VERSION 5.8 ;
BUSBITCHARS "[]" ;
DIVIDERCHAR "/" ;
UNITS
    DATABASE MICRONS 1000 ;
END UNITS

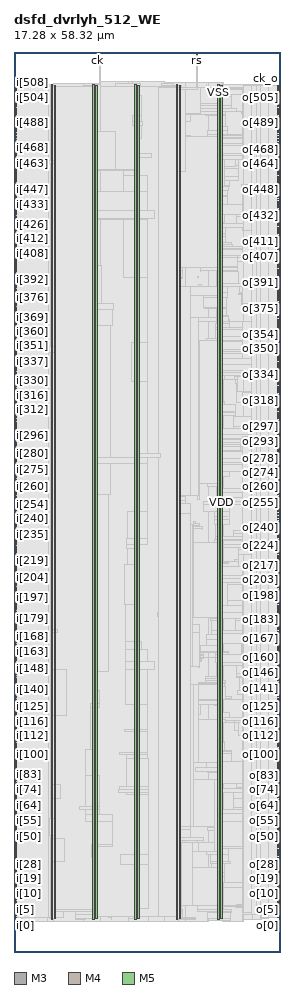
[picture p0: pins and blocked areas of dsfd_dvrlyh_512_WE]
MACRO dsfd_dvrlyh_512_WE
  FOREIGN dsfd_dvrlyh_512_WE 0 0 ;
  CLASS BLOCK ;
  SIZE 17.28 BY 58.32 ;
  PIN ck
    DIRECTION INPUT ;
    USE SIGNAL ;
    PORT
      LAYER M3 ;
        RECT  5.4 58.176 5.418 58.32 ;
    END
  END ck
  PIN ck_o
    DIRECTION OUTPUT ;
    USE SIGNAL ;
    PORT
      LAYER M4 ;
        RECT  17.088 56.112 17.28 56.136 ;
    END
  END ck_o
  PIN i[0]
    DIRECTION INPUT ;
    USE SIGNAL ;
    PORT
      LAYER M4 ;
        RECT  0 2.208 0.192 2.232 ;
    END
  END i[0]
  PIN i[100]
    DIRECTION INPUT ;
    USE SIGNAL ;
    PORT
      LAYER M4 ;
        RECT  0 12.768 0.192 12.792 ;
    END
  END i[100]
  PIN i[101]
    DIRECTION INPUT ;
    USE SIGNAL ;
    PORT
      LAYER M4 ;
        RECT  0 12.864 0.192 12.888 ;
    END
  END i[101]
  PIN i[102]
    DIRECTION INPUT ;
    USE SIGNAL ;
    PORT
      LAYER M4 ;
        RECT  0 12.96 0.192 12.984 ;
    END
  END i[102]
  PIN i[103]
    DIRECTION INPUT ;
    USE SIGNAL ;
    PORT
      LAYER M4 ;
        RECT  0 13.104 0.192 13.128 ;
    END
  END i[103]
  PIN i[104]
    DIRECTION INPUT ;
    USE SIGNAL ;
    PORT
      LAYER M4 ;
        RECT  0 13.2 0.192 13.224 ;
    END
  END i[104]
  PIN i[105]
    DIRECTION INPUT ;
    USE SIGNAL ;
    PORT
      LAYER M4 ;
        RECT  0 13.296 0.192 13.32 ;
    END
  END i[105]
  PIN i[106]
    DIRECTION INPUT ;
    USE SIGNAL ;
    PORT
      LAYER M4 ;
        RECT  0 13.392 0.192 13.416 ;
    END
  END i[106]
  PIN i[107]
    DIRECTION INPUT ;
    USE SIGNAL ;
    PORT
      LAYER M4 ;
        RECT  0 13.488 0.192 13.512 ;
    END
  END i[107]
  PIN i[108]
    DIRECTION INPUT ;
    USE SIGNAL ;
    PORT
      LAYER M4 ;
        RECT  0 13.632 0.192 13.656 ;
    END
  END i[108]
  PIN i[109]
    DIRECTION INPUT ;
    USE SIGNAL ;
    PORT
      LAYER M4 ;
        RECT  0 13.728 0.192 13.752 ;
    END
  END i[109]
  PIN i[10]
    DIRECTION INPUT ;
    USE SIGNAL ;
    PORT
      LAYER M4 ;
        RECT  0 3.264 0.192 3.288 ;
    END
  END i[10]
  PIN i[110]
    DIRECTION INPUT ;
    USE SIGNAL ;
    PORT
      LAYER M4 ;
        RECT  0 13.824 0.192 13.848 ;
    END
  END i[110]
  PIN i[111]
    DIRECTION INPUT ;
    USE SIGNAL ;
    PORT
      LAYER M4 ;
        RECT  0 13.92 0.192 13.944 ;
    END
  END i[111]
  PIN i[112]
    DIRECTION INPUT ;
    USE SIGNAL ;
    PORT
      LAYER M4 ;
        RECT  0 14.016 0.192 14.04 ;
    END
  END i[112]
  PIN i[113]
    DIRECTION INPUT ;
    USE SIGNAL ;
    PORT
      LAYER M4 ;
        RECT  0 14.16 0.192 14.184 ;
    END
  END i[113]
  PIN i[114]
    DIRECTION INPUT ;
    USE SIGNAL ;
    PORT
      LAYER M4 ;
        RECT  0 14.256 0.192 14.28 ;
    END
  END i[114]
  PIN i[115]
    DIRECTION INPUT ;
    USE SIGNAL ;
    PORT
      LAYER M4 ;
        RECT  0 14.352 0.192 14.376 ;
    END
  END i[115]
  PIN i[116]
    DIRECTION INPUT ;
    USE SIGNAL ;
    PORT
      LAYER M4 ;
        RECT  0 14.448 0.192 14.472 ;
    END
  END i[116]
  PIN i[117]
    DIRECTION INPUT ;
    USE SIGNAL ;
    PORT
      LAYER M4 ;
        RECT  0 14.544 0.192 14.568 ;
    END
  END i[117]
  PIN i[118]
    DIRECTION INPUT ;
    USE SIGNAL ;
    PORT
      LAYER M4 ;
        RECT  0 14.688 0.192 14.712 ;
    END
  END i[118]
  PIN i[119]
    DIRECTION INPUT ;
    USE SIGNAL ;
    PORT
      LAYER M4 ;
        RECT  0 14.784 0.192 14.808 ;
    END
  END i[119]
  PIN i[11]
    DIRECTION INPUT ;
    USE SIGNAL ;
    PORT
      LAYER M4 ;
        RECT  0 3.408 0.192 3.432 ;
    END
  END i[11]
  PIN i[120]
    DIRECTION INPUT ;
    USE SIGNAL ;
    PORT
      LAYER M4 ;
        RECT  0 14.88 0.192 14.904 ;
    END
  END i[120]
  PIN i[121]
    DIRECTION INPUT ;
    USE SIGNAL ;
    PORT
      LAYER M4 ;
        RECT  0 14.976 0.192 15 ;
    END
  END i[121]
  PIN i[122]
    DIRECTION INPUT ;
    USE SIGNAL ;
    PORT
      LAYER M4 ;
        RECT  0 15.072 0.192 15.096 ;
    END
  END i[122]
  PIN i[123]
    DIRECTION INPUT ;
    USE SIGNAL ;
    PORT
      LAYER M4 ;
        RECT  0 15.216 0.192 15.24 ;
    END
  END i[123]
  PIN i[124]
    DIRECTION INPUT ;
    USE SIGNAL ;
    PORT
      LAYER M4 ;
        RECT  0 15.312 0.192 15.336 ;
    END
  END i[124]
  PIN i[125]
    DIRECTION INPUT ;
    USE SIGNAL ;
    PORT
      LAYER M4 ;
        RECT  0 15.408 0.192 15.432 ;
    END
  END i[125]
  PIN i[126]
    DIRECTION INPUT ;
    USE SIGNAL ;
    PORT
      LAYER M4 ;
        RECT  0 15.504 0.192 15.528 ;
    END
  END i[126]
  PIN i[127]
    DIRECTION INPUT ;
    USE SIGNAL ;
    PORT
      LAYER M4 ;
        RECT  0 15.6 0.192 15.624 ;
    END
  END i[127]
  PIN i[128]
    DIRECTION INPUT ;
    USE SIGNAL ;
    PORT
      LAYER M4 ;
        RECT  0 15.744 0.192 15.768 ;
    END
  END i[128]
  PIN i[129]
    DIRECTION INPUT ;
    USE SIGNAL ;
    PORT
      LAYER M4 ;
        RECT  0 15.84 0.192 15.864 ;
    END
  END i[129]
  PIN i[12]
    DIRECTION INPUT ;
    USE SIGNAL ;
    PORT
      LAYER M4 ;
        RECT  0 3.504 0.192 3.528 ;
    END
  END i[12]
  PIN i[130]
    DIRECTION INPUT ;
    USE SIGNAL ;
    PORT
      LAYER M4 ;
        RECT  0 15.936 0.192 15.96 ;
    END
  END i[130]
  PIN i[131]
    DIRECTION INPUT ;
    USE SIGNAL ;
    PORT
      LAYER M4 ;
        RECT  0 16.032 0.192 16.056 ;
    END
  END i[131]
  PIN i[132]
    DIRECTION INPUT ;
    USE SIGNAL ;
    PORT
      LAYER M4 ;
        RECT  0 16.128 0.192 16.152 ;
    END
  END i[132]
  PIN i[133]
    DIRECTION INPUT ;
    USE SIGNAL ;
    PORT
      LAYER M4 ;
        RECT  0 16.272 0.192 16.296 ;
    END
  END i[133]
  PIN i[134]
    DIRECTION INPUT ;
    USE SIGNAL ;
    PORT
      LAYER M4 ;
        RECT  0 16.368 0.192 16.392 ;
    END
  END i[134]
  PIN i[135]
    DIRECTION INPUT ;
    USE SIGNAL ;
    PORT
      LAYER M4 ;
        RECT  0 16.464 0.192 16.488 ;
    END
  END i[135]
  PIN i[136]
    DIRECTION INPUT ;
    USE SIGNAL ;
    PORT
      LAYER M4 ;
        RECT  0 16.56 0.192 16.584 ;
    END
  END i[136]
  PIN i[137]
    DIRECTION INPUT ;
    USE SIGNAL ;
    PORT
      LAYER M4 ;
        RECT  0 16.656 0.192 16.68 ;
    END
  END i[137]
  PIN i[138]
    DIRECTION INPUT ;
    USE SIGNAL ;
    PORT
      LAYER M4 ;
        RECT  0 16.8 0.192 16.824 ;
    END
  END i[138]
  PIN i[139]
    DIRECTION INPUT ;
    USE SIGNAL ;
    PORT
      LAYER M4 ;
        RECT  0 16.896 0.192 16.92 ;
    END
  END i[139]
  PIN i[13]
    DIRECTION INPUT ;
    USE SIGNAL ;
    PORT
      LAYER M4 ;
        RECT  0 3.6 0.192 3.624 ;
    END
  END i[13]
  PIN i[140]
    DIRECTION INPUT ;
    USE SIGNAL ;
    PORT
      LAYER M4 ;
        RECT  0 16.992 0.192 17.016 ;
    END
  END i[140]
  PIN i[141]
    DIRECTION INPUT ;
    USE SIGNAL ;
    PORT
      LAYER M4 ;
        RECT  0 17.088 0.192 17.112 ;
    END
  END i[141]
  PIN i[142]
    DIRECTION INPUT ;
    USE SIGNAL ;
    PORT
      LAYER M4 ;
        RECT  0 17.184 0.192 17.208 ;
    END
  END i[142]
  PIN i[143]
    DIRECTION INPUT ;
    USE SIGNAL ;
    PORT
      LAYER M4 ;
        RECT  0 17.328 0.192 17.352 ;
    END
  END i[143]
  PIN i[144]
    DIRECTION INPUT ;
    USE SIGNAL ;
    PORT
      LAYER M4 ;
        RECT  0 17.424 0.192 17.448 ;
    END
  END i[144]
  PIN i[145]
    DIRECTION INPUT ;
    USE SIGNAL ;
    PORT
      LAYER M4 ;
        RECT  0 17.52 0.192 17.544 ;
    END
  END i[145]
  PIN i[146]
    DIRECTION INPUT ;
    USE SIGNAL ;
    PORT
      LAYER M4 ;
        RECT  0 17.616 0.192 17.64 ;
    END
  END i[146]
  PIN i[147]
    DIRECTION INPUT ;
    USE SIGNAL ;
    PORT
      LAYER M4 ;
        RECT  0 17.712 0.192 17.736 ;
    END
  END i[147]
  PIN i[148]
    DIRECTION INPUT ;
    USE SIGNAL ;
    PORT
      LAYER M4 ;
        RECT  0 17.856 0.192 17.88 ;
    END
  END i[148]
  PIN i[149]
    DIRECTION INPUT ;
    USE SIGNAL ;
    PORT
      LAYER M4 ;
        RECT  0 17.952 0.192 17.976 ;
    END
  END i[149]
  PIN i[14]
    DIRECTION INPUT ;
    USE SIGNAL ;
    PORT
      LAYER M4 ;
        RECT  0 3.696 0.192 3.72 ;
    END
  END i[14]
  PIN i[150]
    DIRECTION INPUT ;
    USE SIGNAL ;
    PORT
      LAYER M4 ;
        RECT  0 18.048 0.192 18.072 ;
    END
  END i[150]
  PIN i[151]
    DIRECTION INPUT ;
    USE SIGNAL ;
    PORT
      LAYER M4 ;
        RECT  0 18.144 0.192 18.168 ;
    END
  END i[151]
  PIN i[152]
    DIRECTION INPUT ;
    USE SIGNAL ;
    PORT
      LAYER M4 ;
        RECT  0 18.24 0.192 18.264 ;
    END
  END i[152]
  PIN i[153]
    DIRECTION INPUT ;
    USE SIGNAL ;
    PORT
      LAYER M4 ;
        RECT  0 18.384 0.192 18.408 ;
    END
  END i[153]
  PIN i[154]
    DIRECTION INPUT ;
    USE SIGNAL ;
    PORT
      LAYER M4 ;
        RECT  0 18.48 0.192 18.504 ;
    END
  END i[154]
  PIN i[155]
    DIRECTION INPUT ;
    USE SIGNAL ;
    PORT
      LAYER M4 ;
        RECT  0 18.576 0.192 18.6 ;
    END
  END i[155]
  PIN i[156]
    DIRECTION INPUT ;
    USE SIGNAL ;
    PORT
      LAYER M4 ;
        RECT  0 18.672 0.192 18.696 ;
    END
  END i[156]
  PIN i[157]
    DIRECTION INPUT ;
    USE SIGNAL ;
    PORT
      LAYER M4 ;
        RECT  0 18.768 0.192 18.792 ;
    END
  END i[157]
  PIN i[158]
    DIRECTION INPUT ;
    USE SIGNAL ;
    PORT
      LAYER M4 ;
        RECT  0 18.912 0.192 18.936 ;
    END
  END i[158]
  PIN i[159]
    DIRECTION INPUT ;
    USE SIGNAL ;
    PORT
      LAYER M4 ;
        RECT  0 19.008 0.192 19.032 ;
    END
  END i[159]
  PIN i[15]
    DIRECTION INPUT ;
    USE SIGNAL ;
    PORT
      LAYER M4 ;
        RECT  0 3.792 0.192 3.816 ;
    END
  END i[15]
  PIN i[160]
    DIRECTION INPUT ;
    USE SIGNAL ;
    PORT
      LAYER M4 ;
        RECT  0 19.104 0.192 19.128 ;
    END
  END i[160]
  PIN i[161]
    DIRECTION INPUT ;
    USE SIGNAL ;
    PORT
      LAYER M4 ;
        RECT  0 19.2 0.192 19.224 ;
    END
  END i[161]
  PIN i[162]
    DIRECTION INPUT ;
    USE SIGNAL ;
    PORT
      LAYER M4 ;
        RECT  0 19.296 0.192 19.32 ;
    END
  END i[162]
  PIN i[163]
    DIRECTION INPUT ;
    USE SIGNAL ;
    PORT
      LAYER M4 ;
        RECT  0 19.44 0.192 19.464 ;
    END
  END i[163]
  PIN i[164]
    DIRECTION INPUT ;
    USE SIGNAL ;
    PORT
      LAYER M4 ;
        RECT  0 19.536 0.192 19.56 ;
    END
  END i[164]
  PIN i[165]
    DIRECTION INPUT ;
    USE SIGNAL ;
    PORT
      LAYER M4 ;
        RECT  0 19.632 0.192 19.656 ;
    END
  END i[165]
  PIN i[166]
    DIRECTION INPUT ;
    USE SIGNAL ;
    PORT
      LAYER M4 ;
        RECT  0 19.728 0.192 19.752 ;
    END
  END i[166]
  PIN i[167]
    DIRECTION INPUT ;
    USE SIGNAL ;
    PORT
      LAYER M4 ;
        RECT  0 19.824 0.192 19.848 ;
    END
  END i[167]
  PIN i[168]
    DIRECTION INPUT ;
    USE SIGNAL ;
    PORT
      LAYER M4 ;
        RECT  0 19.92 0.192 19.944 ;
    END
  END i[168]
  PIN i[169]
    DIRECTION INPUT ;
    USE SIGNAL ;
    PORT
      LAYER M4 ;
        RECT  0 20.064 0.192 20.088 ;
    END
  END i[169]
  PIN i[16]
    DIRECTION INPUT ;
    USE SIGNAL ;
    PORT
      LAYER M4 ;
        RECT  0 3.936 0.192 3.96 ;
    END
  END i[16]
  PIN i[170]
    DIRECTION INPUT ;
    USE SIGNAL ;
    PORT
      LAYER M4 ;
        RECT  0 20.16 0.192 20.184 ;
    END
  END i[170]
  PIN i[171]
    DIRECTION INPUT ;
    USE SIGNAL ;
    PORT
      LAYER M4 ;
        RECT  0 20.256 0.192 20.28 ;
    END
  END i[171]
  PIN i[172]
    DIRECTION INPUT ;
    USE SIGNAL ;
    PORT
      LAYER M4 ;
        RECT  0 20.352 0.192 20.376 ;
    END
  END i[172]
  PIN i[173]
    DIRECTION INPUT ;
    USE SIGNAL ;
    PORT
      LAYER M4 ;
        RECT  0 20.448 0.192 20.472 ;
    END
  END i[173]
  PIN i[174]
    DIRECTION INPUT ;
    USE SIGNAL ;
    PORT
      LAYER M4 ;
        RECT  0 20.592 0.192 20.616 ;
    END
  END i[174]
  PIN i[175]
    DIRECTION INPUT ;
    USE SIGNAL ;
    PORT
      LAYER M4 ;
        RECT  0 20.688 0.192 20.712 ;
    END
  END i[175]
  PIN i[176]
    DIRECTION INPUT ;
    USE SIGNAL ;
    PORT
      LAYER M4 ;
        RECT  0 20.784 0.192 20.808 ;
    END
  END i[176]
  PIN i[177]
    DIRECTION INPUT ;
    USE SIGNAL ;
    PORT
      LAYER M4 ;
        RECT  0 20.88 0.192 20.904 ;
    END
  END i[177]
  PIN i[178]
    DIRECTION INPUT ;
    USE SIGNAL ;
    PORT
      LAYER M4 ;
        RECT  0 20.976 0.192 21 ;
    END
  END i[178]
  PIN i[179]
    DIRECTION INPUT ;
    USE SIGNAL ;
    PORT
      LAYER M4 ;
        RECT  0 21.12 0.192 21.144 ;
    END
  END i[179]
  PIN i[17]
    DIRECTION INPUT ;
    USE SIGNAL ;
    PORT
      LAYER M4 ;
        RECT  0 4.032 0.192 4.056 ;
    END
  END i[17]
  PIN i[180]
    DIRECTION INPUT ;
    USE SIGNAL ;
    PORT
      LAYER M4 ;
        RECT  0 21.216 0.192 21.24 ;
    END
  END i[180]
  PIN i[181]
    DIRECTION INPUT ;
    USE SIGNAL ;
    PORT
      LAYER M4 ;
        RECT  0 21.312 0.192 21.336 ;
    END
  END i[181]
  PIN i[182]
    DIRECTION INPUT ;
    USE SIGNAL ;
    PORT
      LAYER M4 ;
        RECT  0 21.408 0.192 21.432 ;
    END
  END i[182]
  PIN i[183]
    DIRECTION INPUT ;
    USE SIGNAL ;
    PORT
      LAYER M4 ;
        RECT  0 21.504 0.192 21.528 ;
    END
  END i[183]
  PIN i[184]
    DIRECTION INPUT ;
    USE SIGNAL ;
    PORT
      LAYER M4 ;
        RECT  0 21.648 0.192 21.672 ;
    END
  END i[184]
  PIN i[185]
    DIRECTION INPUT ;
    USE SIGNAL ;
    PORT
      LAYER M4 ;
        RECT  0 21.744 0.192 21.768 ;
    END
  END i[185]
  PIN i[186]
    DIRECTION INPUT ;
    USE SIGNAL ;
    PORT
      LAYER M4 ;
        RECT  0 21.84 0.192 21.864 ;
    END
  END i[186]
  PIN i[187]
    DIRECTION INPUT ;
    USE SIGNAL ;
    PORT
      LAYER M4 ;
        RECT  0 21.936 0.192 21.96 ;
    END
  END i[187]
  PIN i[188]
    DIRECTION INPUT ;
    USE SIGNAL ;
    PORT
      LAYER M4 ;
        RECT  0 22.032 0.192 22.056 ;
    END
  END i[188]
  PIN i[189]
    DIRECTION INPUT ;
    USE SIGNAL ;
    PORT
      LAYER M4 ;
        RECT  0 22.176 0.192 22.2 ;
    END
  END i[189]
  PIN i[18]
    DIRECTION INPUT ;
    USE SIGNAL ;
    PORT
      LAYER M4 ;
        RECT  0 4.128 0.192 4.152 ;
    END
  END i[18]
  PIN i[190]
    DIRECTION INPUT ;
    USE SIGNAL ;
    PORT
      LAYER M4 ;
        RECT  0 22.272 0.192 22.296 ;
    END
  END i[190]
  PIN i[191]
    DIRECTION INPUT ;
    USE SIGNAL ;
    PORT
      LAYER M4 ;
        RECT  0 22.368 0.192 22.392 ;
    END
  END i[191]
  PIN i[192]
    DIRECTION INPUT ;
    USE SIGNAL ;
    PORT
      LAYER M4 ;
        RECT  0 22.464 0.192 22.488 ;
    END
  END i[192]
  PIN i[193]
    DIRECTION INPUT ;
    USE SIGNAL ;
    PORT
      LAYER M4 ;
        RECT  0 22.56 0.192 22.584 ;
    END
  END i[193]
  PIN i[194]
    DIRECTION INPUT ;
    USE SIGNAL ;
    PORT
      LAYER M4 ;
        RECT  0 22.704 0.192 22.728 ;
    END
  END i[194]
  PIN i[195]
    DIRECTION INPUT ;
    USE SIGNAL ;
    PORT
      LAYER M4 ;
        RECT  0 22.8 0.192 22.824 ;
    END
  END i[195]
  PIN i[196]
    DIRECTION INPUT ;
    USE SIGNAL ;
    PORT
      LAYER M4 ;
        RECT  0 22.896 0.192 22.92 ;
    END
  END i[196]
  PIN i[197]
    DIRECTION INPUT ;
    USE SIGNAL ;
    PORT
      LAYER M4 ;
        RECT  0 22.992 0.192 23.016 ;
    END
  END i[197]
  PIN i[198]
    DIRECTION INPUT ;
    USE SIGNAL ;
    PORT
      LAYER M4 ;
        RECT  0 23.088 0.192 23.112 ;
    END
  END i[198]
  PIN i[199]
    DIRECTION INPUT ;
    USE SIGNAL ;
    PORT
      LAYER M4 ;
        RECT  0 23.232 0.192 23.256 ;
    END
  END i[199]
  PIN i[19]
    DIRECTION INPUT ;
    USE SIGNAL ;
    PORT
      LAYER M4 ;
        RECT  0 4.224 0.192 4.248 ;
    END
  END i[19]
  PIN i[1]
    DIRECTION INPUT ;
    USE SIGNAL ;
    PORT
      LAYER M4 ;
        RECT  0 2.352 0.192 2.376 ;
    END
  END i[1]
  PIN i[200]
    DIRECTION INPUT ;
    USE SIGNAL ;
    PORT
      LAYER M4 ;
        RECT  0 23.328 0.192 23.352 ;
    END
  END i[200]
  PIN i[201]
    DIRECTION INPUT ;
    USE SIGNAL ;
    PORT
      LAYER M4 ;
        RECT  0 23.424 0.192 23.448 ;
    END
  END i[201]
  PIN i[202]
    DIRECTION INPUT ;
    USE SIGNAL ;
    PORT
      LAYER M4 ;
        RECT  0 23.52 0.192 23.544 ;
    END
  END i[202]
  PIN i[203]
    DIRECTION INPUT ;
    USE SIGNAL ;
    PORT
      LAYER M4 ;
        RECT  0 23.616 0.192 23.64 ;
    END
  END i[203]
  PIN i[204]
    DIRECTION INPUT ;
    USE SIGNAL ;
    PORT
      LAYER M4 ;
        RECT  0 23.76 0.192 23.784 ;
    END
  END i[204]
  PIN i[205]
    DIRECTION INPUT ;
    USE SIGNAL ;
    PORT
      LAYER M4 ;
        RECT  0 23.856 0.192 23.88 ;
    END
  END i[205]
  PIN i[206]
    DIRECTION INPUT ;
    USE SIGNAL ;
    PORT
      LAYER M4 ;
        RECT  0 23.952 0.192 23.976 ;
    END
  END i[206]
  PIN i[207]
    DIRECTION INPUT ;
    USE SIGNAL ;
    PORT
      LAYER M4 ;
        RECT  0 24.048 0.192 24.072 ;
    END
  END i[207]
  PIN i[208]
    DIRECTION INPUT ;
    USE SIGNAL ;
    PORT
      LAYER M4 ;
        RECT  0 24.144 0.192 24.168 ;
    END
  END i[208]
  PIN i[209]
    DIRECTION INPUT ;
    USE SIGNAL ;
    PORT
      LAYER M4 ;
        RECT  0 24.288 0.192 24.312 ;
    END
  END i[209]
  PIN i[20]
    DIRECTION INPUT ;
    USE SIGNAL ;
    PORT
      LAYER M4 ;
        RECT  0 4.32 0.192 4.344 ;
    END
  END i[20]
  PIN i[210]
    DIRECTION INPUT ;
    USE SIGNAL ;
    PORT
      LAYER M4 ;
        RECT  0 24.384 0.192 24.408 ;
    END
  END i[210]
  PIN i[211]
    DIRECTION INPUT ;
    USE SIGNAL ;
    PORT
      LAYER M4 ;
        RECT  0 24.48 0.192 24.504 ;
    END
  END i[211]
  PIN i[212]
    DIRECTION INPUT ;
    USE SIGNAL ;
    PORT
      LAYER M4 ;
        RECT  0 24.576 0.192 24.6 ;
    END
  END i[212]
  PIN i[213]
    DIRECTION INPUT ;
    USE SIGNAL ;
    PORT
      LAYER M4 ;
        RECT  0 24.672 0.192 24.696 ;
    END
  END i[213]
  PIN i[214]
    DIRECTION INPUT ;
    USE SIGNAL ;
    PORT
      LAYER M4 ;
        RECT  0 24.816 0.192 24.84 ;
    END
  END i[214]
  PIN i[215]
    DIRECTION INPUT ;
    USE SIGNAL ;
    PORT
      LAYER M4 ;
        RECT  0 24.912 0.192 24.936 ;
    END
  END i[215]
  PIN i[216]
    DIRECTION INPUT ;
    USE SIGNAL ;
    PORT
      LAYER M4 ;
        RECT  0 25.008 0.192 25.032 ;
    END
  END i[216]
  PIN i[217]
    DIRECTION INPUT ;
    USE SIGNAL ;
    PORT
      LAYER M4 ;
        RECT  0 25.104 0.192 25.128 ;
    END
  END i[217]
  PIN i[218]
    DIRECTION INPUT ;
    USE SIGNAL ;
    PORT
      LAYER M4 ;
        RECT  0 25.2 0.192 25.224 ;
    END
  END i[218]
  PIN i[219]
    DIRECTION INPUT ;
    USE SIGNAL ;
    PORT
      LAYER M4 ;
        RECT  0 25.344 0.192 25.368 ;
    END
  END i[219]
  PIN i[21]
    DIRECTION INPUT ;
    USE SIGNAL ;
    PORT
      LAYER M4 ;
        RECT  0 4.416 0.192 4.44 ;
    END
  END i[21]
  PIN i[220]
    DIRECTION INPUT ;
    USE SIGNAL ;
    PORT
      LAYER M4 ;
        RECT  0 25.44 0.192 25.464 ;
    END
  END i[220]
  PIN i[221]
    DIRECTION INPUT ;
    USE SIGNAL ;
    PORT
      LAYER M4 ;
        RECT  0 25.536 0.192 25.56 ;
    END
  END i[221]
  PIN i[222]
    DIRECTION INPUT ;
    USE SIGNAL ;
    PORT
      LAYER M4 ;
        RECT  0 25.632 0.192 25.656 ;
    END
  END i[222]
  PIN i[223]
    DIRECTION INPUT ;
    USE SIGNAL ;
    PORT
      LAYER M4 ;
        RECT  0 25.728 0.192 25.752 ;
    END
  END i[223]
  PIN i[224]
    DIRECTION INPUT ;
    USE SIGNAL ;
    PORT
      LAYER M4 ;
        RECT  0 25.872 0.192 25.896 ;
    END
  END i[224]
  PIN i[225]
    DIRECTION INPUT ;
    USE SIGNAL ;
    PORT
      LAYER M4 ;
        RECT  0 25.968 0.192 25.992 ;
    END
  END i[225]
  PIN i[226]
    DIRECTION INPUT ;
    USE SIGNAL ;
    PORT
      LAYER M4 ;
        RECT  0 26.064 0.192 26.088 ;
    END
  END i[226]
  PIN i[227]
    DIRECTION INPUT ;
    USE SIGNAL ;
    PORT
      LAYER M4 ;
        RECT  0 26.16 0.192 26.184 ;
    END
  END i[227]
  PIN i[228]
    DIRECTION INPUT ;
    USE SIGNAL ;
    PORT
      LAYER M4 ;
        RECT  0 26.256 0.192 26.28 ;
    END
  END i[228]
  PIN i[229]
    DIRECTION INPUT ;
    USE SIGNAL ;
    PORT
      LAYER M4 ;
        RECT  0 26.4 0.192 26.424 ;
    END
  END i[229]
  PIN i[22]
    DIRECTION INPUT ;
    USE SIGNAL ;
    PORT
      LAYER M4 ;
        RECT  0 4.56 0.192 4.584 ;
    END
  END i[22]
  PIN i[230]
    DIRECTION INPUT ;
    USE SIGNAL ;
    PORT
      LAYER M4 ;
        RECT  0 26.496 0.192 26.52 ;
    END
  END i[230]
  PIN i[231]
    DIRECTION INPUT ;
    USE SIGNAL ;
    PORT
      LAYER M4 ;
        RECT  0 26.592 0.192 26.616 ;
    END
  END i[231]
  PIN i[232]
    DIRECTION INPUT ;
    USE SIGNAL ;
    PORT
      LAYER M4 ;
        RECT  0 26.688 0.192 26.712 ;
    END
  END i[232]
  PIN i[233]
    DIRECTION INPUT ;
    USE SIGNAL ;
    PORT
      LAYER M4 ;
        RECT  0 26.784 0.192 26.808 ;
    END
  END i[233]
  PIN i[234]
    DIRECTION INPUT ;
    USE SIGNAL ;
    PORT
      LAYER M4 ;
        RECT  0 26.928 0.192 26.952 ;
    END
  END i[234]
  PIN i[235]
    DIRECTION INPUT ;
    USE SIGNAL ;
    PORT
      LAYER M4 ;
        RECT  0 27.024 0.192 27.048 ;
    END
  END i[235]
  PIN i[236]
    DIRECTION INPUT ;
    USE SIGNAL ;
    PORT
      LAYER M4 ;
        RECT  0 27.12 0.192 27.144 ;
    END
  END i[236]
  PIN i[237]
    DIRECTION INPUT ;
    USE SIGNAL ;
    PORT
      LAYER M4 ;
        RECT  0 27.216 0.192 27.24 ;
    END
  END i[237]
  PIN i[238]
    DIRECTION INPUT ;
    USE SIGNAL ;
    PORT
      LAYER M4 ;
        RECT  0 27.312 0.192 27.336 ;
    END
  END i[238]
  PIN i[239]
    DIRECTION INPUT ;
    USE SIGNAL ;
    PORT
      LAYER M4 ;
        RECT  0 27.408 0.192 27.432 ;
    END
  END i[239]
  PIN i[23]
    DIRECTION INPUT ;
    USE SIGNAL ;
    PORT
      LAYER M4 ;
        RECT  0 4.656 0.192 4.68 ;
    END
  END i[23]
  PIN i[240]
    DIRECTION INPUT ;
    USE SIGNAL ;
    PORT
      LAYER M4 ;
        RECT  0 27.552 0.192 27.576 ;
    END
  END i[240]
  PIN i[241]
    DIRECTION INPUT ;
    USE SIGNAL ;
    PORT
      LAYER M4 ;
        RECT  0 27.648 0.192 27.672 ;
    END
  END i[241]
  PIN i[242]
    DIRECTION INPUT ;
    USE SIGNAL ;
    PORT
      LAYER M4 ;
        RECT  0 27.744 0.192 27.768 ;
    END
  END i[242]
  PIN i[243]
    DIRECTION INPUT ;
    USE SIGNAL ;
    PORT
      LAYER M4 ;
        RECT  0 27.84 0.192 27.864 ;
    END
  END i[243]
  PIN i[244]
    DIRECTION INPUT ;
    USE SIGNAL ;
    PORT
      LAYER M4 ;
        RECT  0 27.936 0.192 27.96 ;
    END
  END i[244]
  PIN i[245]
    DIRECTION INPUT ;
    USE SIGNAL ;
    PORT
      LAYER M4 ;
        RECT  0 28.08 0.192 28.104 ;
    END
  END i[245]
  PIN i[246]
    DIRECTION INPUT ;
    USE SIGNAL ;
    PORT
      LAYER M4 ;
        RECT  0 28.176 0.192 28.2 ;
    END
  END i[246]
  PIN i[247]
    DIRECTION INPUT ;
    USE SIGNAL ;
    PORT
      LAYER M4 ;
        RECT  0 28.272 0.192 28.296 ;
    END
  END i[247]
  PIN i[248]
    DIRECTION INPUT ;
    USE SIGNAL ;
    PORT
      LAYER M4 ;
        RECT  0 28.368 0.192 28.392 ;
    END
  END i[248]
  PIN i[249]
    DIRECTION INPUT ;
    USE SIGNAL ;
    PORT
      LAYER M4 ;
        RECT  0 28.464 0.192 28.488 ;
    END
  END i[249]
  PIN i[24]
    DIRECTION INPUT ;
    USE SIGNAL ;
    PORT
      LAYER M4 ;
        RECT  0 4.752 0.192 4.776 ;
    END
  END i[24]
  PIN i[250]
    DIRECTION INPUT ;
    USE SIGNAL ;
    PORT
      LAYER M4 ;
        RECT  0 28.608 0.192 28.632 ;
    END
  END i[250]
  PIN i[251]
    DIRECTION INPUT ;
    USE SIGNAL ;
    PORT
      LAYER M4 ;
        RECT  0 28.704 0.192 28.728 ;
    END
  END i[251]
  PIN i[252]
    DIRECTION INPUT ;
    USE SIGNAL ;
    PORT
      LAYER M4 ;
        RECT  0 28.8 0.192 28.824 ;
    END
  END i[252]
  PIN i[253]
    DIRECTION INPUT ;
    USE SIGNAL ;
    PORT
      LAYER M4 ;
        RECT  0 28.896 0.192 28.92 ;
    END
  END i[253]
  PIN i[254]
    DIRECTION INPUT ;
    USE SIGNAL ;
    PORT
      LAYER M4 ;
        RECT  0 28.992 0.192 29.016 ;
    END
  END i[254]
  PIN i[255]
    DIRECTION INPUT ;
    USE SIGNAL ;
    PORT
      LAYER M4 ;
        RECT  0 29.136 0.192 29.16 ;
    END
  END i[255]
  PIN i[256]
    DIRECTION INPUT ;
    USE SIGNAL ;
    PORT
      LAYER M4 ;
        RECT  0 29.232 0.192 29.256 ;
    END
  END i[256]
  PIN i[257]
    DIRECTION INPUT ;
    USE SIGNAL ;
    PORT
      LAYER M4 ;
        RECT  0 29.328 0.192 29.352 ;
    END
  END i[257]
  PIN i[258]
    DIRECTION INPUT ;
    USE SIGNAL ;
    PORT
      LAYER M4 ;
        RECT  0 29.424 0.192 29.448 ;
    END
  END i[258]
  PIN i[259]
    DIRECTION INPUT ;
    USE SIGNAL ;
    PORT
      LAYER M4 ;
        RECT  0 29.52 0.192 29.544 ;
    END
  END i[259]
  PIN i[25]
    DIRECTION INPUT ;
    USE SIGNAL ;
    PORT
      LAYER M4 ;
        RECT  0 4.848 0.192 4.872 ;
    END
  END i[25]
  PIN i[260]
    DIRECTION INPUT ;
    USE SIGNAL ;
    PORT
      LAYER M4 ;
        RECT  0 29.664 0.192 29.688 ;
    END
  END i[260]
  PIN i[261]
    DIRECTION INPUT ;
    USE SIGNAL ;
    PORT
      LAYER M4 ;
        RECT  0 29.76 0.192 29.784 ;
    END
  END i[261]
  PIN i[262]
    DIRECTION INPUT ;
    USE SIGNAL ;
    PORT
      LAYER M4 ;
        RECT  0 29.856 0.192 29.88 ;
    END
  END i[262]
  PIN i[263]
    DIRECTION INPUT ;
    USE SIGNAL ;
    PORT
      LAYER M4 ;
        RECT  0 29.952 0.192 29.976 ;
    END
  END i[263]
  PIN i[264]
    DIRECTION INPUT ;
    USE SIGNAL ;
    PORT
      LAYER M4 ;
        RECT  0 30.048 0.192 30.072 ;
    END
  END i[264]
  PIN i[265]
    DIRECTION INPUT ;
    USE SIGNAL ;
    PORT
      LAYER M4 ;
        RECT  0 30.192 0.192 30.216 ;
    END
  END i[265]
  PIN i[266]
    DIRECTION INPUT ;
    USE SIGNAL ;
    PORT
      LAYER M4 ;
        RECT  0 30.288 0.192 30.312 ;
    END
  END i[266]
  PIN i[267]
    DIRECTION INPUT ;
    USE SIGNAL ;
    PORT
      LAYER M4 ;
        RECT  0 30.384 0.192 30.408 ;
    END
  END i[267]
  PIN i[268]
    DIRECTION INPUT ;
    USE SIGNAL ;
    PORT
      LAYER M4 ;
        RECT  0 30.48 0.192 30.504 ;
    END
  END i[268]
  PIN i[269]
    DIRECTION INPUT ;
    USE SIGNAL ;
    PORT
      LAYER M4 ;
        RECT  0 30.576 0.192 30.6 ;
    END
  END i[269]
  PIN i[26]
    DIRECTION INPUT ;
    USE SIGNAL ;
    PORT
      LAYER M4 ;
        RECT  0 4.944 0.192 4.968 ;
    END
  END i[26]
  PIN i[270]
    DIRECTION INPUT ;
    USE SIGNAL ;
    PORT
      LAYER M4 ;
        RECT  0 30.72 0.192 30.744 ;
    END
  END i[270]
  PIN i[271]
    DIRECTION INPUT ;
    USE SIGNAL ;
    PORT
      LAYER M4 ;
        RECT  0 30.816 0.192 30.84 ;
    END
  END i[271]
  PIN i[272]
    DIRECTION INPUT ;
    USE SIGNAL ;
    PORT
      LAYER M4 ;
        RECT  0 30.912 0.192 30.936 ;
    END
  END i[272]
  PIN i[273]
    DIRECTION INPUT ;
    USE SIGNAL ;
    PORT
      LAYER M4 ;
        RECT  0 31.008 0.192 31.032 ;
    END
  END i[273]
  PIN i[274]
    DIRECTION INPUT ;
    USE SIGNAL ;
    PORT
      LAYER M4 ;
        RECT  0 31.104 0.192 31.128 ;
    END
  END i[274]
  PIN i[275]
    DIRECTION INPUT ;
    USE SIGNAL ;
    PORT
      LAYER M4 ;
        RECT  0 31.248 0.192 31.272 ;
    END
  END i[275]
  PIN i[276]
    DIRECTION INPUT ;
    USE SIGNAL ;
    PORT
      LAYER M4 ;
        RECT  0 31.344 0.192 31.368 ;
    END
  END i[276]
  PIN i[277]
    DIRECTION INPUT ;
    USE SIGNAL ;
    PORT
      LAYER M4 ;
        RECT  0 31.44 0.192 31.464 ;
    END
  END i[277]
  PIN i[278]
    DIRECTION INPUT ;
    USE SIGNAL ;
    PORT
      LAYER M4 ;
        RECT  0 31.536 0.192 31.56 ;
    END
  END i[278]
  PIN i[279]
    DIRECTION INPUT ;
    USE SIGNAL ;
    PORT
      LAYER M4 ;
        RECT  0 31.632 0.192 31.656 ;
    END
  END i[279]
  PIN i[27]
    DIRECTION INPUT ;
    USE SIGNAL ;
    PORT
      LAYER M4 ;
        RECT  0 5.088 0.192 5.112 ;
    END
  END i[27]
  PIN i[280]
    DIRECTION INPUT ;
    USE SIGNAL ;
    PORT
      LAYER M4 ;
        RECT  0 31.776 0.192 31.8 ;
    END
  END i[280]
  PIN i[281]
    DIRECTION INPUT ;
    USE SIGNAL ;
    PORT
      LAYER M4 ;
        RECT  0 31.872 0.192 31.896 ;
    END
  END i[281]
  PIN i[282]
    DIRECTION INPUT ;
    USE SIGNAL ;
    PORT
      LAYER M4 ;
        RECT  0 31.968 0.192 31.992 ;
    END
  END i[282]
  PIN i[283]
    DIRECTION INPUT ;
    USE SIGNAL ;
    PORT
      LAYER M4 ;
        RECT  0 32.064 0.192 32.088 ;
    END
  END i[283]
  PIN i[284]
    DIRECTION INPUT ;
    USE SIGNAL ;
    PORT
      LAYER M4 ;
        RECT  0 32.16 0.192 32.184 ;
    END
  END i[284]
  PIN i[285]
    DIRECTION INPUT ;
    USE SIGNAL ;
    PORT
      LAYER M4 ;
        RECT  0 32.304 0.192 32.328 ;
    END
  END i[285]
  PIN i[286]
    DIRECTION INPUT ;
    USE SIGNAL ;
    PORT
      LAYER M4 ;
        RECT  0 32.4 0.192 32.424 ;
    END
  END i[286]
  PIN i[287]
    DIRECTION INPUT ;
    USE SIGNAL ;
    PORT
      LAYER M4 ;
        RECT  0 32.496 0.192 32.52 ;
    END
  END i[287]
  PIN i[288]
    DIRECTION INPUT ;
    USE SIGNAL ;
    PORT
      LAYER M4 ;
        RECT  0 32.592 0.192 32.616 ;
    END
  END i[288]
  PIN i[289]
    DIRECTION INPUT ;
    USE SIGNAL ;
    PORT
      LAYER M4 ;
        RECT  0 32.688 0.192 32.712 ;
    END
  END i[289]
  PIN i[28]
    DIRECTION INPUT ;
    USE SIGNAL ;
    PORT
      LAYER M4 ;
        RECT  0 5.184 0.192 5.208 ;
    END
  END i[28]
  PIN i[290]
    DIRECTION INPUT ;
    USE SIGNAL ;
    PORT
      LAYER M4 ;
        RECT  0 32.832 0.192 32.856 ;
    END
  END i[290]
  PIN i[291]
    DIRECTION INPUT ;
    USE SIGNAL ;
    PORT
      LAYER M4 ;
        RECT  0 32.928 0.192 32.952 ;
    END
  END i[291]
  PIN i[292]
    DIRECTION INPUT ;
    USE SIGNAL ;
    PORT
      LAYER M4 ;
        RECT  0 33.024 0.192 33.048 ;
    END
  END i[292]
  PIN i[293]
    DIRECTION INPUT ;
    USE SIGNAL ;
    PORT
      LAYER M4 ;
        RECT  0 33.12 0.192 33.144 ;
    END
  END i[293]
  PIN i[294]
    DIRECTION INPUT ;
    USE SIGNAL ;
    PORT
      LAYER M4 ;
        RECT  0 33.216 0.192 33.24 ;
    END
  END i[294]
  PIN i[295]
    DIRECTION INPUT ;
    USE SIGNAL ;
    PORT
      LAYER M4 ;
        RECT  0 33.36 0.192 33.384 ;
    END
  END i[295]
  PIN i[296]
    DIRECTION INPUT ;
    USE SIGNAL ;
    PORT
      LAYER M4 ;
        RECT  0 33.456 0.192 33.48 ;
    END
  END i[296]
  PIN i[297]
    DIRECTION INPUT ;
    USE SIGNAL ;
    PORT
      LAYER M4 ;
        RECT  0 33.552 0.192 33.576 ;
    END
  END i[297]
  PIN i[298]
    DIRECTION INPUT ;
    USE SIGNAL ;
    PORT
      LAYER M4 ;
        RECT  0 33.648 0.192 33.672 ;
    END
  END i[298]
  PIN i[299]
    DIRECTION INPUT ;
    USE SIGNAL ;
    PORT
      LAYER M4 ;
        RECT  0 33.744 0.192 33.768 ;
    END
  END i[299]
  PIN i[29]
    DIRECTION INPUT ;
    USE SIGNAL ;
    PORT
      LAYER M4 ;
        RECT  0 5.28 0.192 5.304 ;
    END
  END i[29]
  PIN i[2]
    DIRECTION INPUT ;
    USE SIGNAL ;
    PORT
      LAYER M4 ;
        RECT  0 2.448 0.192 2.472 ;
    END
  END i[2]
  PIN i[300]
    DIRECTION INPUT ;
    USE SIGNAL ;
    PORT
      LAYER M4 ;
        RECT  0 33.888 0.192 33.912 ;
    END
  END i[300]
  PIN i[301]
    DIRECTION INPUT ;
    USE SIGNAL ;
    PORT
      LAYER M4 ;
        RECT  0 33.984 0.192 34.008 ;
    END
  END i[301]
  PIN i[302]
    DIRECTION INPUT ;
    USE SIGNAL ;
    PORT
      LAYER M4 ;
        RECT  0 34.08 0.192 34.104 ;
    END
  END i[302]
  PIN i[303]
    DIRECTION INPUT ;
    USE SIGNAL ;
    PORT
      LAYER M4 ;
        RECT  0 34.176 0.192 34.2 ;
    END
  END i[303]
  PIN i[304]
    DIRECTION INPUT ;
    USE SIGNAL ;
    PORT
      LAYER M4 ;
        RECT  0 34.272 0.192 34.296 ;
    END
  END i[304]
  PIN i[305]
    DIRECTION INPUT ;
    USE SIGNAL ;
    PORT
      LAYER M4 ;
        RECT  0 34.416 0.192 34.44 ;
    END
  END i[305]
  PIN i[306]
    DIRECTION INPUT ;
    USE SIGNAL ;
    PORT
      LAYER M4 ;
        RECT  0 34.512 0.192 34.536 ;
    END
  END i[306]
  PIN i[307]
    DIRECTION INPUT ;
    USE SIGNAL ;
    PORT
      LAYER M4 ;
        RECT  0 34.608 0.192 34.632 ;
    END
  END i[307]
  PIN i[308]
    DIRECTION INPUT ;
    USE SIGNAL ;
    PORT
      LAYER M4 ;
        RECT  0 34.704 0.192 34.728 ;
    END
  END i[308]
  PIN i[309]
    DIRECTION INPUT ;
    USE SIGNAL ;
    PORT
      LAYER M4 ;
        RECT  0 34.8 0.192 34.824 ;
    END
  END i[309]
  PIN i[30]
    DIRECTION INPUT ;
    USE SIGNAL ;
    PORT
      LAYER M4 ;
        RECT  0 5.376 0.192 5.4 ;
    END
  END i[30]
  PIN i[310]
    DIRECTION INPUT ;
    USE SIGNAL ;
    PORT
      LAYER M4 ;
        RECT  0 34.944 0.192 34.968 ;
    END
  END i[310]
  PIN i[311]
    DIRECTION INPUT ;
    USE SIGNAL ;
    PORT
      LAYER M4 ;
        RECT  0 35.04 0.192 35.064 ;
    END
  END i[311]
  PIN i[312]
    DIRECTION INPUT ;
    USE SIGNAL ;
    PORT
      LAYER M4 ;
        RECT  0 35.136 0.192 35.16 ;
    END
  END i[312]
  PIN i[313]
    DIRECTION INPUT ;
    USE SIGNAL ;
    PORT
      LAYER M4 ;
        RECT  0 35.232 0.192 35.256 ;
    END
  END i[313]
  PIN i[314]
    DIRECTION INPUT ;
    USE SIGNAL ;
    PORT
      LAYER M4 ;
        RECT  0 35.328 0.192 35.352 ;
    END
  END i[314]
  PIN i[315]
    DIRECTION INPUT ;
    USE SIGNAL ;
    PORT
      LAYER M4 ;
        RECT  0 35.424 0.192 35.448 ;
    END
  END i[315]
  PIN i[316]
    DIRECTION INPUT ;
    USE SIGNAL ;
    PORT
      LAYER M4 ;
        RECT  0 35.568 0.192 35.592 ;
    END
  END i[316]
  PIN i[317]
    DIRECTION INPUT ;
    USE SIGNAL ;
    PORT
      LAYER M4 ;
        RECT  0 35.664 0.192 35.688 ;
    END
  END i[317]
  PIN i[318]
    DIRECTION INPUT ;
    USE SIGNAL ;
    PORT
      LAYER M4 ;
        RECT  0 35.76 0.192 35.784 ;
    END
  END i[318]
  PIN i[319]
    DIRECTION INPUT ;
    USE SIGNAL ;
    PORT
      LAYER M4 ;
        RECT  0 35.856 0.192 35.88 ;
    END
  END i[319]
  PIN i[31]
    DIRECTION INPUT ;
    USE SIGNAL ;
    PORT
      LAYER M4 ;
        RECT  0 5.472 0.192 5.496 ;
    END
  END i[31]
  PIN i[320]
    DIRECTION INPUT ;
    USE SIGNAL ;
    PORT
      LAYER M4 ;
        RECT  0 35.952 0.192 35.976 ;
    END
  END i[320]
  PIN i[321]
    DIRECTION INPUT ;
    USE SIGNAL ;
    PORT
      LAYER M4 ;
        RECT  0 36.096 0.192 36.12 ;
    END
  END i[321]
  PIN i[322]
    DIRECTION INPUT ;
    USE SIGNAL ;
    PORT
      LAYER M4 ;
        RECT  0 36.192 0.192 36.216 ;
    END
  END i[322]
  PIN i[323]
    DIRECTION INPUT ;
    USE SIGNAL ;
    PORT
      LAYER M4 ;
        RECT  0 36.288 0.192 36.312 ;
    END
  END i[323]
  PIN i[324]
    DIRECTION INPUT ;
    USE SIGNAL ;
    PORT
      LAYER M4 ;
        RECT  0 36.384 0.192 36.408 ;
    END
  END i[324]
  PIN i[325]
    DIRECTION INPUT ;
    USE SIGNAL ;
    PORT
      LAYER M4 ;
        RECT  0 36.48 0.192 36.504 ;
    END
  END i[325]
  PIN i[326]
    DIRECTION INPUT ;
    USE SIGNAL ;
    PORT
      LAYER M4 ;
        RECT  0 36.624 0.192 36.648 ;
    END
  END i[326]
  PIN i[327]
    DIRECTION INPUT ;
    USE SIGNAL ;
    PORT
      LAYER M4 ;
        RECT  0 36.72 0.192 36.744 ;
    END
  END i[327]
  PIN i[328]
    DIRECTION INPUT ;
    USE SIGNAL ;
    PORT
      LAYER M4 ;
        RECT  0 36.816 0.192 36.84 ;
    END
  END i[328]
  PIN i[329]
    DIRECTION INPUT ;
    USE SIGNAL ;
    PORT
      LAYER M4 ;
        RECT  0 36.912 0.192 36.936 ;
    END
  END i[329]
  PIN i[32]
    DIRECTION INPUT ;
    USE SIGNAL ;
    PORT
      LAYER M4 ;
        RECT  0 5.616 0.192 5.64 ;
    END
  END i[32]
  PIN i[330]
    DIRECTION INPUT ;
    USE SIGNAL ;
    PORT
      LAYER M4 ;
        RECT  0 37.008 0.192 37.032 ;
    END
  END i[330]
  PIN i[331]
    DIRECTION INPUT ;
    USE SIGNAL ;
    PORT
      LAYER M4 ;
        RECT  0 37.152 0.192 37.176 ;
    END
  END i[331]
  PIN i[332]
    DIRECTION INPUT ;
    USE SIGNAL ;
    PORT
      LAYER M4 ;
        RECT  0 37.248 0.192 37.272 ;
    END
  END i[332]
  PIN i[333]
    DIRECTION INPUT ;
    USE SIGNAL ;
    PORT
      LAYER M4 ;
        RECT  0 37.344 0.192 37.368 ;
    END
  END i[333]
  PIN i[334]
    DIRECTION INPUT ;
    USE SIGNAL ;
    PORT
      LAYER M4 ;
        RECT  0 37.44 0.192 37.464 ;
    END
  END i[334]
  PIN i[335]
    DIRECTION INPUT ;
    USE SIGNAL ;
    PORT
      LAYER M4 ;
        RECT  0 37.536 0.192 37.56 ;
    END
  END i[335]
  PIN i[336]
    DIRECTION INPUT ;
    USE SIGNAL ;
    PORT
      LAYER M4 ;
        RECT  0 37.68 0.192 37.704 ;
    END
  END i[336]
  PIN i[337]
    DIRECTION INPUT ;
    USE SIGNAL ;
    PORT
      LAYER M4 ;
        RECT  0 37.776 0.192 37.8 ;
    END
  END i[337]
  PIN i[338]
    DIRECTION INPUT ;
    USE SIGNAL ;
    PORT
      LAYER M4 ;
        RECT  0 37.872 0.192 37.896 ;
    END
  END i[338]
  PIN i[339]
    DIRECTION INPUT ;
    USE SIGNAL ;
    PORT
      LAYER M4 ;
        RECT  0 37.968 0.192 37.992 ;
    END
  END i[339]
  PIN i[33]
    DIRECTION INPUT ;
    USE SIGNAL ;
    PORT
      LAYER M4 ;
        RECT  0 5.712 0.192 5.736 ;
    END
  END i[33]
  PIN i[340]
    DIRECTION INPUT ;
    USE SIGNAL ;
    PORT
      LAYER M4 ;
        RECT  0 38.064 0.192 38.088 ;
    END
  END i[340]
  PIN i[341]
    DIRECTION INPUT ;
    USE SIGNAL ;
    PORT
      LAYER M4 ;
        RECT  0 38.208 0.192 38.232 ;
    END
  END i[341]
  PIN i[342]
    DIRECTION INPUT ;
    USE SIGNAL ;
    PORT
      LAYER M4 ;
        RECT  0 38.304 0.192 38.328 ;
    END
  END i[342]
  PIN i[343]
    DIRECTION INPUT ;
    USE SIGNAL ;
    PORT
      LAYER M4 ;
        RECT  0 38.4 0.192 38.424 ;
    END
  END i[343]
  PIN i[344]
    DIRECTION INPUT ;
    USE SIGNAL ;
    PORT
      LAYER M4 ;
        RECT  0 38.496 0.192 38.52 ;
    END
  END i[344]
  PIN i[345]
    DIRECTION INPUT ;
    USE SIGNAL ;
    PORT
      LAYER M4 ;
        RECT  0 38.592 0.192 38.616 ;
    END
  END i[345]
  PIN i[346]
    DIRECTION INPUT ;
    USE SIGNAL ;
    PORT
      LAYER M4 ;
        RECT  0 38.736 0.192 38.76 ;
    END
  END i[346]
  PIN i[347]
    DIRECTION INPUT ;
    USE SIGNAL ;
    PORT
      LAYER M4 ;
        RECT  0 38.832 0.192 38.856 ;
    END
  END i[347]
  PIN i[348]
    DIRECTION INPUT ;
    USE SIGNAL ;
    PORT
      LAYER M4 ;
        RECT  0 38.928 0.192 38.952 ;
    END
  END i[348]
  PIN i[349]
    DIRECTION INPUT ;
    USE SIGNAL ;
    PORT
      LAYER M4 ;
        RECT  0 39.024 0.192 39.048 ;
    END
  END i[349]
  PIN i[34]
    DIRECTION INPUT ;
    USE SIGNAL ;
    PORT
      LAYER M4 ;
        RECT  0 5.808 0.192 5.832 ;
    END
  END i[34]
  PIN i[350]
    DIRECTION INPUT ;
    USE SIGNAL ;
    PORT
      LAYER M4 ;
        RECT  0 39.12 0.192 39.144 ;
    END
  END i[350]
  PIN i[351]
    DIRECTION INPUT ;
    USE SIGNAL ;
    PORT
      LAYER M4 ;
        RECT  0 39.264 0.192 39.288 ;
    END
  END i[351]
  PIN i[352]
    DIRECTION INPUT ;
    USE SIGNAL ;
    PORT
      LAYER M4 ;
        RECT  0 39.36 0.192 39.384 ;
    END
  END i[352]
  PIN i[353]
    DIRECTION INPUT ;
    USE SIGNAL ;
    PORT
      LAYER M4 ;
        RECT  0 39.456 0.192 39.48 ;
    END
  END i[353]
  PIN i[354]
    DIRECTION INPUT ;
    USE SIGNAL ;
    PORT
      LAYER M4 ;
        RECT  0 39.552 0.192 39.576 ;
    END
  END i[354]
  PIN i[355]
    DIRECTION INPUT ;
    USE SIGNAL ;
    PORT
      LAYER M4 ;
        RECT  0 39.648 0.192 39.672 ;
    END
  END i[355]
  PIN i[356]
    DIRECTION INPUT ;
    USE SIGNAL ;
    PORT
      LAYER M4 ;
        RECT  0 39.792 0.192 39.816 ;
    END
  END i[356]
  PIN i[357]
    DIRECTION INPUT ;
    USE SIGNAL ;
    PORT
      LAYER M4 ;
        RECT  0 39.888 0.192 39.912 ;
    END
  END i[357]
  PIN i[358]
    DIRECTION INPUT ;
    USE SIGNAL ;
    PORT
      LAYER M4 ;
        RECT  0 39.984 0.192 40.008 ;
    END
  END i[358]
  PIN i[359]
    DIRECTION INPUT ;
    USE SIGNAL ;
    PORT
      LAYER M4 ;
        RECT  0 40.08 0.192 40.104 ;
    END
  END i[359]
  PIN i[35]
    DIRECTION INPUT ;
    USE SIGNAL ;
    PORT
      LAYER M4 ;
        RECT  0 5.904 0.192 5.928 ;
    END
  END i[35]
  PIN i[360]
    DIRECTION INPUT ;
    USE SIGNAL ;
    PORT
      LAYER M4 ;
        RECT  0 40.176 0.192 40.2 ;
    END
  END i[360]
  PIN i[361]
    DIRECTION INPUT ;
    USE SIGNAL ;
    PORT
      LAYER M4 ;
        RECT  0 40.32 0.192 40.344 ;
    END
  END i[361]
  PIN i[362]
    DIRECTION INPUT ;
    USE SIGNAL ;
    PORT
      LAYER M4 ;
        RECT  0 40.416 0.192 40.44 ;
    END
  END i[362]
  PIN i[363]
    DIRECTION INPUT ;
    USE SIGNAL ;
    PORT
      LAYER M4 ;
        RECT  0 40.512 0.192 40.536 ;
    END
  END i[363]
  PIN i[364]
    DIRECTION INPUT ;
    USE SIGNAL ;
    PORT
      LAYER M4 ;
        RECT  0 40.608 0.192 40.632 ;
    END
  END i[364]
  PIN i[365]
    DIRECTION INPUT ;
    USE SIGNAL ;
    PORT
      LAYER M4 ;
        RECT  0 40.704 0.192 40.728 ;
    END
  END i[365]
  PIN i[366]
    DIRECTION INPUT ;
    USE SIGNAL ;
    PORT
      LAYER M4 ;
        RECT  0 40.848 0.192 40.872 ;
    END
  END i[366]
  PIN i[367]
    DIRECTION INPUT ;
    USE SIGNAL ;
    PORT
      LAYER M4 ;
        RECT  0 40.944 0.192 40.968 ;
    END
  END i[367]
  PIN i[368]
    DIRECTION INPUT ;
    USE SIGNAL ;
    PORT
      LAYER M4 ;
        RECT  0 41.04 0.192 41.064 ;
    END
  END i[368]
  PIN i[369]
    DIRECTION INPUT ;
    USE SIGNAL ;
    PORT
      LAYER M4 ;
        RECT  0 41.136 0.192 41.16 ;
    END
  END i[369]
  PIN i[36]
    DIRECTION INPUT ;
    USE SIGNAL ;
    PORT
      LAYER M4 ;
        RECT  0 6 0.192 6.024 ;
    END
  END i[36]
  PIN i[370]
    DIRECTION INPUT ;
    USE SIGNAL ;
    PORT
      LAYER M4 ;
        RECT  0 41.232 0.192 41.256 ;
    END
  END i[370]
  PIN i[371]
    DIRECTION INPUT ;
    USE SIGNAL ;
    PORT
      LAYER M4 ;
        RECT  0 41.376 0.192 41.4 ;
    END
  END i[371]
  PIN i[372]
    DIRECTION INPUT ;
    USE SIGNAL ;
    PORT
      LAYER M4 ;
        RECT  0 41.472 0.192 41.496 ;
    END
  END i[372]
  PIN i[373]
    DIRECTION INPUT ;
    USE SIGNAL ;
    PORT
      LAYER M4 ;
        RECT  0 41.568 0.192 41.592 ;
    END
  END i[373]
  PIN i[374]
    DIRECTION INPUT ;
    USE SIGNAL ;
    PORT
      LAYER M4 ;
        RECT  0 41.664 0.192 41.688 ;
    END
  END i[374]
  PIN i[375]
    DIRECTION INPUT ;
    USE SIGNAL ;
    PORT
      LAYER M4 ;
        RECT  0 41.76 0.192 41.784 ;
    END
  END i[375]
  PIN i[376]
    DIRECTION INPUT ;
    USE SIGNAL ;
    PORT
      LAYER M4 ;
        RECT  0 41.904 0.192 41.928 ;
    END
  END i[376]
  PIN i[377]
    DIRECTION INPUT ;
    USE SIGNAL ;
    PORT
      LAYER M4 ;
        RECT  0 42 0.192 42.024 ;
    END
  END i[377]
  PIN i[378]
    DIRECTION INPUT ;
    USE SIGNAL ;
    PORT
      LAYER M4 ;
        RECT  0 42.096 0.192 42.12 ;
    END
  END i[378]
  PIN i[379]
    DIRECTION INPUT ;
    USE SIGNAL ;
    PORT
      LAYER M4 ;
        RECT  0 42.192 0.192 42.216 ;
    END
  END i[379]
  PIN i[37]
    DIRECTION INPUT ;
    USE SIGNAL ;
    PORT
      LAYER M4 ;
        RECT  0 6.144 0.192 6.168 ;
    END
  END i[37]
  PIN i[380]
    DIRECTION INPUT ;
    USE SIGNAL ;
    PORT
      LAYER M4 ;
        RECT  0 42.288 0.192 42.312 ;
    END
  END i[380]
  PIN i[381]
    DIRECTION INPUT ;
    USE SIGNAL ;
    PORT
      LAYER M4 ;
        RECT  0 42.432 0.192 42.456 ;
    END
  END i[381]
  PIN i[382]
    DIRECTION INPUT ;
    USE SIGNAL ;
    PORT
      LAYER M4 ;
        RECT  0 42.528 0.192 42.552 ;
    END
  END i[382]
  PIN i[383]
    DIRECTION INPUT ;
    USE SIGNAL ;
    PORT
      LAYER M4 ;
        RECT  0 42.624 0.192 42.648 ;
    END
  END i[383]
  PIN i[384]
    DIRECTION INPUT ;
    USE SIGNAL ;
    PORT
      LAYER M4 ;
        RECT  0 42.72 0.192 42.744 ;
    END
  END i[384]
  PIN i[385]
    DIRECTION INPUT ;
    USE SIGNAL ;
    PORT
      LAYER M4 ;
        RECT  0 42.816 0.192 42.84 ;
    END
  END i[385]
  PIN i[386]
    DIRECTION INPUT ;
    USE SIGNAL ;
    PORT
      LAYER M4 ;
        RECT  0 42.912 0.192 42.936 ;
    END
  END i[386]
  PIN i[387]
    DIRECTION INPUT ;
    USE SIGNAL ;
    PORT
      LAYER M4 ;
        RECT  0 43.056 0.192 43.08 ;
    END
  END i[387]
  PIN i[388]
    DIRECTION INPUT ;
    USE SIGNAL ;
    PORT
      LAYER M4 ;
        RECT  0 43.152 0.192 43.176 ;
    END
  END i[388]
  PIN i[389]
    DIRECTION INPUT ;
    USE SIGNAL ;
    PORT
      LAYER M4 ;
        RECT  0 43.248 0.192 43.272 ;
    END
  END i[389]
  PIN i[38]
    DIRECTION INPUT ;
    USE SIGNAL ;
    PORT
      LAYER M4 ;
        RECT  0 6.24 0.192 6.264 ;
    END
  END i[38]
  PIN i[390]
    DIRECTION INPUT ;
    USE SIGNAL ;
    PORT
      LAYER M4 ;
        RECT  0 43.344 0.192 43.368 ;
    END
  END i[390]
  PIN i[391]
    DIRECTION INPUT ;
    USE SIGNAL ;
    PORT
      LAYER M4 ;
        RECT  0 43.44 0.192 43.464 ;
    END
  END i[391]
  PIN i[392]
    DIRECTION INPUT ;
    USE SIGNAL ;
    PORT
      LAYER M4 ;
        RECT  0 43.584 0.192 43.608 ;
    END
  END i[392]
  PIN i[393]
    DIRECTION INPUT ;
    USE SIGNAL ;
    PORT
      LAYER M4 ;
        RECT  0 43.68 0.192 43.704 ;
    END
  END i[393]
  PIN i[394]
    DIRECTION INPUT ;
    USE SIGNAL ;
    PORT
      LAYER M4 ;
        RECT  0 43.776 0.192 43.8 ;
    END
  END i[394]
  PIN i[395]
    DIRECTION INPUT ;
    USE SIGNAL ;
    PORT
      LAYER M4 ;
        RECT  0 43.872 0.192 43.896 ;
    END
  END i[395]
  PIN i[396]
    DIRECTION INPUT ;
    USE SIGNAL ;
    PORT
      LAYER M4 ;
        RECT  0 43.968 0.192 43.992 ;
    END
  END i[396]
  PIN i[397]
    DIRECTION INPUT ;
    USE SIGNAL ;
    PORT
      LAYER M4 ;
        RECT  0 44.112 0.192 44.136 ;
    END
  END i[397]
  PIN i[398]
    DIRECTION INPUT ;
    USE SIGNAL ;
    PORT
      LAYER M4 ;
        RECT  0 44.208 0.192 44.232 ;
    END
  END i[398]
  PIN i[399]
    DIRECTION INPUT ;
    USE SIGNAL ;
    PORT
      LAYER M4 ;
        RECT  0 44.304 0.192 44.328 ;
    END
  END i[399]
  PIN i[39]
    DIRECTION INPUT ;
    USE SIGNAL ;
    PORT
      LAYER M4 ;
        RECT  0 6.336 0.192 6.36 ;
    END
  END i[39]
  PIN i[3]
    DIRECTION INPUT ;
    USE SIGNAL ;
    PORT
      LAYER M4 ;
        RECT  0 2.544 0.192 2.568 ;
    END
  END i[3]
  PIN i[400]
    DIRECTION INPUT ;
    USE SIGNAL ;
    PORT
      LAYER M4 ;
        RECT  0 44.4 0.192 44.424 ;
    END
  END i[400]
  PIN i[401]
    DIRECTION INPUT ;
    USE SIGNAL ;
    PORT
      LAYER M4 ;
        RECT  0 44.496 0.192 44.52 ;
    END
  END i[401]
  PIN i[402]
    DIRECTION INPUT ;
    USE SIGNAL ;
    PORT
      LAYER M4 ;
        RECT  0 44.64 0.192 44.664 ;
    END
  END i[402]
  PIN i[403]
    DIRECTION INPUT ;
    USE SIGNAL ;
    PORT
      LAYER M4 ;
        RECT  0 44.736 0.192 44.76 ;
    END
  END i[403]
  PIN i[404]
    DIRECTION INPUT ;
    USE SIGNAL ;
    PORT
      LAYER M4 ;
        RECT  0 44.832 0.192 44.856 ;
    END
  END i[404]
  PIN i[405]
    DIRECTION INPUT ;
    USE SIGNAL ;
    PORT
      LAYER M4 ;
        RECT  0 44.928 0.192 44.952 ;
    END
  END i[405]
  PIN i[406]
    DIRECTION INPUT ;
    USE SIGNAL ;
    PORT
      LAYER M4 ;
        RECT  0 45.024 0.192 45.048 ;
    END
  END i[406]
  PIN i[407]
    DIRECTION INPUT ;
    USE SIGNAL ;
    PORT
      LAYER M4 ;
        RECT  0 45.168 0.192 45.192 ;
    END
  END i[407]
  PIN i[408]
    DIRECTION INPUT ;
    USE SIGNAL ;
    PORT
      LAYER M4 ;
        RECT  0 45.264 0.192 45.288 ;
    END
  END i[408]
  PIN i[409]
    DIRECTION INPUT ;
    USE SIGNAL ;
    PORT
      LAYER M4 ;
        RECT  0 45.36 0.192 45.384 ;
    END
  END i[409]
  PIN i[40]
    DIRECTION INPUT ;
    USE SIGNAL ;
    PORT
      LAYER M4 ;
        RECT  0 6.432 0.192 6.456 ;
    END
  END i[40]
  PIN i[410]
    DIRECTION INPUT ;
    USE SIGNAL ;
    PORT
      LAYER M4 ;
        RECT  0 45.456 0.192 45.48 ;
    END
  END i[410]
  PIN i[411]
    DIRECTION INPUT ;
    USE SIGNAL ;
    PORT
      LAYER M4 ;
        RECT  0 45.552 0.192 45.576 ;
    END
  END i[411]
  PIN i[412]
    DIRECTION INPUT ;
    USE SIGNAL ;
    PORT
      LAYER M4 ;
        RECT  0 45.696 0.192 45.72 ;
    END
  END i[412]
  PIN i[413]
    DIRECTION INPUT ;
    USE SIGNAL ;
    PORT
      LAYER M4 ;
        RECT  0 45.792 0.192 45.816 ;
    END
  END i[413]
  PIN i[414]
    DIRECTION INPUT ;
    USE SIGNAL ;
    PORT
      LAYER M4 ;
        RECT  0 45.888 0.192 45.912 ;
    END
  END i[414]
  PIN i[415]
    DIRECTION INPUT ;
    USE SIGNAL ;
    PORT
      LAYER M4 ;
        RECT  0 45.984 0.192 46.008 ;
    END
  END i[415]
  PIN i[416]
    DIRECTION INPUT ;
    USE SIGNAL ;
    PORT
      LAYER M4 ;
        RECT  0 46.08 0.192 46.104 ;
    END
  END i[416]
  PIN i[417]
    DIRECTION INPUT ;
    USE SIGNAL ;
    PORT
      LAYER M4 ;
        RECT  0 46.224 0.192 46.248 ;
    END
  END i[417]
  PIN i[418]
    DIRECTION INPUT ;
    USE SIGNAL ;
    PORT
      LAYER M4 ;
        RECT  0 46.32 0.192 46.344 ;
    END
  END i[418]
  PIN i[419]
    DIRECTION INPUT ;
    USE SIGNAL ;
    PORT
      LAYER M4 ;
        RECT  0 46.416 0.192 46.44 ;
    END
  END i[419]
  PIN i[41]
    DIRECTION INPUT ;
    USE SIGNAL ;
    PORT
      LAYER M4 ;
        RECT  0 6.528 0.192 6.552 ;
    END
  END i[41]
  PIN i[420]
    DIRECTION INPUT ;
    USE SIGNAL ;
    PORT
      LAYER M4 ;
        RECT  0 46.512 0.192 46.536 ;
    END
  END i[420]
  PIN i[421]
    DIRECTION INPUT ;
    USE SIGNAL ;
    PORT
      LAYER M4 ;
        RECT  0 46.608 0.192 46.632 ;
    END
  END i[421]
  PIN i[422]
    DIRECTION INPUT ;
    USE SIGNAL ;
    PORT
      LAYER M4 ;
        RECT  0 46.752 0.192 46.776 ;
    END
  END i[422]
  PIN i[423]
    DIRECTION INPUT ;
    USE SIGNAL ;
    PORT
      LAYER M4 ;
        RECT  0 46.848 0.192 46.872 ;
    END
  END i[423]
  PIN i[424]
    DIRECTION INPUT ;
    USE SIGNAL ;
    PORT
      LAYER M4 ;
        RECT  0 46.944 0.192 46.968 ;
    END
  END i[424]
  PIN i[425]
    DIRECTION INPUT ;
    USE SIGNAL ;
    PORT
      LAYER M4 ;
        RECT  0 47.04 0.192 47.064 ;
    END
  END i[425]
  PIN i[426]
    DIRECTION INPUT ;
    USE SIGNAL ;
    PORT
      LAYER M4 ;
        RECT  0 47.136 0.192 47.16 ;
    END
  END i[426]
  PIN i[427]
    DIRECTION INPUT ;
    USE SIGNAL ;
    PORT
      LAYER M4 ;
        RECT  0 47.28 0.192 47.304 ;
    END
  END i[427]
  PIN i[428]
    DIRECTION INPUT ;
    USE SIGNAL ;
    PORT
      LAYER M4 ;
        RECT  0 47.376 0.192 47.4 ;
    END
  END i[428]
  PIN i[429]
    DIRECTION INPUT ;
    USE SIGNAL ;
    PORT
      LAYER M4 ;
        RECT  0 47.472 0.192 47.496 ;
    END
  END i[429]
  PIN i[42]
    DIRECTION INPUT ;
    USE SIGNAL ;
    PORT
      LAYER M4 ;
        RECT  0 6.672 0.192 6.696 ;
    END
  END i[42]
  PIN i[430]
    DIRECTION INPUT ;
    USE SIGNAL ;
    PORT
      LAYER M4 ;
        RECT  0 47.568 0.192 47.592 ;
    END
  END i[430]
  PIN i[431]
    DIRECTION INPUT ;
    USE SIGNAL ;
    PORT
      LAYER M4 ;
        RECT  0 47.664 0.192 47.688 ;
    END
  END i[431]
  PIN i[432]
    DIRECTION INPUT ;
    USE SIGNAL ;
    PORT
      LAYER M4 ;
        RECT  0 47.808 0.192 47.832 ;
    END
  END i[432]
  PIN i[433]
    DIRECTION INPUT ;
    USE SIGNAL ;
    PORT
      LAYER M4 ;
        RECT  0 47.904 0.192 47.928 ;
    END
  END i[433]
  PIN i[434]
    DIRECTION INPUT ;
    USE SIGNAL ;
    PORT
      LAYER M4 ;
        RECT  0 48 0.192 48.024 ;
    END
  END i[434]
  PIN i[435]
    DIRECTION INPUT ;
    USE SIGNAL ;
    PORT
      LAYER M4 ;
        RECT  0 48.096 0.192 48.12 ;
    END
  END i[435]
  PIN i[436]
    DIRECTION INPUT ;
    USE SIGNAL ;
    PORT
      LAYER M4 ;
        RECT  0 48.192 0.192 48.216 ;
    END
  END i[436]
  PIN i[437]
    DIRECTION INPUT ;
    USE SIGNAL ;
    PORT
      LAYER M4 ;
        RECT  0 48.336 0.192 48.36 ;
    END
  END i[437]
  PIN i[438]
    DIRECTION INPUT ;
    USE SIGNAL ;
    PORT
      LAYER M4 ;
        RECT  0 48.432 0.192 48.456 ;
    END
  END i[438]
  PIN i[439]
    DIRECTION INPUT ;
    USE SIGNAL ;
    PORT
      LAYER M4 ;
        RECT  0 48.528 0.192 48.552 ;
    END
  END i[439]
  PIN i[43]
    DIRECTION INPUT ;
    USE SIGNAL ;
    PORT
      LAYER M4 ;
        RECT  0 6.768 0.192 6.792 ;
    END
  END i[43]
  PIN i[440]
    DIRECTION INPUT ;
    USE SIGNAL ;
    PORT
      LAYER M4 ;
        RECT  0 48.624 0.192 48.648 ;
    END
  END i[440]
  PIN i[441]
    DIRECTION INPUT ;
    USE SIGNAL ;
    PORT
      LAYER M4 ;
        RECT  0 48.72 0.192 48.744 ;
    END
  END i[441]
  PIN i[442]
    DIRECTION INPUT ;
    USE SIGNAL ;
    PORT
      LAYER M4 ;
        RECT  0 48.864 0.192 48.888 ;
    END
  END i[442]
  PIN i[443]
    DIRECTION INPUT ;
    USE SIGNAL ;
    PORT
      LAYER M4 ;
        RECT  0 48.96 0.192 48.984 ;
    END
  END i[443]
  PIN i[444]
    DIRECTION INPUT ;
    USE SIGNAL ;
    PORT
      LAYER M4 ;
        RECT  0 49.056 0.192 49.08 ;
    END
  END i[444]
  PIN i[445]
    DIRECTION INPUT ;
    USE SIGNAL ;
    PORT
      LAYER M4 ;
        RECT  0 49.152 0.192 49.176 ;
    END
  END i[445]
  PIN i[446]
    DIRECTION INPUT ;
    USE SIGNAL ;
    PORT
      LAYER M4 ;
        RECT  0 49.248 0.192 49.272 ;
    END
  END i[446]
  PIN i[447]
    DIRECTION INPUT ;
    USE SIGNAL ;
    PORT
      LAYER M4 ;
        RECT  0 49.392 0.192 49.416 ;
    END
  END i[447]
  PIN i[448]
    DIRECTION INPUT ;
    USE SIGNAL ;
    PORT
      LAYER M4 ;
        RECT  0 49.488 0.192 49.512 ;
    END
  END i[448]
  PIN i[449]
    DIRECTION INPUT ;
    USE SIGNAL ;
    PORT
      LAYER M4 ;
        RECT  0 49.584 0.192 49.608 ;
    END
  END i[449]
  PIN i[44]
    DIRECTION INPUT ;
    USE SIGNAL ;
    PORT
      LAYER M4 ;
        RECT  0 6.864 0.192 6.888 ;
    END
  END i[44]
  PIN i[450]
    DIRECTION INPUT ;
    USE SIGNAL ;
    PORT
      LAYER M4 ;
        RECT  0 49.68 0.192 49.704 ;
    END
  END i[450]
  PIN i[451]
    DIRECTION INPUT ;
    USE SIGNAL ;
    PORT
      LAYER M4 ;
        RECT  0 49.776 0.192 49.8 ;
    END
  END i[451]
  PIN i[452]
    DIRECTION INPUT ;
    USE SIGNAL ;
    PORT
      LAYER M4 ;
        RECT  0 49.92 0.192 49.944 ;
    END
  END i[452]
  PIN i[453]
    DIRECTION INPUT ;
    USE SIGNAL ;
    PORT
      LAYER M4 ;
        RECT  0 50.016 0.192 50.04 ;
    END
  END i[453]
  PIN i[454]
    DIRECTION INPUT ;
    USE SIGNAL ;
    PORT
      LAYER M4 ;
        RECT  0 50.112 0.192 50.136 ;
    END
  END i[454]
  PIN i[455]
    DIRECTION INPUT ;
    USE SIGNAL ;
    PORT
      LAYER M4 ;
        RECT  0 50.208 0.192 50.232 ;
    END
  END i[455]
  PIN i[456]
    DIRECTION INPUT ;
    USE SIGNAL ;
    PORT
      LAYER M4 ;
        RECT  0 50.304 0.192 50.328 ;
    END
  END i[456]
  PIN i[457]
    DIRECTION INPUT ;
    USE SIGNAL ;
    PORT
      LAYER M4 ;
        RECT  0 50.4 0.192 50.424 ;
    END
  END i[457]
  PIN i[458]
    DIRECTION INPUT ;
    USE SIGNAL ;
    PORT
      LAYER M4 ;
        RECT  0 50.544 0.192 50.568 ;
    END
  END i[458]
  PIN i[459]
    DIRECTION INPUT ;
    USE SIGNAL ;
    PORT
      LAYER M4 ;
        RECT  0 50.64 0.192 50.664 ;
    END
  END i[459]
  PIN i[45]
    DIRECTION INPUT ;
    USE SIGNAL ;
    PORT
      LAYER M4 ;
        RECT  0 6.96 0.192 6.984 ;
    END
  END i[45]
  PIN i[460]
    DIRECTION INPUT ;
    USE SIGNAL ;
    PORT
      LAYER M4 ;
        RECT  0 50.736 0.192 50.76 ;
    END
  END i[460]
  PIN i[461]
    DIRECTION INPUT ;
    USE SIGNAL ;
    PORT
      LAYER M4 ;
        RECT  0 50.832 0.192 50.856 ;
    END
  END i[461]
  PIN i[462]
    DIRECTION INPUT ;
    USE SIGNAL ;
    PORT
      LAYER M4 ;
        RECT  0 50.928 0.192 50.952 ;
    END
  END i[462]
  PIN i[463]
    DIRECTION INPUT ;
    USE SIGNAL ;
    PORT
      LAYER M4 ;
        RECT  0 51.072 0.192 51.096 ;
    END
  END i[463]
  PIN i[464]
    DIRECTION INPUT ;
    USE SIGNAL ;
    PORT
      LAYER M4 ;
        RECT  0 51.168 0.192 51.192 ;
    END
  END i[464]
  PIN i[465]
    DIRECTION INPUT ;
    USE SIGNAL ;
    PORT
      LAYER M4 ;
        RECT  0 51.264 0.192 51.288 ;
    END
  END i[465]
  PIN i[466]
    DIRECTION INPUT ;
    USE SIGNAL ;
    PORT
      LAYER M4 ;
        RECT  0 51.36 0.192 51.384 ;
    END
  END i[466]
  PIN i[467]
    DIRECTION INPUT ;
    USE SIGNAL ;
    PORT
      LAYER M4 ;
        RECT  0 51.456 0.192 51.48 ;
    END
  END i[467]
  PIN i[468]
    DIRECTION INPUT ;
    USE SIGNAL ;
    PORT
      LAYER M4 ;
        RECT  0 51.6 0.192 51.624 ;
    END
  END i[468]
  PIN i[469]
    DIRECTION INPUT ;
    USE SIGNAL ;
    PORT
      LAYER M4 ;
        RECT  0 51.696 0.192 51.72 ;
    END
  END i[469]
  PIN i[46]
    DIRECTION INPUT ;
    USE SIGNAL ;
    PORT
      LAYER M4 ;
        RECT  0 7.056 0.192 7.08 ;
    END
  END i[46]
  PIN i[470]
    DIRECTION INPUT ;
    USE SIGNAL ;
    PORT
      LAYER M4 ;
        RECT  0 51.792 0.192 51.816 ;
    END
  END i[470]
  PIN i[471]
    DIRECTION INPUT ;
    USE SIGNAL ;
    PORT
      LAYER M4 ;
        RECT  0 51.888 0.192 51.912 ;
    END
  END i[471]
  PIN i[472]
    DIRECTION INPUT ;
    USE SIGNAL ;
    PORT
      LAYER M4 ;
        RECT  0 51.984 0.192 52.008 ;
    END
  END i[472]
  PIN i[473]
    DIRECTION INPUT ;
    USE SIGNAL ;
    PORT
      LAYER M4 ;
        RECT  0 52.128 0.192 52.152 ;
    END
  END i[473]
  PIN i[474]
    DIRECTION INPUT ;
    USE SIGNAL ;
    PORT
      LAYER M4 ;
        RECT  0 52.224 0.192 52.248 ;
    END
  END i[474]
  PIN i[475]
    DIRECTION INPUT ;
    USE SIGNAL ;
    PORT
      LAYER M4 ;
        RECT  0 52.32 0.192 52.344 ;
    END
  END i[475]
  PIN i[476]
    DIRECTION INPUT ;
    USE SIGNAL ;
    PORT
      LAYER M4 ;
        RECT  0 52.416 0.192 52.44 ;
    END
  END i[476]
  PIN i[477]
    DIRECTION INPUT ;
    USE SIGNAL ;
    PORT
      LAYER M4 ;
        RECT  0 52.512 0.192 52.536 ;
    END
  END i[477]
  PIN i[478]
    DIRECTION INPUT ;
    USE SIGNAL ;
    PORT
      LAYER M4 ;
        RECT  0 52.656 0.192 52.68 ;
    END
  END i[478]
  PIN i[479]
    DIRECTION INPUT ;
    USE SIGNAL ;
    PORT
      LAYER M4 ;
        RECT  0 52.752 0.192 52.776 ;
    END
  END i[479]
  PIN i[47]
    DIRECTION INPUT ;
    USE SIGNAL ;
    PORT
      LAYER M4 ;
        RECT  0 7.2 0.192 7.224 ;
    END
  END i[47]
  PIN i[480]
    DIRECTION INPUT ;
    USE SIGNAL ;
    PORT
      LAYER M4 ;
        RECT  0 52.848 0.192 52.872 ;
    END
  END i[480]
  PIN i[481]
    DIRECTION INPUT ;
    USE SIGNAL ;
    PORT
      LAYER M4 ;
        RECT  0 52.944 0.192 52.968 ;
    END
  END i[481]
  PIN i[482]
    DIRECTION INPUT ;
    USE SIGNAL ;
    PORT
      LAYER M4 ;
        RECT  0 53.04 0.192 53.064 ;
    END
  END i[482]
  PIN i[483]
    DIRECTION INPUT ;
    USE SIGNAL ;
    PORT
      LAYER M4 ;
        RECT  0 53.184 0.192 53.208 ;
    END
  END i[483]
  PIN i[484]
    DIRECTION INPUT ;
    USE SIGNAL ;
    PORT
      LAYER M4 ;
        RECT  0 53.28 0.192 53.304 ;
    END
  END i[484]
  PIN i[485]
    DIRECTION INPUT ;
    USE SIGNAL ;
    PORT
      LAYER M4 ;
        RECT  0 53.376 0.192 53.4 ;
    END
  END i[485]
  PIN i[486]
    DIRECTION INPUT ;
    USE SIGNAL ;
    PORT
      LAYER M4 ;
        RECT  0 53.472 0.192 53.496 ;
    END
  END i[486]
  PIN i[487]
    DIRECTION INPUT ;
    USE SIGNAL ;
    PORT
      LAYER M4 ;
        RECT  0 53.568 0.192 53.592 ;
    END
  END i[487]
  PIN i[488]
    DIRECTION INPUT ;
    USE SIGNAL ;
    PORT
      LAYER M4 ;
        RECT  0 53.712 0.192 53.736 ;
    END
  END i[488]
  PIN i[489]
    DIRECTION INPUT ;
    USE SIGNAL ;
    PORT
      LAYER M4 ;
        RECT  0 53.808 0.192 53.832 ;
    END
  END i[489]
  PIN i[48]
    DIRECTION INPUT ;
    USE SIGNAL ;
    PORT
      LAYER M4 ;
        RECT  0 7.296 0.192 7.32 ;
    END
  END i[48]
  PIN i[490]
    DIRECTION INPUT ;
    USE SIGNAL ;
    PORT
      LAYER M4 ;
        RECT  0 53.904 0.192 53.928 ;
    END
  END i[490]
  PIN i[491]
    DIRECTION INPUT ;
    USE SIGNAL ;
    PORT
      LAYER M4 ;
        RECT  0 54 0.192 54.024 ;
    END
  END i[491]
  PIN i[492]
    DIRECTION INPUT ;
    USE SIGNAL ;
    PORT
      LAYER M4 ;
        RECT  0 54.096 0.192 54.12 ;
    END
  END i[492]
  PIN i[493]
    DIRECTION INPUT ;
    USE SIGNAL ;
    PORT
      LAYER M4 ;
        RECT  0 54.24 0.192 54.264 ;
    END
  END i[493]
  PIN i[494]
    DIRECTION INPUT ;
    USE SIGNAL ;
    PORT
      LAYER M4 ;
        RECT  0 54.336 0.192 54.36 ;
    END
  END i[494]
  PIN i[495]
    DIRECTION INPUT ;
    USE SIGNAL ;
    PORT
      LAYER M4 ;
        RECT  0 54.432 0.192 54.456 ;
    END
  END i[495]
  PIN i[496]
    DIRECTION INPUT ;
    USE SIGNAL ;
    PORT
      LAYER M4 ;
        RECT  0 54.528 0.192 54.552 ;
    END
  END i[496]
  PIN i[497]
    DIRECTION INPUT ;
    USE SIGNAL ;
    PORT
      LAYER M4 ;
        RECT  0 54.624 0.192 54.648 ;
    END
  END i[497]
  PIN i[498]
    DIRECTION INPUT ;
    USE SIGNAL ;
    PORT
      LAYER M4 ;
        RECT  0 54.768 0.192 54.792 ;
    END
  END i[498]
  PIN i[499]
    DIRECTION INPUT ;
    USE SIGNAL ;
    PORT
      LAYER M4 ;
        RECT  0 54.864 0.192 54.888 ;
    END
  END i[499]
  PIN i[49]
    DIRECTION INPUT ;
    USE SIGNAL ;
    PORT
      LAYER M4 ;
        RECT  0 7.392 0.192 7.416 ;
    END
  END i[49]
  PIN i[4]
    DIRECTION INPUT ;
    USE SIGNAL ;
    PORT
      LAYER M4 ;
        RECT  0 2.64 0.192 2.664 ;
    END
  END i[4]
  PIN i[500]
    DIRECTION INPUT ;
    USE SIGNAL ;
    PORT
      LAYER M4 ;
        RECT  0 54.96 0.192 54.984 ;
    END
  END i[500]
  PIN i[501]
    DIRECTION INPUT ;
    USE SIGNAL ;
    PORT
      LAYER M4 ;
        RECT  0 55.056 0.192 55.08 ;
    END
  END i[501]
  PIN i[502]
    DIRECTION INPUT ;
    USE SIGNAL ;
    PORT
      LAYER M4 ;
        RECT  0 55.152 0.192 55.176 ;
    END
  END i[502]
  PIN i[503]
    DIRECTION INPUT ;
    USE SIGNAL ;
    PORT
      LAYER M4 ;
        RECT  0 55.296 0.192 55.32 ;
    END
  END i[503]
  PIN i[504]
    DIRECTION INPUT ;
    USE SIGNAL ;
    PORT
      LAYER M4 ;
        RECT  0 55.392 0.192 55.416 ;
    END
  END i[504]
  PIN i[505]
    DIRECTION INPUT ;
    USE SIGNAL ;
    PORT
      LAYER M4 ;
        RECT  0 55.488 0.192 55.512 ;
    END
  END i[505]
  PIN i[506]
    DIRECTION INPUT ;
    USE SIGNAL ;
    PORT
      LAYER M4 ;
        RECT  0 55.584 0.192 55.608 ;
    END
  END i[506]
  PIN i[507]
    DIRECTION INPUT ;
    USE SIGNAL ;
    PORT
      LAYER M4 ;
        RECT  0 55.68 0.192 55.704 ;
    END
  END i[507]
  PIN i[508]
    DIRECTION INPUT ;
    USE SIGNAL ;
    PORT
      LAYER M4 ;
        RECT  0 55.824 0.192 55.848 ;
    END
  END i[508]
  PIN i[509]
    DIRECTION INPUT ;
    USE SIGNAL ;
    PORT
      LAYER M4 ;
        RECT  0 55.92 0.192 55.944 ;
    END
  END i[509]
  PIN i[50]
    DIRECTION INPUT ;
    USE SIGNAL ;
    PORT
      LAYER M4 ;
        RECT  0 7.488 0.192 7.512 ;
    END
  END i[50]
  PIN i[510]
    DIRECTION INPUT ;
    USE SIGNAL ;
    PORT
      LAYER M4 ;
        RECT  0 56.016 0.192 56.04 ;
    END
  END i[510]
  PIN i[511]
    DIRECTION INPUT ;
    USE SIGNAL ;
    PORT
      LAYER M4 ;
        RECT  0 56.112 0.192 56.136 ;
    END
  END i[511]
  PIN i[51]
    DIRECTION INPUT ;
    USE SIGNAL ;
    PORT
      LAYER M4 ;
        RECT  0 7.584 0.192 7.608 ;
    END
  END i[51]
  PIN i[52]
    DIRECTION INPUT ;
    USE SIGNAL ;
    PORT
      LAYER M4 ;
        RECT  0 7.728 0.192 7.752 ;
    END
  END i[52]
  PIN i[53]
    DIRECTION INPUT ;
    USE SIGNAL ;
    PORT
      LAYER M4 ;
        RECT  0 7.824 0.192 7.848 ;
    END
  END i[53]
  PIN i[54]
    DIRECTION INPUT ;
    USE SIGNAL ;
    PORT
      LAYER M4 ;
        RECT  0 7.92 0.192 7.944 ;
    END
  END i[54]
  PIN i[55]
    DIRECTION INPUT ;
    USE SIGNAL ;
    PORT
      LAYER M4 ;
        RECT  0 8.016 0.192 8.04 ;
    END
  END i[55]
  PIN i[56]
    DIRECTION INPUT ;
    USE SIGNAL ;
    PORT
      LAYER M4 ;
        RECT  0 8.112 0.192 8.136 ;
    END
  END i[56]
  PIN i[57]
    DIRECTION INPUT ;
    USE SIGNAL ;
    PORT
      LAYER M4 ;
        RECT  0 8.256 0.192 8.28 ;
    END
  END i[57]
  PIN i[58]
    DIRECTION INPUT ;
    USE SIGNAL ;
    PORT
      LAYER M4 ;
        RECT  0 8.352 0.192 8.376 ;
    END
  END i[58]
  PIN i[59]
    DIRECTION INPUT ;
    USE SIGNAL ;
    PORT
      LAYER M4 ;
        RECT  0 8.448 0.192 8.472 ;
    END
  END i[59]
  PIN i[5]
    DIRECTION INPUT ;
    USE SIGNAL ;
    PORT
      LAYER M4 ;
        RECT  0 2.736 0.192 2.76 ;
    END
  END i[5]
  PIN i[60]
    DIRECTION INPUT ;
    USE SIGNAL ;
    PORT
      LAYER M4 ;
        RECT  0 8.544 0.192 8.568 ;
    END
  END i[60]
  PIN i[61]
    DIRECTION INPUT ;
    USE SIGNAL ;
    PORT
      LAYER M4 ;
        RECT  0 8.64 0.192 8.664 ;
    END
  END i[61]
  PIN i[62]
    DIRECTION INPUT ;
    USE SIGNAL ;
    PORT
      LAYER M4 ;
        RECT  0 8.784 0.192 8.808 ;
    END
  END i[62]
  PIN i[63]
    DIRECTION INPUT ;
    USE SIGNAL ;
    PORT
      LAYER M4 ;
        RECT  0 8.88 0.192 8.904 ;
    END
  END i[63]
  PIN i[64]
    DIRECTION INPUT ;
    USE SIGNAL ;
    PORT
      LAYER M4 ;
        RECT  0 8.976 0.192 9 ;
    END
  END i[64]
  PIN i[65]
    DIRECTION INPUT ;
    USE SIGNAL ;
    PORT
      LAYER M4 ;
        RECT  0 9.072 0.192 9.096 ;
    END
  END i[65]
  PIN i[66]
    DIRECTION INPUT ;
    USE SIGNAL ;
    PORT
      LAYER M4 ;
        RECT  0 9.168 0.192 9.192 ;
    END
  END i[66]
  PIN i[67]
    DIRECTION INPUT ;
    USE SIGNAL ;
    PORT
      LAYER M4 ;
        RECT  0 9.312 0.192 9.336 ;
    END
  END i[67]
  PIN i[68]
    DIRECTION INPUT ;
    USE SIGNAL ;
    PORT
      LAYER M4 ;
        RECT  0 9.408 0.192 9.432 ;
    END
  END i[68]
  PIN i[69]
    DIRECTION INPUT ;
    USE SIGNAL ;
    PORT
      LAYER M4 ;
        RECT  0 9.504 0.192 9.528 ;
    END
  END i[69]
  PIN i[6]
    DIRECTION INPUT ;
    USE SIGNAL ;
    PORT
      LAYER M4 ;
        RECT  0 2.88 0.192 2.904 ;
    END
  END i[6]
  PIN i[70]
    DIRECTION INPUT ;
    USE SIGNAL ;
    PORT
      LAYER M4 ;
        RECT  0 9.6 0.192 9.624 ;
    END
  END i[70]
  PIN i[71]
    DIRECTION INPUT ;
    USE SIGNAL ;
    PORT
      LAYER M4 ;
        RECT  0 9.696 0.192 9.72 ;
    END
  END i[71]
  PIN i[72]
    DIRECTION INPUT ;
    USE SIGNAL ;
    PORT
      LAYER M4 ;
        RECT  0 9.84 0.192 9.864 ;
    END
  END i[72]
  PIN i[73]
    DIRECTION INPUT ;
    USE SIGNAL ;
    PORT
      LAYER M4 ;
        RECT  0 9.936 0.192 9.96 ;
    END
  END i[73]
  PIN i[74]
    DIRECTION INPUT ;
    USE SIGNAL ;
    PORT
      LAYER M4 ;
        RECT  0 10.032 0.192 10.056 ;
    END
  END i[74]
  PIN i[75]
    DIRECTION INPUT ;
    USE SIGNAL ;
    PORT
      LAYER M4 ;
        RECT  0 10.128 0.192 10.152 ;
    END
  END i[75]
  PIN i[76]
    DIRECTION INPUT ;
    USE SIGNAL ;
    PORT
      LAYER M4 ;
        RECT  0 10.224 0.192 10.248 ;
    END
  END i[76]
  PIN i[77]
    DIRECTION INPUT ;
    USE SIGNAL ;
    PORT
      LAYER M4 ;
        RECT  0 10.368 0.192 10.392 ;
    END
  END i[77]
  PIN i[78]
    DIRECTION INPUT ;
    USE SIGNAL ;
    PORT
      LAYER M4 ;
        RECT  0 10.464 0.192 10.488 ;
    END
  END i[78]
  PIN i[79]
    DIRECTION INPUT ;
    USE SIGNAL ;
    PORT
      LAYER M4 ;
        RECT  0 10.56 0.192 10.584 ;
    END
  END i[79]
  PIN i[7]
    DIRECTION INPUT ;
    USE SIGNAL ;
    PORT
      LAYER M4 ;
        RECT  0 2.976 0.192 3 ;
    END
  END i[7]
  PIN i[80]
    DIRECTION INPUT ;
    USE SIGNAL ;
    PORT
      LAYER M4 ;
        RECT  0 10.656 0.192 10.68 ;
    END
  END i[80]
  PIN i[81]
    DIRECTION INPUT ;
    USE SIGNAL ;
    PORT
      LAYER M4 ;
        RECT  0 10.752 0.192 10.776 ;
    END
  END i[81]
  PIN i[82]
    DIRECTION INPUT ;
    USE SIGNAL ;
    PORT
      LAYER M4 ;
        RECT  0 10.896 0.192 10.92 ;
    END
  END i[82]
  PIN i[83]
    DIRECTION INPUT ;
    USE SIGNAL ;
    PORT
      LAYER M4 ;
        RECT  0 10.992 0.192 11.016 ;
    END
  END i[83]
  PIN i[84]
    DIRECTION INPUT ;
    USE SIGNAL ;
    PORT
      LAYER M4 ;
        RECT  0 11.088 0.192 11.112 ;
    END
  END i[84]
  PIN i[85]
    DIRECTION INPUT ;
    USE SIGNAL ;
    PORT
      LAYER M4 ;
        RECT  0 11.184 0.192 11.208 ;
    END
  END i[85]
  PIN i[86]
    DIRECTION INPUT ;
    USE SIGNAL ;
    PORT
      LAYER M4 ;
        RECT  0 11.28 0.192 11.304 ;
    END
  END i[86]
  PIN i[87]
    DIRECTION INPUT ;
    USE SIGNAL ;
    PORT
      LAYER M4 ;
        RECT  0 11.424 0.192 11.448 ;
    END
  END i[87]
  PIN i[88]
    DIRECTION INPUT ;
    USE SIGNAL ;
    PORT
      LAYER M4 ;
        RECT  0 11.52 0.192 11.544 ;
    END
  END i[88]
  PIN i[89]
    DIRECTION INPUT ;
    USE SIGNAL ;
    PORT
      LAYER M4 ;
        RECT  0 11.616 0.192 11.64 ;
    END
  END i[89]
  PIN i[8]
    DIRECTION INPUT ;
    USE SIGNAL ;
    PORT
      LAYER M4 ;
        RECT  0 3.072 0.192 3.096 ;
    END
  END i[8]
  PIN i[90]
    DIRECTION INPUT ;
    USE SIGNAL ;
    PORT
      LAYER M4 ;
        RECT  0 11.712 0.192 11.736 ;
    END
  END i[90]
  PIN i[91]
    DIRECTION INPUT ;
    USE SIGNAL ;
    PORT
      LAYER M4 ;
        RECT  0 11.808 0.192 11.832 ;
    END
  END i[91]
  PIN i[92]
    DIRECTION INPUT ;
    USE SIGNAL ;
    PORT
      LAYER M4 ;
        RECT  0 11.904 0.192 11.928 ;
    END
  END i[92]
  PIN i[93]
    DIRECTION INPUT ;
    USE SIGNAL ;
    PORT
      LAYER M4 ;
        RECT  0 12.048 0.192 12.072 ;
    END
  END i[93]
  PIN i[94]
    DIRECTION INPUT ;
    USE SIGNAL ;
    PORT
      LAYER M4 ;
        RECT  0 12.144 0.192 12.168 ;
    END
  END i[94]
  PIN i[95]
    DIRECTION INPUT ;
    USE SIGNAL ;
    PORT
      LAYER M4 ;
        RECT  0 12.24 0.192 12.264 ;
    END
  END i[95]
  PIN i[96]
    DIRECTION INPUT ;
    USE SIGNAL ;
    PORT
      LAYER M4 ;
        RECT  0 12.336 0.192 12.36 ;
    END
  END i[96]
  PIN i[97]
    DIRECTION INPUT ;
    USE SIGNAL ;
    PORT
      LAYER M4 ;
        RECT  0 12.432 0.192 12.456 ;
    END
  END i[97]
  PIN i[98]
    DIRECTION INPUT ;
    USE SIGNAL ;
    PORT
      LAYER M4 ;
        RECT  0 12.576 0.192 12.6 ;
    END
  END i[98]
  PIN i[99]
    DIRECTION INPUT ;
    USE SIGNAL ;
    PORT
      LAYER M4 ;
        RECT  0 12.672 0.192 12.696 ;
    END
  END i[99]
  PIN i[9]
    DIRECTION INPUT ;
    USE SIGNAL ;
    PORT
      LAYER M4 ;
        RECT  0 3.168 0.192 3.192 ;
    END
  END i[9]
  PIN o[0]
    DIRECTION OUTPUT ;
    USE SIGNAL ;
    PORT
      LAYER M4 ;
        RECT  17.088 2.208 17.28 2.232 ;
    END
  END o[0]
  PIN o[100]
    DIRECTION OUTPUT ;
    USE SIGNAL ;
    PORT
      LAYER M4 ;
        RECT  17.088 12.768 17.28 12.792 ;
    END
  END o[100]
  PIN o[101]
    DIRECTION OUTPUT ;
    USE SIGNAL ;
    PORT
      LAYER M4 ;
        RECT  17.088 12.864 17.28 12.888 ;
    END
  END o[101]
  PIN o[102]
    DIRECTION OUTPUT ;
    USE SIGNAL ;
    PORT
      LAYER M4 ;
        RECT  17.088 12.96 17.28 12.984 ;
    END
  END o[102]
  PIN o[103]
    DIRECTION OUTPUT ;
    USE SIGNAL ;
    PORT
      LAYER M4 ;
        RECT  17.088 13.056 17.28 13.08 ;
    END
  END o[103]
  PIN o[104]
    DIRECTION OUTPUT ;
    USE SIGNAL ;
    PORT
      LAYER M4 ;
        RECT  17.088 13.152 17.28 13.176 ;
    END
  END o[104]
  PIN o[105]
    DIRECTION OUTPUT ;
    USE SIGNAL ;
    PORT
      LAYER M4 ;
        RECT  17.088 13.296 17.28 13.32 ;
    END
  END o[105]
  PIN o[106]
    DIRECTION OUTPUT ;
    USE SIGNAL ;
    PORT
      LAYER M4 ;
        RECT  17.088 13.392 17.28 13.416 ;
    END
  END o[106]
  PIN o[107]
    DIRECTION OUTPUT ;
    USE SIGNAL ;
    PORT
      LAYER M4 ;
        RECT  17.088 13.488 17.28 13.512 ;
    END
  END o[107]
  PIN o[108]
    DIRECTION OUTPUT ;
    USE SIGNAL ;
    PORT
      LAYER M4 ;
        RECT  17.088 13.584 17.28 13.608 ;
    END
  END o[108]
  PIN o[109]
    DIRECTION OUTPUT ;
    USE SIGNAL ;
    PORT
      LAYER M4 ;
        RECT  17.088 13.68 17.28 13.704 ;
    END
  END o[109]
  PIN o[10]
    DIRECTION OUTPUT ;
    USE SIGNAL ;
    PORT
      LAYER M4 ;
        RECT  17.088 3.264 17.28 3.288 ;
    END
  END o[10]
  PIN o[110]
    DIRECTION OUTPUT ;
    USE SIGNAL ;
    PORT
      LAYER M4 ;
        RECT  17.088 13.824 17.28 13.848 ;
    END
  END o[110]
  PIN o[111]
    DIRECTION OUTPUT ;
    USE SIGNAL ;
    PORT
      LAYER M4 ;
        RECT  17.088 13.92 17.28 13.944 ;
    END
  END o[111]
  PIN o[112]
    DIRECTION OUTPUT ;
    USE SIGNAL ;
    PORT
      LAYER M4 ;
        RECT  17.088 14.016 17.28 14.04 ;
    END
  END o[112]
  PIN o[113]
    DIRECTION OUTPUT ;
    USE SIGNAL ;
    PORT
      LAYER M4 ;
        RECT  17.088 14.112 17.28 14.136 ;
    END
  END o[113]
  PIN o[114]
    DIRECTION OUTPUT ;
    USE SIGNAL ;
    PORT
      LAYER M4 ;
        RECT  17.088 14.208 17.28 14.232 ;
    END
  END o[114]
  PIN o[115]
    DIRECTION OUTPUT ;
    USE SIGNAL ;
    PORT
      LAYER M4 ;
        RECT  17.088 14.352 17.28 14.376 ;
    END
  END o[115]
  PIN o[116]
    DIRECTION OUTPUT ;
    USE SIGNAL ;
    PORT
      LAYER M4 ;
        RECT  17.088 14.448 17.28 14.472 ;
    END
  END o[116]
  PIN o[117]
    DIRECTION OUTPUT ;
    USE SIGNAL ;
    PORT
      LAYER M4 ;
        RECT  17.088 14.544 17.28 14.568 ;
    END
  END o[117]
  PIN o[118]
    DIRECTION OUTPUT ;
    USE SIGNAL ;
    PORT
      LAYER M4 ;
        RECT  17.088 14.64 17.28 14.664 ;
    END
  END o[118]
  PIN o[119]
    DIRECTION OUTPUT ;
    USE SIGNAL ;
    PORT
      LAYER M4 ;
        RECT  17.088 14.736 17.28 14.76 ;
    END
  END o[119]
  PIN o[11]
    DIRECTION OUTPUT ;
    USE SIGNAL ;
    PORT
      LAYER M4 ;
        RECT  17.088 3.36 17.28 3.384 ;
    END
  END o[11]
  PIN o[120]
    DIRECTION OUTPUT ;
    USE SIGNAL ;
    PORT
      LAYER M4 ;
        RECT  17.088 14.88 17.28 14.904 ;
    END
  END o[120]
  PIN o[121]
    DIRECTION OUTPUT ;
    USE SIGNAL ;
    PORT
      LAYER M4 ;
        RECT  17.088 14.976 17.28 15 ;
    END
  END o[121]
  PIN o[122]
    DIRECTION OUTPUT ;
    USE SIGNAL ;
    PORT
      LAYER M4 ;
        RECT  17.088 15.072 17.28 15.096 ;
    END
  END o[122]
  PIN o[123]
    DIRECTION OUTPUT ;
    USE SIGNAL ;
    PORT
      LAYER M4 ;
        RECT  17.088 15.168 17.28 15.192 ;
    END
  END o[123]
  PIN o[124]
    DIRECTION OUTPUT ;
    USE SIGNAL ;
    PORT
      LAYER M4 ;
        RECT  17.088 15.264 17.28 15.288 ;
    END
  END o[124]
  PIN o[125]
    DIRECTION OUTPUT ;
    USE SIGNAL ;
    PORT
      LAYER M4 ;
        RECT  17.088 15.36 17.28 15.384 ;
    END
  END o[125]
  PIN o[126]
    DIRECTION OUTPUT ;
    USE SIGNAL ;
    PORT
      LAYER M4 ;
        RECT  17.088 15.504 17.28 15.528 ;
    END
  END o[126]
  PIN o[127]
    DIRECTION OUTPUT ;
    USE SIGNAL ;
    PORT
      LAYER M4 ;
        RECT  17.088 15.6 17.28 15.624 ;
    END
  END o[127]
  PIN o[128]
    DIRECTION OUTPUT ;
    USE SIGNAL ;
    PORT
      LAYER M4 ;
        RECT  17.088 15.696 17.28 15.72 ;
    END
  END o[128]
  PIN o[129]
    DIRECTION OUTPUT ;
    USE SIGNAL ;
    PORT
      LAYER M4 ;
        RECT  17.088 15.792 17.28 15.816 ;
    END
  END o[129]
  PIN o[12]
    DIRECTION OUTPUT ;
    USE SIGNAL ;
    PORT
      LAYER M4 ;
        RECT  17.088 3.504 17.28 3.528 ;
    END
  END o[12]
  PIN o[130]
    DIRECTION OUTPUT ;
    USE SIGNAL ;
    PORT
      LAYER M4 ;
        RECT  17.088 15.888 17.28 15.912 ;
    END
  END o[130]
  PIN o[131]
    DIRECTION OUTPUT ;
    USE SIGNAL ;
    PORT
      LAYER M4 ;
        RECT  17.088 16.032 17.28 16.056 ;
    END
  END o[131]
  PIN o[132]
    DIRECTION OUTPUT ;
    USE SIGNAL ;
    PORT
      LAYER M4 ;
        RECT  17.088 16.128 17.28 16.152 ;
    END
  END o[132]
  PIN o[133]
    DIRECTION OUTPUT ;
    USE SIGNAL ;
    PORT
      LAYER M4 ;
        RECT  17.088 16.224 17.28 16.248 ;
    END
  END o[133]
  PIN o[134]
    DIRECTION OUTPUT ;
    USE SIGNAL ;
    PORT
      LAYER M4 ;
        RECT  17.088 16.32 17.28 16.344 ;
    END
  END o[134]
  PIN o[135]
    DIRECTION OUTPUT ;
    USE SIGNAL ;
    PORT
      LAYER M4 ;
        RECT  17.088 16.416 17.28 16.44 ;
    END
  END o[135]
  PIN o[136]
    DIRECTION OUTPUT ;
    USE SIGNAL ;
    PORT
      LAYER M4 ;
        RECT  17.088 16.56 17.28 16.584 ;
    END
  END o[136]
  PIN o[137]
    DIRECTION OUTPUT ;
    USE SIGNAL ;
    PORT
      LAYER M4 ;
        RECT  17.088 16.656 17.28 16.68 ;
    END
  END o[137]
  PIN o[138]
    DIRECTION OUTPUT ;
    USE SIGNAL ;
    PORT
      LAYER M4 ;
        RECT  17.088 16.752 17.28 16.776 ;
    END
  END o[138]
  PIN o[139]
    DIRECTION OUTPUT ;
    USE SIGNAL ;
    PORT
      LAYER M4 ;
        RECT  17.088 16.848 17.28 16.872 ;
    END
  END o[139]
  PIN o[13]
    DIRECTION OUTPUT ;
    USE SIGNAL ;
    PORT
      LAYER M4 ;
        RECT  17.088 3.6 17.28 3.624 ;
    END
  END o[13]
  PIN o[140]
    DIRECTION OUTPUT ;
    USE SIGNAL ;
    PORT
      LAYER M4 ;
        RECT  17.088 16.944 17.28 16.968 ;
    END
  END o[140]
  PIN o[141]
    DIRECTION OUTPUT ;
    USE SIGNAL ;
    PORT
      LAYER M4 ;
        RECT  17.088 17.088 17.28 17.112 ;
    END
  END o[141]
  PIN o[142]
    DIRECTION OUTPUT ;
    USE SIGNAL ;
    PORT
      LAYER M4 ;
        RECT  17.088 17.184 17.28 17.208 ;
    END
  END o[142]
  PIN o[143]
    DIRECTION OUTPUT ;
    USE SIGNAL ;
    PORT
      LAYER M4 ;
        RECT  17.088 17.28 17.28 17.304 ;
    END
  END o[143]
  PIN o[144]
    DIRECTION OUTPUT ;
    USE SIGNAL ;
    PORT
      LAYER M4 ;
        RECT  17.088 17.376 17.28 17.4 ;
    END
  END o[144]
  PIN o[145]
    DIRECTION OUTPUT ;
    USE SIGNAL ;
    PORT
      LAYER M4 ;
        RECT  17.088 17.472 17.28 17.496 ;
    END
  END o[145]
  PIN o[146]
    DIRECTION OUTPUT ;
    USE SIGNAL ;
    PORT
      LAYER M4 ;
        RECT  17.088 17.616 17.28 17.64 ;
    END
  END o[146]
  PIN o[147]
    DIRECTION OUTPUT ;
    USE SIGNAL ;
    PORT
      LAYER M4 ;
        RECT  17.088 17.712 17.28 17.736 ;
    END
  END o[147]
  PIN o[148]
    DIRECTION OUTPUT ;
    USE SIGNAL ;
    PORT
      LAYER M4 ;
        RECT  17.088 17.808 17.28 17.832 ;
    END
  END o[148]
  PIN o[149]
    DIRECTION OUTPUT ;
    USE SIGNAL ;
    PORT
      LAYER M4 ;
        RECT  17.088 17.904 17.28 17.928 ;
    END
  END o[149]
  PIN o[14]
    DIRECTION OUTPUT ;
    USE SIGNAL ;
    PORT
      LAYER M4 ;
        RECT  17.088 3.696 17.28 3.72 ;
    END
  END o[14]
  PIN o[150]
    DIRECTION OUTPUT ;
    USE SIGNAL ;
    PORT
      LAYER M4 ;
        RECT  17.088 18 17.28 18.024 ;
    END
  END o[150]
  PIN o[151]
    DIRECTION OUTPUT ;
    USE SIGNAL ;
    PORT
      LAYER M4 ;
        RECT  17.088 18.096 17.28 18.12 ;
    END
  END o[151]
  PIN o[152]
    DIRECTION OUTPUT ;
    USE SIGNAL ;
    PORT
      LAYER M4 ;
        RECT  17.088 18.24 17.28 18.264 ;
    END
  END o[152]
  PIN o[153]
    DIRECTION OUTPUT ;
    USE SIGNAL ;
    PORT
      LAYER M4 ;
        RECT  17.088 18.336 17.28 18.36 ;
    END
  END o[153]
  PIN o[154]
    DIRECTION OUTPUT ;
    USE SIGNAL ;
    PORT
      LAYER M4 ;
        RECT  17.088 18.432 17.28 18.456 ;
    END
  END o[154]
  PIN o[155]
    DIRECTION OUTPUT ;
    USE SIGNAL ;
    PORT
      LAYER M4 ;
        RECT  17.088 18.528 17.28 18.552 ;
    END
  END o[155]
  PIN o[156]
    DIRECTION OUTPUT ;
    USE SIGNAL ;
    PORT
      LAYER M4 ;
        RECT  17.088 18.624 17.28 18.648 ;
    END
  END o[156]
  PIN o[157]
    DIRECTION OUTPUT ;
    USE SIGNAL ;
    PORT
      LAYER M4 ;
        RECT  17.088 18.768 17.28 18.792 ;
    END
  END o[157]
  PIN o[158]
    DIRECTION OUTPUT ;
    USE SIGNAL ;
    PORT
      LAYER M4 ;
        RECT  17.088 18.864 17.28 18.888 ;
    END
  END o[158]
  PIN o[159]
    DIRECTION OUTPUT ;
    USE SIGNAL ;
    PORT
      LAYER M4 ;
        RECT  17.088 18.96 17.28 18.984 ;
    END
  END o[159]
  PIN o[15]
    DIRECTION OUTPUT ;
    USE SIGNAL ;
    PORT
      LAYER M4 ;
        RECT  17.088 3.792 17.28 3.816 ;
    END
  END o[15]
  PIN o[160]
    DIRECTION OUTPUT ;
    USE SIGNAL ;
    PORT
      LAYER M4 ;
        RECT  17.088 19.056 17.28 19.08 ;
    END
  END o[160]
  PIN o[161]
    DIRECTION OUTPUT ;
    USE SIGNAL ;
    PORT
      LAYER M4 ;
        RECT  17.088 19.152 17.28 19.176 ;
    END
  END o[161]
  PIN o[162]
    DIRECTION OUTPUT ;
    USE SIGNAL ;
    PORT
      LAYER M4 ;
        RECT  17.088 19.296 17.28 19.32 ;
    END
  END o[162]
  PIN o[163]
    DIRECTION OUTPUT ;
    USE SIGNAL ;
    PORT
      LAYER M4 ;
        RECT  17.088 19.392 17.28 19.416 ;
    END
  END o[163]
  PIN o[164]
    DIRECTION OUTPUT ;
    USE SIGNAL ;
    PORT
      LAYER M4 ;
        RECT  17.088 19.488 17.28 19.512 ;
    END
  END o[164]
  PIN o[165]
    DIRECTION OUTPUT ;
    USE SIGNAL ;
    PORT
      LAYER M4 ;
        RECT  17.088 19.584 17.28 19.608 ;
    END
  END o[165]
  PIN o[166]
    DIRECTION OUTPUT ;
    USE SIGNAL ;
    PORT
      LAYER M4 ;
        RECT  17.088 19.68 17.28 19.704 ;
    END
  END o[166]
  PIN o[167]
    DIRECTION OUTPUT ;
    USE SIGNAL ;
    PORT
      LAYER M4 ;
        RECT  17.088 19.824 17.28 19.848 ;
    END
  END o[167]
  PIN o[168]
    DIRECTION OUTPUT ;
    USE SIGNAL ;
    PORT
      LAYER M4 ;
        RECT  17.088 19.92 17.28 19.944 ;
    END
  END o[168]
  PIN o[169]
    DIRECTION OUTPUT ;
    USE SIGNAL ;
    PORT
      LAYER M4 ;
        RECT  17.088 20.016 17.28 20.04 ;
    END
  END o[169]
  PIN o[16]
    DIRECTION OUTPUT ;
    USE SIGNAL ;
    PORT
      LAYER M4 ;
        RECT  17.088 3.888 17.28 3.912 ;
    END
  END o[16]
  PIN o[170]
    DIRECTION OUTPUT ;
    USE SIGNAL ;
    PORT
      LAYER M4 ;
        RECT  17.088 20.112 17.28 20.136 ;
    END
  END o[170]
  PIN o[171]
    DIRECTION OUTPUT ;
    USE SIGNAL ;
    PORT
      LAYER M4 ;
        RECT  17.088 20.208 17.28 20.232 ;
    END
  END o[171]
  PIN o[172]
    DIRECTION OUTPUT ;
    USE SIGNAL ;
    PORT
      LAYER M4 ;
        RECT  17.088 20.352 17.28 20.376 ;
    END
  END o[172]
  PIN o[173]
    DIRECTION OUTPUT ;
    USE SIGNAL ;
    PORT
      LAYER M4 ;
        RECT  17.088 20.448 17.28 20.472 ;
    END
  END o[173]
  PIN o[174]
    DIRECTION OUTPUT ;
    USE SIGNAL ;
    PORT
      LAYER M4 ;
        RECT  17.088 20.544 17.28 20.568 ;
    END
  END o[174]
  PIN o[175]
    DIRECTION OUTPUT ;
    USE SIGNAL ;
    PORT
      LAYER M4 ;
        RECT  17.088 20.64 17.28 20.664 ;
    END
  END o[175]
  PIN o[176]
    DIRECTION OUTPUT ;
    USE SIGNAL ;
    PORT
      LAYER M4 ;
        RECT  17.088 20.736 17.28 20.76 ;
    END
  END o[176]
  PIN o[177]
    DIRECTION OUTPUT ;
    USE SIGNAL ;
    PORT
      LAYER M4 ;
        RECT  17.088 20.88 17.28 20.904 ;
    END
  END o[177]
  PIN o[178]
    DIRECTION OUTPUT ;
    USE SIGNAL ;
    PORT
      LAYER M4 ;
        RECT  17.088 20.976 17.28 21 ;
    END
  END o[178]
  PIN o[179]
    DIRECTION OUTPUT ;
    USE SIGNAL ;
    PORT
      LAYER M4 ;
        RECT  17.088 21.072 17.28 21.096 ;
    END
  END o[179]
  PIN o[17]
    DIRECTION OUTPUT ;
    USE SIGNAL ;
    PORT
      LAYER M4 ;
        RECT  17.088 4.032 17.28 4.056 ;
    END
  END o[17]
  PIN o[180]
    DIRECTION OUTPUT ;
    USE SIGNAL ;
    PORT
      LAYER M4 ;
        RECT  17.088 21.168 17.28 21.192 ;
    END
  END o[180]
  PIN o[181]
    DIRECTION OUTPUT ;
    USE SIGNAL ;
    PORT
      LAYER M4 ;
        RECT  17.088 21.264 17.28 21.288 ;
    END
  END o[181]
  PIN o[182]
    DIRECTION OUTPUT ;
    USE SIGNAL ;
    PORT
      LAYER M4 ;
        RECT  17.088 21.36 17.28 21.384 ;
    END
  END o[182]
  PIN o[183]
    DIRECTION OUTPUT ;
    USE SIGNAL ;
    PORT
      LAYER M4 ;
        RECT  17.088 21.504 17.28 21.528 ;
    END
  END o[183]
  PIN o[184]
    DIRECTION OUTPUT ;
    USE SIGNAL ;
    PORT
      LAYER M4 ;
        RECT  17.088 21.6 17.28 21.624 ;
    END
  END o[184]
  PIN o[185]
    DIRECTION OUTPUT ;
    USE SIGNAL ;
    PORT
      LAYER M4 ;
        RECT  17.088 21.696 17.28 21.72 ;
    END
  END o[185]
  PIN o[186]
    DIRECTION OUTPUT ;
    USE SIGNAL ;
    PORT
      LAYER M4 ;
        RECT  17.088 21.792 17.28 21.816 ;
    END
  END o[186]
  PIN o[187]
    DIRECTION OUTPUT ;
    USE SIGNAL ;
    PORT
      LAYER M4 ;
        RECT  17.088 21.888 17.28 21.912 ;
    END
  END o[187]
  PIN o[188]
    DIRECTION OUTPUT ;
    USE SIGNAL ;
    PORT
      LAYER M4 ;
        RECT  17.088 22.032 17.28 22.056 ;
    END
  END o[188]
  PIN o[189]
    DIRECTION OUTPUT ;
    USE SIGNAL ;
    PORT
      LAYER M4 ;
        RECT  17.088 22.128 17.28 22.152 ;
    END
  END o[189]
  PIN o[18]
    DIRECTION OUTPUT ;
    USE SIGNAL ;
    PORT
      LAYER M4 ;
        RECT  17.088 4.128 17.28 4.152 ;
    END
  END o[18]
  PIN o[190]
    DIRECTION OUTPUT ;
    USE SIGNAL ;
    PORT
      LAYER M4 ;
        RECT  17.088 22.224 17.28 22.248 ;
    END
  END o[190]
  PIN o[191]
    DIRECTION OUTPUT ;
    USE SIGNAL ;
    PORT
      LAYER M4 ;
        RECT  17.088 22.32 17.28 22.344 ;
    END
  END o[191]
  PIN o[192]
    DIRECTION OUTPUT ;
    USE SIGNAL ;
    PORT
      LAYER M4 ;
        RECT  17.088 22.416 17.28 22.44 ;
    END
  END o[192]
  PIN o[193]
    DIRECTION OUTPUT ;
    USE SIGNAL ;
    PORT
      LAYER M4 ;
        RECT  17.088 22.56 17.28 22.584 ;
    END
  END o[193]
  PIN o[194]
    DIRECTION OUTPUT ;
    USE SIGNAL ;
    PORT
      LAYER M4 ;
        RECT  17.088 22.656 17.28 22.68 ;
    END
  END o[194]
  PIN o[195]
    DIRECTION OUTPUT ;
    USE SIGNAL ;
    PORT
      LAYER M4 ;
        RECT  17.088 22.752 17.28 22.776 ;
    END
  END o[195]
  PIN o[196]
    DIRECTION OUTPUT ;
    USE SIGNAL ;
    PORT
      LAYER M4 ;
        RECT  17.088 22.848 17.28 22.872 ;
    END
  END o[196]
  PIN o[197]
    DIRECTION OUTPUT ;
    USE SIGNAL ;
    PORT
      LAYER M4 ;
        RECT  17.088 22.944 17.28 22.968 ;
    END
  END o[197]
  PIN o[198]
    DIRECTION OUTPUT ;
    USE SIGNAL ;
    PORT
      LAYER M4 ;
        RECT  17.088 23.088 17.28 23.112 ;
    END
  END o[198]
  PIN o[199]
    DIRECTION OUTPUT ;
    USE SIGNAL ;
    PORT
      LAYER M4 ;
        RECT  17.088 23.184 17.28 23.208 ;
    END
  END o[199]
  PIN o[19]
    DIRECTION OUTPUT ;
    USE SIGNAL ;
    PORT
      LAYER M4 ;
        RECT  17.088 4.224 17.28 4.248 ;
    END
  END o[19]
  PIN o[1]
    DIRECTION OUTPUT ;
    USE SIGNAL ;
    PORT
      LAYER M4 ;
        RECT  17.088 2.352 17.28 2.376 ;
    END
  END o[1]
  PIN o[200]
    DIRECTION OUTPUT ;
    USE SIGNAL ;
    PORT
      LAYER M4 ;
        RECT  17.088 23.28 17.28 23.304 ;
    END
  END o[200]
  PIN o[201]
    DIRECTION OUTPUT ;
    USE SIGNAL ;
    PORT
      LAYER M4 ;
        RECT  17.088 23.376 17.28 23.4 ;
    END
  END o[201]
  PIN o[202]
    DIRECTION OUTPUT ;
    USE SIGNAL ;
    PORT
      LAYER M4 ;
        RECT  17.088 23.472 17.28 23.496 ;
    END
  END o[202]
  PIN o[203]
    DIRECTION OUTPUT ;
    USE SIGNAL ;
    PORT
      LAYER M4 ;
        RECT  17.088 23.616 17.28 23.64 ;
    END
  END o[203]
  PIN o[204]
    DIRECTION OUTPUT ;
    USE SIGNAL ;
    PORT
      LAYER M4 ;
        RECT  17.088 23.712 17.28 23.736 ;
    END
  END o[204]
  PIN o[205]
    DIRECTION OUTPUT ;
    USE SIGNAL ;
    PORT
      LAYER M4 ;
        RECT  17.088 23.808 17.28 23.832 ;
    END
  END o[205]
  PIN o[206]
    DIRECTION OUTPUT ;
    USE SIGNAL ;
    PORT
      LAYER M4 ;
        RECT  17.088 23.904 17.28 23.928 ;
    END
  END o[206]
  PIN o[207]
    DIRECTION OUTPUT ;
    USE SIGNAL ;
    PORT
      LAYER M4 ;
        RECT  17.088 24 17.28 24.024 ;
    END
  END o[207]
  PIN o[208]
    DIRECTION OUTPUT ;
    USE SIGNAL ;
    PORT
      LAYER M4 ;
        RECT  17.088 24.096 17.28 24.12 ;
    END
  END o[208]
  PIN o[209]
    DIRECTION OUTPUT ;
    USE SIGNAL ;
    PORT
      LAYER M4 ;
        RECT  17.088 24.24 17.28 24.264 ;
    END
  END o[209]
  PIN o[20]
    DIRECTION OUTPUT ;
    USE SIGNAL ;
    PORT
      LAYER M4 ;
        RECT  17.088 4.32 17.28 4.344 ;
    END
  END o[20]
  PIN o[210]
    DIRECTION OUTPUT ;
    USE SIGNAL ;
    PORT
      LAYER M4 ;
        RECT  17.088 24.336 17.28 24.36 ;
    END
  END o[210]
  PIN o[211]
    DIRECTION OUTPUT ;
    USE SIGNAL ;
    PORT
      LAYER M4 ;
        RECT  17.088 24.432 17.28 24.456 ;
    END
  END o[211]
  PIN o[212]
    DIRECTION OUTPUT ;
    USE SIGNAL ;
    PORT
      LAYER M4 ;
        RECT  17.088 24.528 17.28 24.552 ;
    END
  END o[212]
  PIN o[213]
    DIRECTION OUTPUT ;
    USE SIGNAL ;
    PORT
      LAYER M4 ;
        RECT  17.088 24.624 17.28 24.648 ;
    END
  END o[213]
  PIN o[214]
    DIRECTION OUTPUT ;
    USE SIGNAL ;
    PORT
      LAYER M4 ;
        RECT  17.088 24.768 17.28 24.792 ;
    END
  END o[214]
  PIN o[215]
    DIRECTION OUTPUT ;
    USE SIGNAL ;
    PORT
      LAYER M4 ;
        RECT  17.088 24.864 17.28 24.888 ;
    END
  END o[215]
  PIN o[216]
    DIRECTION OUTPUT ;
    USE SIGNAL ;
    PORT
      LAYER M4 ;
        RECT  17.088 24.96 17.28 24.984 ;
    END
  END o[216]
  PIN o[217]
    DIRECTION OUTPUT ;
    USE SIGNAL ;
    PORT
      LAYER M4 ;
        RECT  17.088 25.056 17.28 25.08 ;
    END
  END o[217]
  PIN o[218]
    DIRECTION OUTPUT ;
    USE SIGNAL ;
    PORT
      LAYER M4 ;
        RECT  17.088 25.152 17.28 25.176 ;
    END
  END o[218]
  PIN o[219]
    DIRECTION OUTPUT ;
    USE SIGNAL ;
    PORT
      LAYER M4 ;
        RECT  17.088 25.296 17.28 25.32 ;
    END
  END o[219]
  PIN o[21]
    DIRECTION OUTPUT ;
    USE SIGNAL ;
    PORT
      LAYER M4 ;
        RECT  17.088 4.416 17.28 4.44 ;
    END
  END o[21]
  PIN o[220]
    DIRECTION OUTPUT ;
    USE SIGNAL ;
    PORT
      LAYER M4 ;
        RECT  17.088 25.392 17.28 25.416 ;
    END
  END o[220]
  PIN o[221]
    DIRECTION OUTPUT ;
    USE SIGNAL ;
    PORT
      LAYER M4 ;
        RECT  17.088 25.488 17.28 25.512 ;
    END
  END o[221]
  PIN o[222]
    DIRECTION OUTPUT ;
    USE SIGNAL ;
    PORT
      LAYER M4 ;
        RECT  17.088 25.584 17.28 25.608 ;
    END
  END o[222]
  PIN o[223]
    DIRECTION OUTPUT ;
    USE SIGNAL ;
    PORT
      LAYER M4 ;
        RECT  17.088 25.68 17.28 25.704 ;
    END
  END o[223]
  PIN o[224]
    DIRECTION OUTPUT ;
    USE SIGNAL ;
    PORT
      LAYER M4 ;
        RECT  17.088 25.824 17.28 25.848 ;
    END
  END o[224]
  PIN o[225]
    DIRECTION OUTPUT ;
    USE SIGNAL ;
    PORT
      LAYER M4 ;
        RECT  17.088 25.92 17.28 25.944 ;
    END
  END o[225]
  PIN o[226]
    DIRECTION OUTPUT ;
    USE SIGNAL ;
    PORT
      LAYER M4 ;
        RECT  17.088 26.016 17.28 26.04 ;
    END
  END o[226]
  PIN o[227]
    DIRECTION OUTPUT ;
    USE SIGNAL ;
    PORT
      LAYER M4 ;
        RECT  17.088 26.112 17.28 26.136 ;
    END
  END o[227]
  PIN o[228]
    DIRECTION OUTPUT ;
    USE SIGNAL ;
    PORT
      LAYER M4 ;
        RECT  17.088 26.208 17.28 26.232 ;
    END
  END o[228]
  PIN o[229]
    DIRECTION OUTPUT ;
    USE SIGNAL ;
    PORT
      LAYER M4 ;
        RECT  17.088 26.352 17.28 26.376 ;
    END
  END o[229]
  PIN o[22]
    DIRECTION OUTPUT ;
    USE SIGNAL ;
    PORT
      LAYER M4 ;
        RECT  17.088 4.56 17.28 4.584 ;
    END
  END o[22]
  PIN o[230]
    DIRECTION OUTPUT ;
    USE SIGNAL ;
    PORT
      LAYER M4 ;
        RECT  17.088 26.448 17.28 26.472 ;
    END
  END o[230]
  PIN o[231]
    DIRECTION OUTPUT ;
    USE SIGNAL ;
    PORT
      LAYER M4 ;
        RECT  17.088 26.544 17.28 26.568 ;
    END
  END o[231]
  PIN o[232]
    DIRECTION OUTPUT ;
    USE SIGNAL ;
    PORT
      LAYER M4 ;
        RECT  17.088 26.64 17.28 26.664 ;
    END
  END o[232]
  PIN o[233]
    DIRECTION OUTPUT ;
    USE SIGNAL ;
    PORT
      LAYER M4 ;
        RECT  17.088 26.736 17.28 26.76 ;
    END
  END o[233]
  PIN o[234]
    DIRECTION OUTPUT ;
    USE SIGNAL ;
    PORT
      LAYER M4 ;
        RECT  17.088 26.88 17.28 26.904 ;
    END
  END o[234]
  PIN o[235]
    DIRECTION OUTPUT ;
    USE SIGNAL ;
    PORT
      LAYER M4 ;
        RECT  17.088 26.976 17.28 27 ;
    END
  END o[235]
  PIN o[236]
    DIRECTION OUTPUT ;
    USE SIGNAL ;
    PORT
      LAYER M4 ;
        RECT  17.088 27.072 17.28 27.096 ;
    END
  END o[236]
  PIN o[237]
    DIRECTION OUTPUT ;
    USE SIGNAL ;
    PORT
      LAYER M4 ;
        RECT  17.088 27.168 17.28 27.192 ;
    END
  END o[237]
  PIN o[238]
    DIRECTION OUTPUT ;
    USE SIGNAL ;
    PORT
      LAYER M4 ;
        RECT  17.088 27.264 17.28 27.288 ;
    END
  END o[238]
  PIN o[239]
    DIRECTION OUTPUT ;
    USE SIGNAL ;
    PORT
      LAYER M4 ;
        RECT  17.088 27.36 17.28 27.384 ;
    END
  END o[239]
  PIN o[23]
    DIRECTION OUTPUT ;
    USE SIGNAL ;
    PORT
      LAYER M4 ;
        RECT  17.088 4.656 17.28 4.68 ;
    END
  END o[23]
  PIN o[240]
    DIRECTION OUTPUT ;
    USE SIGNAL ;
    PORT
      LAYER M4 ;
        RECT  17.088 27.504 17.28 27.528 ;
    END
  END o[240]
  PIN o[241]
    DIRECTION OUTPUT ;
    USE SIGNAL ;
    PORT
      LAYER M4 ;
        RECT  17.088 27.6 17.28 27.624 ;
    END
  END o[241]
  PIN o[242]
    DIRECTION OUTPUT ;
    USE SIGNAL ;
    PORT
      LAYER M4 ;
        RECT  17.088 27.696 17.28 27.72 ;
    END
  END o[242]
  PIN o[243]
    DIRECTION OUTPUT ;
    USE SIGNAL ;
    PORT
      LAYER M4 ;
        RECT  17.088 27.792 17.28 27.816 ;
    END
  END o[243]
  PIN o[244]
    DIRECTION OUTPUT ;
    USE SIGNAL ;
    PORT
      LAYER M4 ;
        RECT  17.088 27.888 17.28 27.912 ;
    END
  END o[244]
  PIN o[245]
    DIRECTION OUTPUT ;
    USE SIGNAL ;
    PORT
      LAYER M4 ;
        RECT  17.088 28.032 17.28 28.056 ;
    END
  END o[245]
  PIN o[246]
    DIRECTION OUTPUT ;
    USE SIGNAL ;
    PORT
      LAYER M4 ;
        RECT  17.088 28.128 17.28 28.152 ;
    END
  END o[246]
  PIN o[247]
    DIRECTION OUTPUT ;
    USE SIGNAL ;
    PORT
      LAYER M4 ;
        RECT  17.088 28.224 17.28 28.248 ;
    END
  END o[247]
  PIN o[248]
    DIRECTION OUTPUT ;
    USE SIGNAL ;
    PORT
      LAYER M4 ;
        RECT  17.088 28.32 17.28 28.344 ;
    END
  END o[248]
  PIN o[249]
    DIRECTION OUTPUT ;
    USE SIGNAL ;
    PORT
      LAYER M4 ;
        RECT  17.088 28.416 17.28 28.44 ;
    END
  END o[249]
  PIN o[24]
    DIRECTION OUTPUT ;
    USE SIGNAL ;
    PORT
      LAYER M4 ;
        RECT  17.088 4.752 17.28 4.776 ;
    END
  END o[24]
  PIN o[250]
    DIRECTION OUTPUT ;
    USE SIGNAL ;
    PORT
      LAYER M4 ;
        RECT  17.088 28.56 17.28 28.584 ;
    END
  END o[250]
  PIN o[251]
    DIRECTION OUTPUT ;
    USE SIGNAL ;
    PORT
      LAYER M4 ;
        RECT  17.088 28.656 17.28 28.68 ;
    END
  END o[251]
  PIN o[252]
    DIRECTION OUTPUT ;
    USE SIGNAL ;
    PORT
      LAYER M4 ;
        RECT  17.088 28.752 17.28 28.776 ;
    END
  END o[252]
  PIN o[253]
    DIRECTION OUTPUT ;
    USE SIGNAL ;
    PORT
      LAYER M4 ;
        RECT  17.088 28.848 17.28 28.872 ;
    END
  END o[253]
  PIN o[254]
    DIRECTION OUTPUT ;
    USE SIGNAL ;
    PORT
      LAYER M4 ;
        RECT  17.088 28.944 17.28 28.968 ;
    END
  END o[254]
  PIN o[255]
    DIRECTION OUTPUT ;
    USE SIGNAL ;
    PORT
      LAYER M4 ;
        RECT  17.088 29.088 17.28 29.112 ;
    END
  END o[255]
  PIN o[256]
    DIRECTION OUTPUT ;
    USE SIGNAL ;
    PORT
      LAYER M4 ;
        RECT  17.088 29.184 17.28 29.208 ;
    END
  END o[256]
  PIN o[257]
    DIRECTION OUTPUT ;
    USE SIGNAL ;
    PORT
      LAYER M4 ;
        RECT  17.088 29.28 17.28 29.304 ;
    END
  END o[257]
  PIN o[258]
    DIRECTION OUTPUT ;
    USE SIGNAL ;
    PORT
      LAYER M4 ;
        RECT  17.088 29.376 17.28 29.4 ;
    END
  END o[258]
  PIN o[259]
    DIRECTION OUTPUT ;
    USE SIGNAL ;
    PORT
      LAYER M4 ;
        RECT  17.088 29.472 17.28 29.496 ;
    END
  END o[259]
  PIN o[25]
    DIRECTION OUTPUT ;
    USE SIGNAL ;
    PORT
      LAYER M4 ;
        RECT  17.088 4.848 17.28 4.872 ;
    END
  END o[25]
  PIN o[260]
    DIRECTION OUTPUT ;
    USE SIGNAL ;
    PORT
      LAYER M4 ;
        RECT  17.088 29.616 17.28 29.64 ;
    END
  END o[260]
  PIN o[261]
    DIRECTION OUTPUT ;
    USE SIGNAL ;
    PORT
      LAYER M4 ;
        RECT  17.088 29.712 17.28 29.736 ;
    END
  END o[261]
  PIN o[262]
    DIRECTION OUTPUT ;
    USE SIGNAL ;
    PORT
      LAYER M4 ;
        RECT  17.088 29.808 17.28 29.832 ;
    END
  END o[262]
  PIN o[263]
    DIRECTION OUTPUT ;
    USE SIGNAL ;
    PORT
      LAYER M4 ;
        RECT  17.088 29.904 17.28 29.928 ;
    END
  END o[263]
  PIN o[264]
    DIRECTION OUTPUT ;
    USE SIGNAL ;
    PORT
      LAYER M4 ;
        RECT  17.088 30 17.28 30.024 ;
    END
  END o[264]
  PIN o[265]
    DIRECTION OUTPUT ;
    USE SIGNAL ;
    PORT
      LAYER M4 ;
        RECT  17.088 30.096 17.28 30.12 ;
    END
  END o[265]
  PIN o[266]
    DIRECTION OUTPUT ;
    USE SIGNAL ;
    PORT
      LAYER M4 ;
        RECT  17.088 30.24 17.28 30.264 ;
    END
  END o[266]
  PIN o[267]
    DIRECTION OUTPUT ;
    USE SIGNAL ;
    PORT
      LAYER M4 ;
        RECT  17.088 30.336 17.28 30.36 ;
    END
  END o[267]
  PIN o[268]
    DIRECTION OUTPUT ;
    USE SIGNAL ;
    PORT
      LAYER M4 ;
        RECT  17.088 30.432 17.28 30.456 ;
    END
  END o[268]
  PIN o[269]
    DIRECTION OUTPUT ;
    USE SIGNAL ;
    PORT
      LAYER M4 ;
        RECT  17.088 30.528 17.28 30.552 ;
    END
  END o[269]
  PIN o[26]
    DIRECTION OUTPUT ;
    USE SIGNAL ;
    PORT
      LAYER M4 ;
        RECT  17.088 4.944 17.28 4.968 ;
    END
  END o[26]
  PIN o[270]
    DIRECTION OUTPUT ;
    USE SIGNAL ;
    PORT
      LAYER M4 ;
        RECT  17.088 30.624 17.28 30.648 ;
    END
  END o[270]
  PIN o[271]
    DIRECTION OUTPUT ;
    USE SIGNAL ;
    PORT
      LAYER M4 ;
        RECT  17.088 30.768 17.28 30.792 ;
    END
  END o[271]
  PIN o[272]
    DIRECTION OUTPUT ;
    USE SIGNAL ;
    PORT
      LAYER M4 ;
        RECT  17.088 30.864 17.28 30.888 ;
    END
  END o[272]
  PIN o[273]
    DIRECTION OUTPUT ;
    USE SIGNAL ;
    PORT
      LAYER M4 ;
        RECT  17.088 30.96 17.28 30.984 ;
    END
  END o[273]
  PIN o[274]
    DIRECTION OUTPUT ;
    USE SIGNAL ;
    PORT
      LAYER M4 ;
        RECT  17.088 31.056 17.28 31.08 ;
    END
  END o[274]
  PIN o[275]
    DIRECTION OUTPUT ;
    USE SIGNAL ;
    PORT
      LAYER M4 ;
        RECT  17.088 31.152 17.28 31.176 ;
    END
  END o[275]
  PIN o[276]
    DIRECTION OUTPUT ;
    USE SIGNAL ;
    PORT
      LAYER M4 ;
        RECT  17.088 31.296 17.28 31.32 ;
    END
  END o[276]
  PIN o[277]
    DIRECTION OUTPUT ;
    USE SIGNAL ;
    PORT
      LAYER M4 ;
        RECT  17.088 31.392 17.28 31.416 ;
    END
  END o[277]
  PIN o[278]
    DIRECTION OUTPUT ;
    USE SIGNAL ;
    PORT
      LAYER M4 ;
        RECT  17.088 31.488 17.28 31.512 ;
    END
  END o[278]
  PIN o[279]
    DIRECTION OUTPUT ;
    USE SIGNAL ;
    PORT
      LAYER M4 ;
        RECT  17.088 31.584 17.28 31.608 ;
    END
  END o[279]
  PIN o[27]
    DIRECTION OUTPUT ;
    USE SIGNAL ;
    PORT
      LAYER M4 ;
        RECT  17.088 5.088 17.28 5.112 ;
    END
  END o[27]
  PIN o[280]
    DIRECTION OUTPUT ;
    USE SIGNAL ;
    PORT
      LAYER M4 ;
        RECT  17.088 31.68 17.28 31.704 ;
    END
  END o[280]
  PIN o[281]
    DIRECTION OUTPUT ;
    USE SIGNAL ;
    PORT
      LAYER M4 ;
        RECT  17.088 31.824 17.28 31.848 ;
    END
  END o[281]
  PIN o[282]
    DIRECTION OUTPUT ;
    USE SIGNAL ;
    PORT
      LAYER M4 ;
        RECT  17.088 31.92 17.28 31.944 ;
    END
  END o[282]
  PIN o[283]
    DIRECTION OUTPUT ;
    USE SIGNAL ;
    PORT
      LAYER M4 ;
        RECT  17.088 32.016 17.28 32.04 ;
    END
  END o[283]
  PIN o[284]
    DIRECTION OUTPUT ;
    USE SIGNAL ;
    PORT
      LAYER M4 ;
        RECT  17.088 32.112 17.28 32.136 ;
    END
  END o[284]
  PIN o[285]
    DIRECTION OUTPUT ;
    USE SIGNAL ;
    PORT
      LAYER M4 ;
        RECT  17.088 32.208 17.28 32.232 ;
    END
  END o[285]
  PIN o[286]
    DIRECTION OUTPUT ;
    USE SIGNAL ;
    PORT
      LAYER M4 ;
        RECT  17.088 32.352 17.28 32.376 ;
    END
  END o[286]
  PIN o[287]
    DIRECTION OUTPUT ;
    USE SIGNAL ;
    PORT
      LAYER M4 ;
        RECT  17.088 32.448 17.28 32.472 ;
    END
  END o[287]
  PIN o[288]
    DIRECTION OUTPUT ;
    USE SIGNAL ;
    PORT
      LAYER M4 ;
        RECT  17.088 32.544 17.28 32.568 ;
    END
  END o[288]
  PIN o[289]
    DIRECTION OUTPUT ;
    USE SIGNAL ;
    PORT
      LAYER M4 ;
        RECT  17.088 32.64 17.28 32.664 ;
    END
  END o[289]
  PIN o[28]
    DIRECTION OUTPUT ;
    USE SIGNAL ;
    PORT
      LAYER M4 ;
        RECT  17.088 5.184 17.28 5.208 ;
    END
  END o[28]
  PIN o[290]
    DIRECTION OUTPUT ;
    USE SIGNAL ;
    PORT
      LAYER M4 ;
        RECT  17.088 32.736 17.28 32.76 ;
    END
  END o[290]
  PIN o[291]
    DIRECTION OUTPUT ;
    USE SIGNAL ;
    PORT
      LAYER M4 ;
        RECT  17.088 32.88 17.28 32.904 ;
    END
  END o[291]
  PIN o[292]
    DIRECTION OUTPUT ;
    USE SIGNAL ;
    PORT
      LAYER M4 ;
        RECT  17.088 32.976 17.28 33 ;
    END
  END o[292]
  PIN o[293]
    DIRECTION OUTPUT ;
    USE SIGNAL ;
    PORT
      LAYER M4 ;
        RECT  17.088 33.072 17.28 33.096 ;
    END
  END o[293]
  PIN o[294]
    DIRECTION OUTPUT ;
    USE SIGNAL ;
    PORT
      LAYER M4 ;
        RECT  17.088 33.168 17.28 33.192 ;
    END
  END o[294]
  PIN o[295]
    DIRECTION OUTPUT ;
    USE SIGNAL ;
    PORT
      LAYER M4 ;
        RECT  17.088 33.264 17.28 33.288 ;
    END
  END o[295]
  PIN o[296]
    DIRECTION OUTPUT ;
    USE SIGNAL ;
    PORT
      LAYER M4 ;
        RECT  17.088 33.36 17.28 33.384 ;
    END
  END o[296]
  PIN o[297]
    DIRECTION OUTPUT ;
    USE SIGNAL ;
    PORT
      LAYER M4 ;
        RECT  17.088 33.504 17.28 33.528 ;
    END
  END o[297]
  PIN o[298]
    DIRECTION OUTPUT ;
    USE SIGNAL ;
    PORT
      LAYER M4 ;
        RECT  17.088 33.6 17.28 33.624 ;
    END
  END o[298]
  PIN o[299]
    DIRECTION OUTPUT ;
    USE SIGNAL ;
    PORT
      LAYER M4 ;
        RECT  17.088 33.696 17.28 33.72 ;
    END
  END o[299]
  PIN o[29]
    DIRECTION OUTPUT ;
    USE SIGNAL ;
    PORT
      LAYER M4 ;
        RECT  17.088 5.28 17.28 5.304 ;
    END
  END o[29]
  PIN o[2]
    DIRECTION OUTPUT ;
    USE SIGNAL ;
    PORT
      LAYER M4 ;
        RECT  17.088 2.448 17.28 2.472 ;
    END
  END o[2]
  PIN o[300]
    DIRECTION OUTPUT ;
    USE SIGNAL ;
    PORT
      LAYER M4 ;
        RECT  17.088 33.792 17.28 33.816 ;
    END
  END o[300]
  PIN o[301]
    DIRECTION OUTPUT ;
    USE SIGNAL ;
    PORT
      LAYER M4 ;
        RECT  17.088 33.888 17.28 33.912 ;
    END
  END o[301]
  PIN o[302]
    DIRECTION OUTPUT ;
    USE SIGNAL ;
    PORT
      LAYER M4 ;
        RECT  17.088 34.032 17.28 34.056 ;
    END
  END o[302]
  PIN o[303]
    DIRECTION OUTPUT ;
    USE SIGNAL ;
    PORT
      LAYER M4 ;
        RECT  17.088 34.128 17.28 34.152 ;
    END
  END o[303]
  PIN o[304]
    DIRECTION OUTPUT ;
    USE SIGNAL ;
    PORT
      LAYER M4 ;
        RECT  17.088 34.224 17.28 34.248 ;
    END
  END o[304]
  PIN o[305]
    DIRECTION OUTPUT ;
    USE SIGNAL ;
    PORT
      LAYER M4 ;
        RECT  17.088 34.32 17.28 34.344 ;
    END
  END o[305]
  PIN o[306]
    DIRECTION OUTPUT ;
    USE SIGNAL ;
    PORT
      LAYER M4 ;
        RECT  17.088 34.416 17.28 34.44 ;
    END
  END o[306]
  PIN o[307]
    DIRECTION OUTPUT ;
    USE SIGNAL ;
    PORT
      LAYER M4 ;
        RECT  17.088 34.56 17.28 34.584 ;
    END
  END o[307]
  PIN o[308]
    DIRECTION OUTPUT ;
    USE SIGNAL ;
    PORT
      LAYER M4 ;
        RECT  17.088 34.656 17.28 34.68 ;
    END
  END o[308]
  PIN o[309]
    DIRECTION OUTPUT ;
    USE SIGNAL ;
    PORT
      LAYER M4 ;
        RECT  17.088 34.752 17.28 34.776 ;
    END
  END o[309]
  PIN o[30]
    DIRECTION OUTPUT ;
    USE SIGNAL ;
    PORT
      LAYER M4 ;
        RECT  17.088 5.376 17.28 5.4 ;
    END
  END o[30]
  PIN o[310]
    DIRECTION OUTPUT ;
    USE SIGNAL ;
    PORT
      LAYER M4 ;
        RECT  17.088 34.848 17.28 34.872 ;
    END
  END o[310]
  PIN o[311]
    DIRECTION OUTPUT ;
    USE SIGNAL ;
    PORT
      LAYER M4 ;
        RECT  17.088 34.944 17.28 34.968 ;
    END
  END o[311]
  PIN o[312]
    DIRECTION OUTPUT ;
    USE SIGNAL ;
    PORT
      LAYER M4 ;
        RECT  17.088 35.088 17.28 35.112 ;
    END
  END o[312]
  PIN o[313]
    DIRECTION OUTPUT ;
    USE SIGNAL ;
    PORT
      LAYER M4 ;
        RECT  17.088 35.184 17.28 35.208 ;
    END
  END o[313]
  PIN o[314]
    DIRECTION OUTPUT ;
    USE SIGNAL ;
    PORT
      LAYER M4 ;
        RECT  17.088 35.28 17.28 35.304 ;
    END
  END o[314]
  PIN o[315]
    DIRECTION OUTPUT ;
    USE SIGNAL ;
    PORT
      LAYER M4 ;
        RECT  17.088 35.376 17.28 35.4 ;
    END
  END o[315]
  PIN o[316]
    DIRECTION OUTPUT ;
    USE SIGNAL ;
    PORT
      LAYER M4 ;
        RECT  17.088 35.472 17.28 35.496 ;
    END
  END o[316]
  PIN o[317]
    DIRECTION OUTPUT ;
    USE SIGNAL ;
    PORT
      LAYER M4 ;
        RECT  17.088 35.616 17.28 35.64 ;
    END
  END o[317]
  PIN o[318]
    DIRECTION OUTPUT ;
    USE SIGNAL ;
    PORT
      LAYER M4 ;
        RECT  17.088 35.712 17.28 35.736 ;
    END
  END o[318]
  PIN o[319]
    DIRECTION OUTPUT ;
    USE SIGNAL ;
    PORT
      LAYER M4 ;
        RECT  17.088 35.808 17.28 35.832 ;
    END
  END o[319]
  PIN o[31]
    DIRECTION OUTPUT ;
    USE SIGNAL ;
    PORT
      LAYER M4 ;
        RECT  17.088 5.472 17.28 5.496 ;
    END
  END o[31]
  PIN o[320]
    DIRECTION OUTPUT ;
    USE SIGNAL ;
    PORT
      LAYER M4 ;
        RECT  17.088 35.904 17.28 35.928 ;
    END
  END o[320]
  PIN o[321]
    DIRECTION OUTPUT ;
    USE SIGNAL ;
    PORT
      LAYER M4 ;
        RECT  17.088 36 17.28 36.024 ;
    END
  END o[321]
  PIN o[322]
    DIRECTION OUTPUT ;
    USE SIGNAL ;
    PORT
      LAYER M4 ;
        RECT  17.088 36.096 17.28 36.12 ;
    END
  END o[322]
  PIN o[323]
    DIRECTION OUTPUT ;
    USE SIGNAL ;
    PORT
      LAYER M4 ;
        RECT  17.088 36.24 17.28 36.264 ;
    END
  END o[323]
  PIN o[324]
    DIRECTION OUTPUT ;
    USE SIGNAL ;
    PORT
      LAYER M4 ;
        RECT  17.088 36.336 17.28 36.36 ;
    END
  END o[324]
  PIN o[325]
    DIRECTION OUTPUT ;
    USE SIGNAL ;
    PORT
      LAYER M4 ;
        RECT  17.088 36.432 17.28 36.456 ;
    END
  END o[325]
  PIN o[326]
    DIRECTION OUTPUT ;
    USE SIGNAL ;
    PORT
      LAYER M4 ;
        RECT  17.088 36.528 17.28 36.552 ;
    END
  END o[326]
  PIN o[327]
    DIRECTION OUTPUT ;
    USE SIGNAL ;
    PORT
      LAYER M4 ;
        RECT  17.088 36.624 17.28 36.648 ;
    END
  END o[327]
  PIN o[328]
    DIRECTION OUTPUT ;
    USE SIGNAL ;
    PORT
      LAYER M4 ;
        RECT  17.088 36.768 17.28 36.792 ;
    END
  END o[328]
  PIN o[329]
    DIRECTION OUTPUT ;
    USE SIGNAL ;
    PORT
      LAYER M4 ;
        RECT  17.088 36.864 17.28 36.888 ;
    END
  END o[329]
  PIN o[32]
    DIRECTION OUTPUT ;
    USE SIGNAL ;
    PORT
      LAYER M4 ;
        RECT  17.088 5.616 17.28 5.64 ;
    END
  END o[32]
  PIN o[330]
    DIRECTION OUTPUT ;
    USE SIGNAL ;
    PORT
      LAYER M4 ;
        RECT  17.088 36.96 17.28 36.984 ;
    END
  END o[330]
  PIN o[331]
    DIRECTION OUTPUT ;
    USE SIGNAL ;
    PORT
      LAYER M4 ;
        RECT  17.088 37.056 17.28 37.08 ;
    END
  END o[331]
  PIN o[332]
    DIRECTION OUTPUT ;
    USE SIGNAL ;
    PORT
      LAYER M4 ;
        RECT  17.088 37.152 17.28 37.176 ;
    END
  END o[332]
  PIN o[333]
    DIRECTION OUTPUT ;
    USE SIGNAL ;
    PORT
      LAYER M4 ;
        RECT  17.088 37.296 17.28 37.32 ;
    END
  END o[333]
  PIN o[334]
    DIRECTION OUTPUT ;
    USE SIGNAL ;
    PORT
      LAYER M4 ;
        RECT  17.088 37.392 17.28 37.416 ;
    END
  END o[334]
  PIN o[335]
    DIRECTION OUTPUT ;
    USE SIGNAL ;
    PORT
      LAYER M4 ;
        RECT  17.088 37.488 17.28 37.512 ;
    END
  END o[335]
  PIN o[336]
    DIRECTION OUTPUT ;
    USE SIGNAL ;
    PORT
      LAYER M4 ;
        RECT  17.088 37.584 17.28 37.608 ;
    END
  END o[336]
  PIN o[337]
    DIRECTION OUTPUT ;
    USE SIGNAL ;
    PORT
      LAYER M4 ;
        RECT  17.088 37.68 17.28 37.704 ;
    END
  END o[337]
  PIN o[338]
    DIRECTION OUTPUT ;
    USE SIGNAL ;
    PORT
      LAYER M4 ;
        RECT  17.088 37.824 17.28 37.848 ;
    END
  END o[338]
  PIN o[339]
    DIRECTION OUTPUT ;
    USE SIGNAL ;
    PORT
      LAYER M4 ;
        RECT  17.088 37.92 17.28 37.944 ;
    END
  END o[339]
  PIN o[33]
    DIRECTION OUTPUT ;
    USE SIGNAL ;
    PORT
      LAYER M4 ;
        RECT  17.088 5.712 17.28 5.736 ;
    END
  END o[33]
  PIN o[340]
    DIRECTION OUTPUT ;
    USE SIGNAL ;
    PORT
      LAYER M4 ;
        RECT  17.088 38.016 17.28 38.04 ;
    END
  END o[340]
  PIN o[341]
    DIRECTION OUTPUT ;
    USE SIGNAL ;
    PORT
      LAYER M4 ;
        RECT  17.088 38.112 17.28 38.136 ;
    END
  END o[341]
  PIN o[342]
    DIRECTION OUTPUT ;
    USE SIGNAL ;
    PORT
      LAYER M4 ;
        RECT  17.088 38.208 17.28 38.232 ;
    END
  END o[342]
  PIN o[343]
    DIRECTION OUTPUT ;
    USE SIGNAL ;
    PORT
      LAYER M4 ;
        RECT  17.088 38.352 17.28 38.376 ;
    END
  END o[343]
  PIN o[344]
    DIRECTION OUTPUT ;
    USE SIGNAL ;
    PORT
      LAYER M4 ;
        RECT  17.088 38.448 17.28 38.472 ;
    END
  END o[344]
  PIN o[345]
    DIRECTION OUTPUT ;
    USE SIGNAL ;
    PORT
      LAYER M4 ;
        RECT  17.088 38.544 17.28 38.568 ;
    END
  END o[345]
  PIN o[346]
    DIRECTION OUTPUT ;
    USE SIGNAL ;
    PORT
      LAYER M4 ;
        RECT  17.088 38.64 17.28 38.664 ;
    END
  END o[346]
  PIN o[347]
    DIRECTION OUTPUT ;
    USE SIGNAL ;
    PORT
      LAYER M4 ;
        RECT  17.088 38.736 17.28 38.76 ;
    END
  END o[347]
  PIN o[348]
    DIRECTION OUTPUT ;
    USE SIGNAL ;
    PORT
      LAYER M4 ;
        RECT  17.088 38.88 17.28 38.904 ;
    END
  END o[348]
  PIN o[349]
    DIRECTION OUTPUT ;
    USE SIGNAL ;
    PORT
      LAYER M4 ;
        RECT  17.088 38.976 17.28 39 ;
    END
  END o[349]
  PIN o[34]
    DIRECTION OUTPUT ;
    USE SIGNAL ;
    PORT
      LAYER M4 ;
        RECT  17.088 5.808 17.28 5.832 ;
    END
  END o[34]
  PIN o[350]
    DIRECTION OUTPUT ;
    USE SIGNAL ;
    PORT
      LAYER M4 ;
        RECT  17.088 39.072 17.28 39.096 ;
    END
  END o[350]
  PIN o[351]
    DIRECTION OUTPUT ;
    USE SIGNAL ;
    PORT
      LAYER M4 ;
        RECT  17.088 39.168 17.28 39.192 ;
    END
  END o[351]
  PIN o[352]
    DIRECTION OUTPUT ;
    USE SIGNAL ;
    PORT
      LAYER M4 ;
        RECT  17.088 39.264 17.28 39.288 ;
    END
  END o[352]
  PIN o[353]
    DIRECTION OUTPUT ;
    USE SIGNAL ;
    PORT
      LAYER M4 ;
        RECT  17.088 39.36 17.28 39.384 ;
    END
  END o[353]
  PIN o[354]
    DIRECTION OUTPUT ;
    USE SIGNAL ;
    PORT
      LAYER M4 ;
        RECT  17.088 39.504 17.28 39.528 ;
    END
  END o[354]
  PIN o[355]
    DIRECTION OUTPUT ;
    USE SIGNAL ;
    PORT
      LAYER M4 ;
        RECT  17.088 39.6 17.28 39.624 ;
    END
  END o[355]
  PIN o[356]
    DIRECTION OUTPUT ;
    USE SIGNAL ;
    PORT
      LAYER M4 ;
        RECT  17.088 39.696 17.28 39.72 ;
    END
  END o[356]
  PIN o[357]
    DIRECTION OUTPUT ;
    USE SIGNAL ;
    PORT
      LAYER M4 ;
        RECT  17.088 39.792 17.28 39.816 ;
    END
  END o[357]
  PIN o[358]
    DIRECTION OUTPUT ;
    USE SIGNAL ;
    PORT
      LAYER M4 ;
        RECT  17.088 39.888 17.28 39.912 ;
    END
  END o[358]
  PIN o[359]
    DIRECTION OUTPUT ;
    USE SIGNAL ;
    PORT
      LAYER M4 ;
        RECT  17.088 40.032 17.28 40.056 ;
    END
  END o[359]
  PIN o[35]
    DIRECTION OUTPUT ;
    USE SIGNAL ;
    PORT
      LAYER M4 ;
        RECT  17.088 5.904 17.28 5.928 ;
    END
  END o[35]
  PIN o[360]
    DIRECTION OUTPUT ;
    USE SIGNAL ;
    PORT
      LAYER M4 ;
        RECT  17.088 40.128 17.28 40.152 ;
    END
  END o[360]
  PIN o[361]
    DIRECTION OUTPUT ;
    USE SIGNAL ;
    PORT
      LAYER M4 ;
        RECT  17.088 40.224 17.28 40.248 ;
    END
  END o[361]
  PIN o[362]
    DIRECTION OUTPUT ;
    USE SIGNAL ;
    PORT
      LAYER M4 ;
        RECT  17.088 40.32 17.28 40.344 ;
    END
  END o[362]
  PIN o[363]
    DIRECTION OUTPUT ;
    USE SIGNAL ;
    PORT
      LAYER M4 ;
        RECT  17.088 40.416 17.28 40.44 ;
    END
  END o[363]
  PIN o[364]
    DIRECTION OUTPUT ;
    USE SIGNAL ;
    PORT
      LAYER M4 ;
        RECT  17.088 40.56 17.28 40.584 ;
    END
  END o[364]
  PIN o[365]
    DIRECTION OUTPUT ;
    USE SIGNAL ;
    PORT
      LAYER M4 ;
        RECT  17.088 40.656 17.28 40.68 ;
    END
  END o[365]
  PIN o[366]
    DIRECTION OUTPUT ;
    USE SIGNAL ;
    PORT
      LAYER M4 ;
        RECT  17.088 40.752 17.28 40.776 ;
    END
  END o[366]
  PIN o[367]
    DIRECTION OUTPUT ;
    USE SIGNAL ;
    PORT
      LAYER M4 ;
        RECT  17.088 40.848 17.28 40.872 ;
    END
  END o[367]
  PIN o[368]
    DIRECTION OUTPUT ;
    USE SIGNAL ;
    PORT
      LAYER M4 ;
        RECT  17.088 40.944 17.28 40.968 ;
    END
  END o[368]
  PIN o[369]
    DIRECTION OUTPUT ;
    USE SIGNAL ;
    PORT
      LAYER M4 ;
        RECT  17.088 41.088 17.28 41.112 ;
    END
  END o[369]
  PIN o[36]
    DIRECTION OUTPUT ;
    USE SIGNAL ;
    PORT
      LAYER M4 ;
        RECT  17.088 6 17.28 6.024 ;
    END
  END o[36]
  PIN o[370]
    DIRECTION OUTPUT ;
    USE SIGNAL ;
    PORT
      LAYER M4 ;
        RECT  17.088 41.184 17.28 41.208 ;
    END
  END o[370]
  PIN o[371]
    DIRECTION OUTPUT ;
    USE SIGNAL ;
    PORT
      LAYER M4 ;
        RECT  17.088 41.28 17.28 41.304 ;
    END
  END o[371]
  PIN o[372]
    DIRECTION OUTPUT ;
    USE SIGNAL ;
    PORT
      LAYER M4 ;
        RECT  17.088 41.376 17.28 41.4 ;
    END
  END o[372]
  PIN o[373]
    DIRECTION OUTPUT ;
    USE SIGNAL ;
    PORT
      LAYER M4 ;
        RECT  17.088 41.472 17.28 41.496 ;
    END
  END o[373]
  PIN o[374]
    DIRECTION OUTPUT ;
    USE SIGNAL ;
    PORT
      LAYER M4 ;
        RECT  17.088 41.616 17.28 41.64 ;
    END
  END o[374]
  PIN o[375]
    DIRECTION OUTPUT ;
    USE SIGNAL ;
    PORT
      LAYER M4 ;
        RECT  17.088 41.712 17.28 41.736 ;
    END
  END o[375]
  PIN o[376]
    DIRECTION OUTPUT ;
    USE SIGNAL ;
    PORT
      LAYER M4 ;
        RECT  17.088 41.808 17.28 41.832 ;
    END
  END o[376]
  PIN o[377]
    DIRECTION OUTPUT ;
    USE SIGNAL ;
    PORT
      LAYER M4 ;
        RECT  17.088 41.904 17.28 41.928 ;
    END
  END o[377]
  PIN o[378]
    DIRECTION OUTPUT ;
    USE SIGNAL ;
    PORT
      LAYER M4 ;
        RECT  17.088 42 17.28 42.024 ;
    END
  END o[378]
  PIN o[379]
    DIRECTION OUTPUT ;
    USE SIGNAL ;
    PORT
      LAYER M4 ;
        RECT  17.088 42.096 17.28 42.12 ;
    END
  END o[379]
  PIN o[37]
    DIRECTION OUTPUT ;
    USE SIGNAL ;
    PORT
      LAYER M4 ;
        RECT  17.088 6.096 17.28 6.12 ;
    END
  END o[37]
  PIN o[380]
    DIRECTION OUTPUT ;
    USE SIGNAL ;
    PORT
      LAYER M4 ;
        RECT  17.088 42.24 17.28 42.264 ;
    END
  END o[380]
  PIN o[381]
    DIRECTION OUTPUT ;
    USE SIGNAL ;
    PORT
      LAYER M4 ;
        RECT  17.088 42.336 17.28 42.36 ;
    END
  END o[381]
  PIN o[382]
    DIRECTION OUTPUT ;
    USE SIGNAL ;
    PORT
      LAYER M4 ;
        RECT  17.088 42.432 17.28 42.456 ;
    END
  END o[382]
  PIN o[383]
    DIRECTION OUTPUT ;
    USE SIGNAL ;
    PORT
      LAYER M4 ;
        RECT  17.088 42.528 17.28 42.552 ;
    END
  END o[383]
  PIN o[384]
    DIRECTION OUTPUT ;
    USE SIGNAL ;
    PORT
      LAYER M4 ;
        RECT  17.088 42.624 17.28 42.648 ;
    END
  END o[384]
  PIN o[385]
    DIRECTION OUTPUT ;
    USE SIGNAL ;
    PORT
      LAYER M4 ;
        RECT  17.088 42.768 17.28 42.792 ;
    END
  END o[385]
  PIN o[386]
    DIRECTION OUTPUT ;
    USE SIGNAL ;
    PORT
      LAYER M4 ;
        RECT  17.088 42.864 17.28 42.888 ;
    END
  END o[386]
  PIN o[387]
    DIRECTION OUTPUT ;
    USE SIGNAL ;
    PORT
      LAYER M4 ;
        RECT  17.088 42.96 17.28 42.984 ;
    END
  END o[387]
  PIN o[388]
    DIRECTION OUTPUT ;
    USE SIGNAL ;
    PORT
      LAYER M4 ;
        RECT  17.088 43.056 17.28 43.08 ;
    END
  END o[388]
  PIN o[389]
    DIRECTION OUTPUT ;
    USE SIGNAL ;
    PORT
      LAYER M4 ;
        RECT  17.088 43.152 17.28 43.176 ;
    END
  END o[389]
  PIN o[38]
    DIRECTION OUTPUT ;
    USE SIGNAL ;
    PORT
      LAYER M4 ;
        RECT  17.088 6.24 17.28 6.264 ;
    END
  END o[38]
  PIN o[390]
    DIRECTION OUTPUT ;
    USE SIGNAL ;
    PORT
      LAYER M4 ;
        RECT  17.088 43.296 17.28 43.32 ;
    END
  END o[390]
  PIN o[391]
    DIRECTION OUTPUT ;
    USE SIGNAL ;
    PORT
      LAYER M4 ;
        RECT  17.088 43.392 17.28 43.416 ;
    END
  END o[391]
  PIN o[392]
    DIRECTION OUTPUT ;
    USE SIGNAL ;
    PORT
      LAYER M4 ;
        RECT  17.088 43.488 17.28 43.512 ;
    END
  END o[392]
  PIN o[393]
    DIRECTION OUTPUT ;
    USE SIGNAL ;
    PORT
      LAYER M4 ;
        RECT  17.088 43.584 17.28 43.608 ;
    END
  END o[393]
  PIN o[394]
    DIRECTION OUTPUT ;
    USE SIGNAL ;
    PORT
      LAYER M4 ;
        RECT  17.088 43.68 17.28 43.704 ;
    END
  END o[394]
  PIN o[395]
    DIRECTION OUTPUT ;
    USE SIGNAL ;
    PORT
      LAYER M4 ;
        RECT  17.088 43.824 17.28 43.848 ;
    END
  END o[395]
  PIN o[396]
    DIRECTION OUTPUT ;
    USE SIGNAL ;
    PORT
      LAYER M4 ;
        RECT  17.088 43.92 17.28 43.944 ;
    END
  END o[396]
  PIN o[397]
    DIRECTION OUTPUT ;
    USE SIGNAL ;
    PORT
      LAYER M4 ;
        RECT  17.088 44.016 17.28 44.04 ;
    END
  END o[397]
  PIN o[398]
    DIRECTION OUTPUT ;
    USE SIGNAL ;
    PORT
      LAYER M4 ;
        RECT  17.088 44.112 17.28 44.136 ;
    END
  END o[398]
  PIN o[399]
    DIRECTION OUTPUT ;
    USE SIGNAL ;
    PORT
      LAYER M4 ;
        RECT  17.088 44.208 17.28 44.232 ;
    END
  END o[399]
  PIN o[39]
    DIRECTION OUTPUT ;
    USE SIGNAL ;
    PORT
      LAYER M4 ;
        RECT  17.088 6.336 17.28 6.36 ;
    END
  END o[39]
  PIN o[3]
    DIRECTION OUTPUT ;
    USE SIGNAL ;
    PORT
      LAYER M4 ;
        RECT  17.088 2.544 17.28 2.568 ;
    END
  END o[3]
  PIN o[400]
    DIRECTION OUTPUT ;
    USE SIGNAL ;
    PORT
      LAYER M4 ;
        RECT  17.088 44.352 17.28 44.376 ;
    END
  END o[400]
  PIN o[401]
    DIRECTION OUTPUT ;
    USE SIGNAL ;
    PORT
      LAYER M4 ;
        RECT  17.088 44.448 17.28 44.472 ;
    END
  END o[401]
  PIN o[402]
    DIRECTION OUTPUT ;
    USE SIGNAL ;
    PORT
      LAYER M4 ;
        RECT  17.088 44.544 17.28 44.568 ;
    END
  END o[402]
  PIN o[403]
    DIRECTION OUTPUT ;
    USE SIGNAL ;
    PORT
      LAYER M4 ;
        RECT  17.088 44.64 17.28 44.664 ;
    END
  END o[403]
  PIN o[404]
    DIRECTION OUTPUT ;
    USE SIGNAL ;
    PORT
      LAYER M4 ;
        RECT  17.088 44.736 17.28 44.76 ;
    END
  END o[404]
  PIN o[405]
    DIRECTION OUTPUT ;
    USE SIGNAL ;
    PORT
      LAYER M4 ;
        RECT  17.088 44.88 17.28 44.904 ;
    END
  END o[405]
  PIN o[406]
    DIRECTION OUTPUT ;
    USE SIGNAL ;
    PORT
      LAYER M4 ;
        RECT  17.088 44.976 17.28 45 ;
    END
  END o[406]
  PIN o[407]
    DIRECTION OUTPUT ;
    USE SIGNAL ;
    PORT
      LAYER M4 ;
        RECT  17.088 45.072 17.28 45.096 ;
    END
  END o[407]
  PIN o[408]
    DIRECTION OUTPUT ;
    USE SIGNAL ;
    PORT
      LAYER M4 ;
        RECT  17.088 45.168 17.28 45.192 ;
    END
  END o[408]
  PIN o[409]
    DIRECTION OUTPUT ;
    USE SIGNAL ;
    PORT
      LAYER M4 ;
        RECT  17.088 45.264 17.28 45.288 ;
    END
  END o[409]
  PIN o[40]
    DIRECTION OUTPUT ;
    USE SIGNAL ;
    PORT
      LAYER M4 ;
        RECT  17.088 6.432 17.28 6.456 ;
    END
  END o[40]
  PIN o[410]
    DIRECTION OUTPUT ;
    USE SIGNAL ;
    PORT
      LAYER M4 ;
        RECT  17.088 45.36 17.28 45.384 ;
    END
  END o[410]
  PIN o[411]
    DIRECTION OUTPUT ;
    USE SIGNAL ;
    PORT
      LAYER M4 ;
        RECT  17.088 45.504 17.28 45.528 ;
    END
  END o[411]
  PIN o[412]
    DIRECTION OUTPUT ;
    USE SIGNAL ;
    PORT
      LAYER M4 ;
        RECT  17.088 45.6 17.28 45.624 ;
    END
  END o[412]
  PIN o[413]
    DIRECTION OUTPUT ;
    USE SIGNAL ;
    PORT
      LAYER M4 ;
        RECT  17.088 45.696 17.28 45.72 ;
    END
  END o[413]
  PIN o[414]
    DIRECTION OUTPUT ;
    USE SIGNAL ;
    PORT
      LAYER M4 ;
        RECT  17.088 45.792 17.28 45.816 ;
    END
  END o[414]
  PIN o[415]
    DIRECTION OUTPUT ;
    USE SIGNAL ;
    PORT
      LAYER M4 ;
        RECT  17.088 45.888 17.28 45.912 ;
    END
  END o[415]
  PIN o[416]
    DIRECTION OUTPUT ;
    USE SIGNAL ;
    PORT
      LAYER M4 ;
        RECT  17.088 46.032 17.28 46.056 ;
    END
  END o[416]
  PIN o[417]
    DIRECTION OUTPUT ;
    USE SIGNAL ;
    PORT
      LAYER M4 ;
        RECT  17.088 46.128 17.28 46.152 ;
    END
  END o[417]
  PIN o[418]
    DIRECTION OUTPUT ;
    USE SIGNAL ;
    PORT
      LAYER M4 ;
        RECT  17.088 46.224 17.28 46.248 ;
    END
  END o[418]
  PIN o[419]
    DIRECTION OUTPUT ;
    USE SIGNAL ;
    PORT
      LAYER M4 ;
        RECT  17.088 46.32 17.28 46.344 ;
    END
  END o[419]
  PIN o[41]
    DIRECTION OUTPUT ;
    USE SIGNAL ;
    PORT
      LAYER M4 ;
        RECT  17.088 6.528 17.28 6.552 ;
    END
  END o[41]
  PIN o[420]
    DIRECTION OUTPUT ;
    USE SIGNAL ;
    PORT
      LAYER M4 ;
        RECT  17.088 46.416 17.28 46.44 ;
    END
  END o[420]
  PIN o[421]
    DIRECTION OUTPUT ;
    USE SIGNAL ;
    PORT
      LAYER M4 ;
        RECT  17.088 46.56 17.28 46.584 ;
    END
  END o[421]
  PIN o[422]
    DIRECTION OUTPUT ;
    USE SIGNAL ;
    PORT
      LAYER M4 ;
        RECT  17.088 46.656 17.28 46.68 ;
    END
  END o[422]
  PIN o[423]
    DIRECTION OUTPUT ;
    USE SIGNAL ;
    PORT
      LAYER M4 ;
        RECT  17.088 46.752 17.28 46.776 ;
    END
  END o[423]
  PIN o[424]
    DIRECTION OUTPUT ;
    USE SIGNAL ;
    PORT
      LAYER M4 ;
        RECT  17.088 46.848 17.28 46.872 ;
    END
  END o[424]
  PIN o[425]
    DIRECTION OUTPUT ;
    USE SIGNAL ;
    PORT
      LAYER M4 ;
        RECT  17.088 46.944 17.28 46.968 ;
    END
  END o[425]
  PIN o[426]
    DIRECTION OUTPUT ;
    USE SIGNAL ;
    PORT
      LAYER M4 ;
        RECT  17.088 47.088 17.28 47.112 ;
    END
  END o[426]
  PIN o[427]
    DIRECTION OUTPUT ;
    USE SIGNAL ;
    PORT
      LAYER M4 ;
        RECT  17.088 47.184 17.28 47.208 ;
    END
  END o[427]
  PIN o[428]
    DIRECTION OUTPUT ;
    USE SIGNAL ;
    PORT
      LAYER M4 ;
        RECT  17.088 47.28 17.28 47.304 ;
    END
  END o[428]
  PIN o[429]
    DIRECTION OUTPUT ;
    USE SIGNAL ;
    PORT
      LAYER M4 ;
        RECT  17.088 47.376 17.28 47.4 ;
    END
  END o[429]
  PIN o[42]
    DIRECTION OUTPUT ;
    USE SIGNAL ;
    PORT
      LAYER M4 ;
        RECT  17.088 6.624 17.28 6.648 ;
    END
  END o[42]
  PIN o[430]
    DIRECTION OUTPUT ;
    USE SIGNAL ;
    PORT
      LAYER M4 ;
        RECT  17.088 47.472 17.28 47.496 ;
    END
  END o[430]
  PIN o[431]
    DIRECTION OUTPUT ;
    USE SIGNAL ;
    PORT
      LAYER M4 ;
        RECT  17.088 47.616 17.28 47.64 ;
    END
  END o[431]
  PIN o[432]
    DIRECTION OUTPUT ;
    USE SIGNAL ;
    PORT
      LAYER M4 ;
        RECT  17.088 47.712 17.28 47.736 ;
    END
  END o[432]
  PIN o[433]
    DIRECTION OUTPUT ;
    USE SIGNAL ;
    PORT
      LAYER M4 ;
        RECT  17.088 47.808 17.28 47.832 ;
    END
  END o[433]
  PIN o[434]
    DIRECTION OUTPUT ;
    USE SIGNAL ;
    PORT
      LAYER M4 ;
        RECT  17.088 47.904 17.28 47.928 ;
    END
  END o[434]
  PIN o[435]
    DIRECTION OUTPUT ;
    USE SIGNAL ;
    PORT
      LAYER M4 ;
        RECT  17.088 48 17.28 48.024 ;
    END
  END o[435]
  PIN o[436]
    DIRECTION OUTPUT ;
    USE SIGNAL ;
    PORT
      LAYER M4 ;
        RECT  17.088 48.096 17.28 48.12 ;
    END
  END o[436]
  PIN o[437]
    DIRECTION OUTPUT ;
    USE SIGNAL ;
    PORT
      LAYER M4 ;
        RECT  17.088 48.24 17.28 48.264 ;
    END
  END o[437]
  PIN o[438]
    DIRECTION OUTPUT ;
    USE SIGNAL ;
    PORT
      LAYER M4 ;
        RECT  17.088 48.336 17.28 48.36 ;
    END
  END o[438]
  PIN o[439]
    DIRECTION OUTPUT ;
    USE SIGNAL ;
    PORT
      LAYER M4 ;
        RECT  17.088 48.432 17.28 48.456 ;
    END
  END o[439]
  PIN o[43]
    DIRECTION OUTPUT ;
    USE SIGNAL ;
    PORT
      LAYER M4 ;
        RECT  17.088 6.768 17.28 6.792 ;
    END
  END o[43]
  PIN o[440]
    DIRECTION OUTPUT ;
    USE SIGNAL ;
    PORT
      LAYER M4 ;
        RECT  17.088 48.528 17.28 48.552 ;
    END
  END o[440]
  PIN o[441]
    DIRECTION OUTPUT ;
    USE SIGNAL ;
    PORT
      LAYER M4 ;
        RECT  17.088 48.624 17.28 48.648 ;
    END
  END o[441]
  PIN o[442]
    DIRECTION OUTPUT ;
    USE SIGNAL ;
    PORT
      LAYER M4 ;
        RECT  17.088 48.768 17.28 48.792 ;
    END
  END o[442]
  PIN o[443]
    DIRECTION OUTPUT ;
    USE SIGNAL ;
    PORT
      LAYER M4 ;
        RECT  17.088 48.864 17.28 48.888 ;
    END
  END o[443]
  PIN o[444]
    DIRECTION OUTPUT ;
    USE SIGNAL ;
    PORT
      LAYER M4 ;
        RECT  17.088 48.96 17.28 48.984 ;
    END
  END o[444]
  PIN o[445]
    DIRECTION OUTPUT ;
    USE SIGNAL ;
    PORT
      LAYER M4 ;
        RECT  17.088 49.056 17.28 49.08 ;
    END
  END o[445]
  PIN o[446]
    DIRECTION OUTPUT ;
    USE SIGNAL ;
    PORT
      LAYER M4 ;
        RECT  17.088 49.152 17.28 49.176 ;
    END
  END o[446]
  PIN o[447]
    DIRECTION OUTPUT ;
    USE SIGNAL ;
    PORT
      LAYER M4 ;
        RECT  17.088 49.296 17.28 49.32 ;
    END
  END o[447]
  PIN o[448]
    DIRECTION OUTPUT ;
    USE SIGNAL ;
    PORT
      LAYER M4 ;
        RECT  17.088 49.392 17.28 49.416 ;
    END
  END o[448]
  PIN o[449]
    DIRECTION OUTPUT ;
    USE SIGNAL ;
    PORT
      LAYER M4 ;
        RECT  17.088 49.488 17.28 49.512 ;
    END
  END o[449]
  PIN o[44]
    DIRECTION OUTPUT ;
    USE SIGNAL ;
    PORT
      LAYER M4 ;
        RECT  17.088 6.864 17.28 6.888 ;
    END
  END o[44]
  PIN o[450]
    DIRECTION OUTPUT ;
    USE SIGNAL ;
    PORT
      LAYER M4 ;
        RECT  17.088 49.584 17.28 49.608 ;
    END
  END o[450]
  PIN o[451]
    DIRECTION OUTPUT ;
    USE SIGNAL ;
    PORT
      LAYER M4 ;
        RECT  17.088 49.68 17.28 49.704 ;
    END
  END o[451]
  PIN o[452]
    DIRECTION OUTPUT ;
    USE SIGNAL ;
    PORT
      LAYER M4 ;
        RECT  17.088 49.824 17.28 49.848 ;
    END
  END o[452]
  PIN o[453]
    DIRECTION OUTPUT ;
    USE SIGNAL ;
    PORT
      LAYER M4 ;
        RECT  17.088 49.92 17.28 49.944 ;
    END
  END o[453]
  PIN o[454]
    DIRECTION OUTPUT ;
    USE SIGNAL ;
    PORT
      LAYER M4 ;
        RECT  17.088 50.016 17.28 50.04 ;
    END
  END o[454]
  PIN o[455]
    DIRECTION OUTPUT ;
    USE SIGNAL ;
    PORT
      LAYER M4 ;
        RECT  17.088 50.112 17.28 50.136 ;
    END
  END o[455]
  PIN o[456]
    DIRECTION OUTPUT ;
    USE SIGNAL ;
    PORT
      LAYER M4 ;
        RECT  17.088 50.208 17.28 50.232 ;
    END
  END o[456]
  PIN o[457]
    DIRECTION OUTPUT ;
    USE SIGNAL ;
    PORT
      LAYER M4 ;
        RECT  17.088 50.352 17.28 50.376 ;
    END
  END o[457]
  PIN o[458]
    DIRECTION OUTPUT ;
    USE SIGNAL ;
    PORT
      LAYER M4 ;
        RECT  17.088 50.448 17.28 50.472 ;
    END
  END o[458]
  PIN o[459]
    DIRECTION OUTPUT ;
    USE SIGNAL ;
    PORT
      LAYER M4 ;
        RECT  17.088 50.544 17.28 50.568 ;
    END
  END o[459]
  PIN o[45]
    DIRECTION OUTPUT ;
    USE SIGNAL ;
    PORT
      LAYER M4 ;
        RECT  17.088 6.96 17.28 6.984 ;
    END
  END o[45]
  PIN o[460]
    DIRECTION OUTPUT ;
    USE SIGNAL ;
    PORT
      LAYER M4 ;
        RECT  17.088 50.64 17.28 50.664 ;
    END
  END o[460]
  PIN o[461]
    DIRECTION OUTPUT ;
    USE SIGNAL ;
    PORT
      LAYER M4 ;
        RECT  17.088 50.736 17.28 50.76 ;
    END
  END o[461]
  PIN o[462]
    DIRECTION OUTPUT ;
    USE SIGNAL ;
    PORT
      LAYER M4 ;
        RECT  17.088 50.88 17.28 50.904 ;
    END
  END o[462]
  PIN o[463]
    DIRECTION OUTPUT ;
    USE SIGNAL ;
    PORT
      LAYER M4 ;
        RECT  17.088 50.976 17.28 51 ;
    END
  END o[463]
  PIN o[464]
    DIRECTION OUTPUT ;
    USE SIGNAL ;
    PORT
      LAYER M4 ;
        RECT  17.088 51.072 17.28 51.096 ;
    END
  END o[464]
  PIN o[465]
    DIRECTION OUTPUT ;
    USE SIGNAL ;
    PORT
      LAYER M4 ;
        RECT  17.088 51.168 17.28 51.192 ;
    END
  END o[465]
  PIN o[466]
    DIRECTION OUTPUT ;
    USE SIGNAL ;
    PORT
      LAYER M4 ;
        RECT  17.088 51.264 17.28 51.288 ;
    END
  END o[466]
  PIN o[467]
    DIRECTION OUTPUT ;
    USE SIGNAL ;
    PORT
      LAYER M4 ;
        RECT  17.088 51.36 17.28 51.384 ;
    END
  END o[467]
  PIN o[468]
    DIRECTION OUTPUT ;
    USE SIGNAL ;
    PORT
      LAYER M4 ;
        RECT  17.088 51.504 17.28 51.528 ;
    END
  END o[468]
  PIN o[469]
    DIRECTION OUTPUT ;
    USE SIGNAL ;
    PORT
      LAYER M4 ;
        RECT  17.088 51.6 17.28 51.624 ;
    END
  END o[469]
  PIN o[46]
    DIRECTION OUTPUT ;
    USE SIGNAL ;
    PORT
      LAYER M4 ;
        RECT  17.088 7.056 17.28 7.08 ;
    END
  END o[46]
  PIN o[470]
    DIRECTION OUTPUT ;
    USE SIGNAL ;
    PORT
      LAYER M4 ;
        RECT  17.088 51.696 17.28 51.72 ;
    END
  END o[470]
  PIN o[471]
    DIRECTION OUTPUT ;
    USE SIGNAL ;
    PORT
      LAYER M4 ;
        RECT  17.088 51.792 17.28 51.816 ;
    END
  END o[471]
  PIN o[472]
    DIRECTION OUTPUT ;
    USE SIGNAL ;
    PORT
      LAYER M4 ;
        RECT  17.088 51.888 17.28 51.912 ;
    END
  END o[472]
  PIN o[473]
    DIRECTION OUTPUT ;
    USE SIGNAL ;
    PORT
      LAYER M4 ;
        RECT  17.088 52.032 17.28 52.056 ;
    END
  END o[473]
  PIN o[474]
    DIRECTION OUTPUT ;
    USE SIGNAL ;
    PORT
      LAYER M4 ;
        RECT  17.088 52.128 17.28 52.152 ;
    END
  END o[474]
  PIN o[475]
    DIRECTION OUTPUT ;
    USE SIGNAL ;
    PORT
      LAYER M4 ;
        RECT  17.088 52.224 17.28 52.248 ;
    END
  END o[475]
  PIN o[476]
    DIRECTION OUTPUT ;
    USE SIGNAL ;
    PORT
      LAYER M4 ;
        RECT  17.088 52.32 17.28 52.344 ;
    END
  END o[476]
  PIN o[477]
    DIRECTION OUTPUT ;
    USE SIGNAL ;
    PORT
      LAYER M4 ;
        RECT  17.088 52.416 17.28 52.44 ;
    END
  END o[477]
  PIN o[478]
    DIRECTION OUTPUT ;
    USE SIGNAL ;
    PORT
      LAYER M4 ;
        RECT  17.088 52.56 17.28 52.584 ;
    END
  END o[478]
  PIN o[479]
    DIRECTION OUTPUT ;
    USE SIGNAL ;
    PORT
      LAYER M4 ;
        RECT  17.088 52.656 17.28 52.68 ;
    END
  END o[479]
  PIN o[47]
    DIRECTION OUTPUT ;
    USE SIGNAL ;
    PORT
      LAYER M4 ;
        RECT  17.088 7.152 17.28 7.176 ;
    END
  END o[47]
  PIN o[480]
    DIRECTION OUTPUT ;
    USE SIGNAL ;
    PORT
      LAYER M4 ;
        RECT  17.088 52.752 17.28 52.776 ;
    END
  END o[480]
  PIN o[481]
    DIRECTION OUTPUT ;
    USE SIGNAL ;
    PORT
      LAYER M4 ;
        RECT  17.088 52.848 17.28 52.872 ;
    END
  END o[481]
  PIN o[482]
    DIRECTION OUTPUT ;
    USE SIGNAL ;
    PORT
      LAYER M4 ;
        RECT  17.088 52.944 17.28 52.968 ;
    END
  END o[482]
  PIN o[483]
    DIRECTION OUTPUT ;
    USE SIGNAL ;
    PORT
      LAYER M4 ;
        RECT  17.088 53.088 17.28 53.112 ;
    END
  END o[483]
  PIN o[484]
    DIRECTION OUTPUT ;
    USE SIGNAL ;
    PORT
      LAYER M4 ;
        RECT  17.088 53.184 17.28 53.208 ;
    END
  END o[484]
  PIN o[485]
    DIRECTION OUTPUT ;
    USE SIGNAL ;
    PORT
      LAYER M4 ;
        RECT  17.088 53.28 17.28 53.304 ;
    END
  END o[485]
  PIN o[486]
    DIRECTION OUTPUT ;
    USE SIGNAL ;
    PORT
      LAYER M4 ;
        RECT  17.088 53.376 17.28 53.4 ;
    END
  END o[486]
  PIN o[487]
    DIRECTION OUTPUT ;
    USE SIGNAL ;
    PORT
      LAYER M4 ;
        RECT  17.088 53.472 17.28 53.496 ;
    END
  END o[487]
  PIN o[488]
    DIRECTION OUTPUT ;
    USE SIGNAL ;
    PORT
      LAYER M4 ;
        RECT  17.088 53.616 17.28 53.64 ;
    END
  END o[488]
  PIN o[489]
    DIRECTION OUTPUT ;
    USE SIGNAL ;
    PORT
      LAYER M4 ;
        RECT  17.088 53.712 17.28 53.736 ;
    END
  END o[489]
  PIN o[48]
    DIRECTION OUTPUT ;
    USE SIGNAL ;
    PORT
      LAYER M4 ;
        RECT  17.088 7.296 17.28 7.32 ;
    END
  END o[48]
  PIN o[490]
    DIRECTION OUTPUT ;
    USE SIGNAL ;
    PORT
      LAYER M4 ;
        RECT  17.088 53.808 17.28 53.832 ;
    END
  END o[490]
  PIN o[491]
    DIRECTION OUTPUT ;
    USE SIGNAL ;
    PORT
      LAYER M4 ;
        RECT  17.088 53.904 17.28 53.928 ;
    END
  END o[491]
  PIN o[492]
    DIRECTION OUTPUT ;
    USE SIGNAL ;
    PORT
      LAYER M4 ;
        RECT  17.088 54 17.28 54.024 ;
    END
  END o[492]
  PIN o[493]
    DIRECTION OUTPUT ;
    USE SIGNAL ;
    PORT
      LAYER M4 ;
        RECT  17.088 54.096 17.28 54.12 ;
    END
  END o[493]
  PIN o[494]
    DIRECTION OUTPUT ;
    USE SIGNAL ;
    PORT
      LAYER M4 ;
        RECT  17.088 54.24 17.28 54.264 ;
    END
  END o[494]
  PIN o[495]
    DIRECTION OUTPUT ;
    USE SIGNAL ;
    PORT
      LAYER M4 ;
        RECT  17.088 54.336 17.28 54.36 ;
    END
  END o[495]
  PIN o[496]
    DIRECTION OUTPUT ;
    USE SIGNAL ;
    PORT
      LAYER M4 ;
        RECT  17.088 54.432 17.28 54.456 ;
    END
  END o[496]
  PIN o[497]
    DIRECTION OUTPUT ;
    USE SIGNAL ;
    PORT
      LAYER M4 ;
        RECT  17.088 54.528 17.28 54.552 ;
    END
  END o[497]
  PIN o[498]
    DIRECTION OUTPUT ;
    USE SIGNAL ;
    PORT
      LAYER M4 ;
        RECT  17.088 54.624 17.28 54.648 ;
    END
  END o[498]
  PIN o[499]
    DIRECTION OUTPUT ;
    USE SIGNAL ;
    PORT
      LAYER M4 ;
        RECT  17.088 54.768 17.28 54.792 ;
    END
  END o[499]
  PIN o[49]
    DIRECTION OUTPUT ;
    USE SIGNAL ;
    PORT
      LAYER M4 ;
        RECT  17.088 7.392 17.28 7.416 ;
    END
  END o[49]
  PIN o[4]
    DIRECTION OUTPUT ;
    USE SIGNAL ;
    PORT
      LAYER M4 ;
        RECT  17.088 2.64 17.28 2.664 ;
    END
  END o[4]
  PIN o[500]
    DIRECTION OUTPUT ;
    USE SIGNAL ;
    PORT
      LAYER M4 ;
        RECT  17.088 54.864 17.28 54.888 ;
    END
  END o[500]
  PIN o[501]
    DIRECTION OUTPUT ;
    USE SIGNAL ;
    PORT
      LAYER M4 ;
        RECT  17.088 54.96 17.28 54.984 ;
    END
  END o[501]
  PIN o[502]
    DIRECTION OUTPUT ;
    USE SIGNAL ;
    PORT
      LAYER M4 ;
        RECT  17.088 55.056 17.28 55.08 ;
    END
  END o[502]
  PIN o[503]
    DIRECTION OUTPUT ;
    USE SIGNAL ;
    PORT
      LAYER M4 ;
        RECT  17.088 55.152 17.28 55.176 ;
    END
  END o[503]
  PIN o[504]
    DIRECTION OUTPUT ;
    USE SIGNAL ;
    PORT
      LAYER M4 ;
        RECT  17.088 55.296 17.28 55.32 ;
    END
  END o[504]
  PIN o[505]
    DIRECTION OUTPUT ;
    USE SIGNAL ;
    PORT
      LAYER M4 ;
        RECT  17.088 55.392 17.28 55.416 ;
    END
  END o[505]
  PIN o[506]
    DIRECTION OUTPUT ;
    USE SIGNAL ;
    PORT
      LAYER M4 ;
        RECT  17.088 55.488 17.28 55.512 ;
    END
  END o[506]
  PIN o[507]
    DIRECTION OUTPUT ;
    USE SIGNAL ;
    PORT
      LAYER M4 ;
        RECT  17.088 55.584 17.28 55.608 ;
    END
  END o[507]
  PIN o[508]
    DIRECTION OUTPUT ;
    USE SIGNAL ;
    PORT
      LAYER M4 ;
        RECT  17.088 55.68 17.28 55.704 ;
    END
  END o[508]
  PIN o[509]
    DIRECTION OUTPUT ;
    USE SIGNAL ;
    PORT
      LAYER M4 ;
        RECT  17.088 55.824 17.28 55.848 ;
    END
  END o[509]
  PIN o[50]
    DIRECTION OUTPUT ;
    USE SIGNAL ;
    PORT
      LAYER M4 ;
        RECT  17.088 7.488 17.28 7.512 ;
    END
  END o[50]
  PIN o[510]
    DIRECTION OUTPUT ;
    USE SIGNAL ;
    PORT
      LAYER M4 ;
        RECT  17.088 55.92 17.28 55.944 ;
    END
  END o[510]
  PIN o[511]
    DIRECTION OUTPUT ;
    USE SIGNAL ;
    PORT
      LAYER M4 ;
        RECT  17.088 56.016 17.28 56.04 ;
    END
  END o[511]
  PIN o[51]
    DIRECTION OUTPUT ;
    USE SIGNAL ;
    PORT
      LAYER M4 ;
        RECT  17.088 7.584 17.28 7.608 ;
    END
  END o[51]
  PIN o[52]
    DIRECTION OUTPUT ;
    USE SIGNAL ;
    PORT
      LAYER M4 ;
        RECT  17.088 7.68 17.28 7.704 ;
    END
  END o[52]
  PIN o[53]
    DIRECTION OUTPUT ;
    USE SIGNAL ;
    PORT
      LAYER M4 ;
        RECT  17.088 7.824 17.28 7.848 ;
    END
  END o[53]
  PIN o[54]
    DIRECTION OUTPUT ;
    USE SIGNAL ;
    PORT
      LAYER M4 ;
        RECT  17.088 7.92 17.28 7.944 ;
    END
  END o[54]
  PIN o[55]
    DIRECTION OUTPUT ;
    USE SIGNAL ;
    PORT
      LAYER M4 ;
        RECT  17.088 8.016 17.28 8.04 ;
    END
  END o[55]
  PIN o[56]
    DIRECTION OUTPUT ;
    USE SIGNAL ;
    PORT
      LAYER M4 ;
        RECT  17.088 8.112 17.28 8.136 ;
    END
  END o[56]
  PIN o[57]
    DIRECTION OUTPUT ;
    USE SIGNAL ;
    PORT
      LAYER M4 ;
        RECT  17.088 8.208 17.28 8.232 ;
    END
  END o[57]
  PIN o[58]
    DIRECTION OUTPUT ;
    USE SIGNAL ;
    PORT
      LAYER M4 ;
        RECT  17.088 8.352 17.28 8.376 ;
    END
  END o[58]
  PIN o[59]
    DIRECTION OUTPUT ;
    USE SIGNAL ;
    PORT
      LAYER M4 ;
        RECT  17.088 8.448 17.28 8.472 ;
    END
  END o[59]
  PIN o[5]
    DIRECTION OUTPUT ;
    USE SIGNAL ;
    PORT
      LAYER M4 ;
        RECT  17.088 2.736 17.28 2.76 ;
    END
  END o[5]
  PIN o[60]
    DIRECTION OUTPUT ;
    USE SIGNAL ;
    PORT
      LAYER M4 ;
        RECT  17.088 8.544 17.28 8.568 ;
    END
  END o[60]
  PIN o[61]
    DIRECTION OUTPUT ;
    USE SIGNAL ;
    PORT
      LAYER M4 ;
        RECT  17.088 8.64 17.28 8.664 ;
    END
  END o[61]
  PIN o[62]
    DIRECTION OUTPUT ;
    USE SIGNAL ;
    PORT
      LAYER M4 ;
        RECT  17.088 8.736 17.28 8.76 ;
    END
  END o[62]
  PIN o[63]
    DIRECTION OUTPUT ;
    USE SIGNAL ;
    PORT
      LAYER M4 ;
        RECT  17.088 8.88 17.28 8.904 ;
    END
  END o[63]
  PIN o[64]
    DIRECTION OUTPUT ;
    USE SIGNAL ;
    PORT
      LAYER M4 ;
        RECT  17.088 8.976 17.28 9 ;
    END
  END o[64]
  PIN o[65]
    DIRECTION OUTPUT ;
    USE SIGNAL ;
    PORT
      LAYER M4 ;
        RECT  17.088 9.072 17.28 9.096 ;
    END
  END o[65]
  PIN o[66]
    DIRECTION OUTPUT ;
    USE SIGNAL ;
    PORT
      LAYER M4 ;
        RECT  17.088 9.168 17.28 9.192 ;
    END
  END o[66]
  PIN o[67]
    DIRECTION OUTPUT ;
    USE SIGNAL ;
    PORT
      LAYER M4 ;
        RECT  17.088 9.264 17.28 9.288 ;
    END
  END o[67]
  PIN o[68]
    DIRECTION OUTPUT ;
    USE SIGNAL ;
    PORT
      LAYER M4 ;
        RECT  17.088 9.36 17.28 9.384 ;
    END
  END o[68]
  PIN o[69]
    DIRECTION OUTPUT ;
    USE SIGNAL ;
    PORT
      LAYER M4 ;
        RECT  17.088 9.504 17.28 9.528 ;
    END
  END o[69]
  PIN o[6]
    DIRECTION OUTPUT ;
    USE SIGNAL ;
    PORT
      LAYER M4 ;
        RECT  17.088 2.88 17.28 2.904 ;
    END
  END o[6]
  PIN o[70]
    DIRECTION OUTPUT ;
    USE SIGNAL ;
    PORT
      LAYER M4 ;
        RECT  17.088 9.6 17.28 9.624 ;
    END
  END o[70]
  PIN o[71]
    DIRECTION OUTPUT ;
    USE SIGNAL ;
    PORT
      LAYER M4 ;
        RECT  17.088 9.696 17.28 9.72 ;
    END
  END o[71]
  PIN o[72]
    DIRECTION OUTPUT ;
    USE SIGNAL ;
    PORT
      LAYER M4 ;
        RECT  17.088 9.792 17.28 9.816 ;
    END
  END o[72]
  PIN o[73]
    DIRECTION OUTPUT ;
    USE SIGNAL ;
    PORT
      LAYER M4 ;
        RECT  17.088 9.888 17.28 9.912 ;
    END
  END o[73]
  PIN o[74]
    DIRECTION OUTPUT ;
    USE SIGNAL ;
    PORT
      LAYER M4 ;
        RECT  17.088 10.032 17.28 10.056 ;
    END
  END o[74]
  PIN o[75]
    DIRECTION OUTPUT ;
    USE SIGNAL ;
    PORT
      LAYER M4 ;
        RECT  17.088 10.128 17.28 10.152 ;
    END
  END o[75]
  PIN o[76]
    DIRECTION OUTPUT ;
    USE SIGNAL ;
    PORT
      LAYER M4 ;
        RECT  17.088 10.224 17.28 10.248 ;
    END
  END o[76]
  PIN o[77]
    DIRECTION OUTPUT ;
    USE SIGNAL ;
    PORT
      LAYER M4 ;
        RECT  17.088 10.32 17.28 10.344 ;
    END
  END o[77]
  PIN o[78]
    DIRECTION OUTPUT ;
    USE SIGNAL ;
    PORT
      LAYER M4 ;
        RECT  17.088 10.416 17.28 10.44 ;
    END
  END o[78]
  PIN o[79]
    DIRECTION OUTPUT ;
    USE SIGNAL ;
    PORT
      LAYER M4 ;
        RECT  17.088 10.56 17.28 10.584 ;
    END
  END o[79]
  PIN o[7]
    DIRECTION OUTPUT ;
    USE SIGNAL ;
    PORT
      LAYER M4 ;
        RECT  17.088 2.976 17.28 3 ;
    END
  END o[7]
  PIN o[80]
    DIRECTION OUTPUT ;
    USE SIGNAL ;
    PORT
      LAYER M4 ;
        RECT  17.088 10.656 17.28 10.68 ;
    END
  END o[80]
  PIN o[81]
    DIRECTION OUTPUT ;
    USE SIGNAL ;
    PORT
      LAYER M4 ;
        RECT  17.088 10.752 17.28 10.776 ;
    END
  END o[81]
  PIN o[82]
    DIRECTION OUTPUT ;
    USE SIGNAL ;
    PORT
      LAYER M4 ;
        RECT  17.088 10.848 17.28 10.872 ;
    END
  END o[82]
  PIN o[83]
    DIRECTION OUTPUT ;
    USE SIGNAL ;
    PORT
      LAYER M4 ;
        RECT  17.088 10.944 17.28 10.968 ;
    END
  END o[83]
  PIN o[84]
    DIRECTION OUTPUT ;
    USE SIGNAL ;
    PORT
      LAYER M4 ;
        RECT  17.088 11.088 17.28 11.112 ;
    END
  END o[84]
  PIN o[85]
    DIRECTION OUTPUT ;
    USE SIGNAL ;
    PORT
      LAYER M4 ;
        RECT  17.088 11.184 17.28 11.208 ;
    END
  END o[85]
  PIN o[86]
    DIRECTION OUTPUT ;
    USE SIGNAL ;
    PORT
      LAYER M4 ;
        RECT  17.088 11.28 17.28 11.304 ;
    END
  END o[86]
  PIN o[87]
    DIRECTION OUTPUT ;
    USE SIGNAL ;
    PORT
      LAYER M4 ;
        RECT  17.088 11.376 17.28 11.4 ;
    END
  END o[87]
  PIN o[88]
    DIRECTION OUTPUT ;
    USE SIGNAL ;
    PORT
      LAYER M4 ;
        RECT  17.088 11.472 17.28 11.496 ;
    END
  END o[88]
  PIN o[89]
    DIRECTION OUTPUT ;
    USE SIGNAL ;
    PORT
      LAYER M4 ;
        RECT  17.088 11.616 17.28 11.64 ;
    END
  END o[89]
  PIN o[8]
    DIRECTION OUTPUT ;
    USE SIGNAL ;
    PORT
      LAYER M4 ;
        RECT  17.088 3.072 17.28 3.096 ;
    END
  END o[8]
  PIN o[90]
    DIRECTION OUTPUT ;
    USE SIGNAL ;
    PORT
      LAYER M4 ;
        RECT  17.088 11.712 17.28 11.736 ;
    END
  END o[90]
  PIN o[91]
    DIRECTION OUTPUT ;
    USE SIGNAL ;
    PORT
      LAYER M4 ;
        RECT  17.088 11.808 17.28 11.832 ;
    END
  END o[91]
  PIN o[92]
    DIRECTION OUTPUT ;
    USE SIGNAL ;
    PORT
      LAYER M4 ;
        RECT  17.088 11.904 17.28 11.928 ;
    END
  END o[92]
  PIN o[93]
    DIRECTION OUTPUT ;
    USE SIGNAL ;
    PORT
      LAYER M4 ;
        RECT  17.088 12 17.28 12.024 ;
    END
  END o[93]
  PIN o[94]
    DIRECTION OUTPUT ;
    USE SIGNAL ;
    PORT
      LAYER M4 ;
        RECT  17.088 12.096 17.28 12.12 ;
    END
  END o[94]
  PIN o[95]
    DIRECTION OUTPUT ;
    USE SIGNAL ;
    PORT
      LAYER M4 ;
        RECT  17.088 12.24 17.28 12.264 ;
    END
  END o[95]
  PIN o[96]
    DIRECTION OUTPUT ;
    USE SIGNAL ;
    PORT
      LAYER M4 ;
        RECT  17.088 12.336 17.28 12.36 ;
    END
  END o[96]
  PIN o[97]
    DIRECTION OUTPUT ;
    USE SIGNAL ;
    PORT
      LAYER M4 ;
        RECT  17.088 12.432 17.28 12.456 ;
    END
  END o[97]
  PIN o[98]
    DIRECTION OUTPUT ;
    USE SIGNAL ;
    PORT
      LAYER M4 ;
        RECT  17.088 12.528 17.28 12.552 ;
    END
  END o[98]
  PIN o[99]
    DIRECTION OUTPUT ;
    USE SIGNAL ;
    PORT
      LAYER M4 ;
        RECT  17.088 12.624 17.28 12.648 ;
    END
  END o[99]
  PIN o[9]
    DIRECTION OUTPUT ;
    USE SIGNAL ;
    PORT
      LAYER M4 ;
        RECT  17.088 3.168 17.28 3.192 ;
    END
  END o[9]
  PIN rs
    DIRECTION INPUT ;
    USE SIGNAL ;
    PORT
      LAYER M5 ;
        RECT  11.856 58.128 11.88 58.32 ;
    END
  END rs
  PIN VDD
    DIRECTION INOUT ;
    USE POWER ;
    PORT
      LAYER M5 ;
        RECT  13.392 2.151 13.512 56.169 ;
        RECT  10.692 2.151 10.812 56.169 ;
        RECT  7.992 2.151 8.112 56.169 ;
        RECT  5.292 2.151 5.412 56.169 ;
        RECT  2.592 2.151 2.712 56.169 ;
    END
  END VDD
  PIN VSS
    DIRECTION INOUT ;
    USE GROUND ;
    PORT
      LAYER M5 ;
        RECT  13.2 2.137 13.32 56.183 ;
        RECT  10.5 2.137 10.62 56.183 ;
        RECT  7.8 2.137 7.92 56.183 ;
        RECT  5.1 2.137 5.22 56.183 ;
        RECT  2.4 2.137 2.52 56.183 ;
    END
  END VSS
  OBS
    LAYER RVTN ;
     RECT  2.16 2.16 15.12 2.295 ;
     RECT  2.16 2.565 15.12 2.835 ;
     RECT  2.16 3.105 15.12 3.375 ;
     RECT  2.16 3.645 15.12 3.915 ;
     RECT  2.16 4.185 15.12 4.455 ;
     RECT  2.16 4.725 15.12 4.995 ;
     RECT  2.16 5.265 15.12 5.535 ;
     RECT  2.16 5.805 15.12 6.075 ;
     RECT  2.16 6.345 15.12 6.615 ;
     RECT  2.16 6.885 15.12 7.155 ;
     RECT  2.16 7.425 15.12 7.695 ;
     RECT  2.16 7.965 15.12 8.235 ;
     RECT  2.16 8.505 15.12 8.775 ;
     RECT  2.16 9.045 15.12 9.315 ;
     RECT  2.16 9.585 15.12 9.855 ;
     RECT  2.16 10.125 15.12 10.395 ;
     RECT  2.16 10.665 15.12 10.935 ;
     RECT  2.16 11.205 15.12 11.475 ;
     RECT  2.16 11.745 15.12 12.015 ;
     RECT  2.16 12.285 15.12 12.555 ;
     RECT  2.16 12.825 15.12 13.095 ;
     RECT  2.16 13.365 15.12 13.635 ;
     RECT  2.16 13.905 15.12 14.175 ;
     RECT  2.16 14.445 15.12 14.715 ;
     RECT  2.16 14.985 15.12 15.255 ;
     RECT  2.16 15.525 15.12 15.795 ;
     RECT  2.16 16.065 15.12 16.335 ;
     RECT  2.16 16.605 15.12 16.875 ;
     RECT  2.16 17.145 15.12 17.415 ;
     RECT  2.16 17.685 15.12 17.955 ;
     RECT  2.16 18.225 15.12 18.495 ;
     RECT  2.16 18.765 15.12 19.035 ;
     RECT  2.16 19.305 15.12 19.575 ;
     RECT  2.16 19.845 15.12 20.115 ;
     RECT  2.16 20.385 15.12 20.655 ;
     RECT  2.16 20.925 15.12 21.195 ;
     RECT  2.16 21.465 15.12 21.735 ;
     RECT  2.16 22.005 15.12 22.275 ;
     RECT  2.16 22.545 15.12 22.815 ;
     RECT  2.16 23.085 15.12 23.355 ;
     RECT  2.16 23.625 15.12 23.895 ;
     RECT  2.16 24.165 15.12 24.435 ;
     RECT  2.16 24.705 15.12 24.975 ;
     RECT  2.16 25.245 15.12 25.515 ;
     RECT  2.16 25.785 15.12 26.055 ;
     RECT  2.16 26.325 15.12 26.595 ;
     RECT  2.16 26.865 15.12 27.135 ;
     RECT  2.16 27.405 15.12 27.675 ;
     RECT  2.16 27.945 15.12 28.215 ;
     RECT  2.16 28.485 15.12 28.755 ;
     RECT  2.16 29.025 15.12 29.295 ;
     RECT  2.16 29.565 15.12 29.835 ;
     RECT  2.16 30.105 15.12 30.375 ;
     RECT  2.16 30.645 15.12 30.915 ;
     RECT  2.16 31.185 15.12 31.455 ;
     RECT  2.16 31.725 15.12 31.995 ;
     RECT  2.16 32.265 15.12 32.535 ;
     RECT  2.16 32.805 15.12 33.075 ;
     RECT  2.16 33.345 15.12 33.615 ;
     RECT  2.16 33.885 15.12 34.155 ;
     RECT  2.16 34.425 15.12 34.695 ;
     RECT  2.16 34.965 15.12 35.235 ;
     RECT  2.16 35.505 15.12 35.775 ;
     RECT  2.16 36.045 15.12 36.315 ;
     RECT  2.16 36.585 15.12 36.855 ;
     RECT  2.16 37.125 15.12 37.395 ;
     RECT  2.16 37.665 15.12 37.935 ;
     RECT  2.16 38.205 15.12 38.475 ;
     RECT  2.16 38.745 15.12 39.015 ;
     RECT  2.16 39.285 15.12 39.555 ;
     RECT  2.16 39.825 15.12 40.095 ;
     RECT  2.16 40.365 15.12 40.635 ;
     RECT  2.16 40.905 15.12 41.175 ;
     RECT  2.16 41.445 15.12 41.715 ;
     RECT  2.16 41.985 15.12 42.255 ;
     RECT  2.16 42.525 15.12 42.795 ;
     RECT  2.16 43.065 15.12 43.335 ;
     RECT  2.16 43.605 15.12 43.875 ;
     RECT  2.16 44.145 15.12 44.415 ;
     RECT  2.16 44.685 15.12 44.955 ;
     RECT  2.16 45.225 15.12 45.495 ;
     RECT  2.16 45.765 15.12 46.035 ;
     RECT  2.16 46.305 15.12 46.575 ;
     RECT  2.16 46.845 15.12 47.115 ;
     RECT  2.16 47.385 15.12 47.655 ;
     RECT  2.16 47.925 15.12 48.195 ;
     RECT  2.16 48.465 15.12 48.735 ;
     RECT  2.16 49.005 15.12 49.275 ;
     RECT  2.16 49.545 15.12 49.815 ;
     RECT  2.16 50.085 15.12 50.355 ;
     RECT  2.16 50.625 15.12 50.895 ;
     RECT  2.16 51.165 15.12 51.435 ;
     RECT  2.16 51.705 15.12 51.975 ;
     RECT  2.16 52.245 15.12 52.515 ;
     RECT  2.16 52.785 15.12 53.055 ;
     RECT  2.16 53.325 15.12 53.595 ;
     RECT  2.16 53.865 15.12 54.135 ;
     RECT  2.16 54.405 15.12 54.675 ;
     RECT  2.16 54.945 15.12 55.215 ;
     RECT  2.16 55.485 15.12 55.755 ;
     RECT  2.16 56.025 15.12 56.16 ;
    LAYER RVTP ;
     RECT  2.16 2.295 15.12 2.565 ;
     RECT  2.16 2.835 15.12 3.105 ;
     RECT  2.16 3.375 15.12 3.645 ;
     RECT  2.16 3.915 15.12 4.185 ;
     RECT  2.16 4.455 15.12 4.725 ;
     RECT  2.16 4.995 15.12 5.265 ;
     RECT  2.16 5.535 15.12 5.805 ;
     RECT  2.16 6.075 15.12 6.345 ;
     RECT  2.16 6.615 15.12 6.885 ;
     RECT  2.16 7.155 15.12 7.425 ;
     RECT  2.16 7.695 15.12 7.965 ;
     RECT  2.16 8.235 15.12 8.505 ;
     RECT  2.16 8.775 15.12 9.045 ;
     RECT  2.16 9.315 15.12 9.585 ;
     RECT  2.16 9.855 15.12 10.125 ;
     RECT  2.16 10.395 15.12 10.665 ;
     RECT  2.16 10.935 15.12 11.205 ;
     RECT  2.16 11.475 15.12 11.745 ;
     RECT  2.16 12.015 15.12 12.285 ;
     RECT  2.16 12.555 15.12 12.825 ;
     RECT  2.16 13.095 15.12 13.365 ;
     RECT  2.16 13.635 15.12 13.905 ;
     RECT  2.16 14.175 15.12 14.445 ;
     RECT  2.16 14.715 15.12 14.985 ;
     RECT  2.16 15.255 15.12 15.525 ;
     RECT  2.16 15.795 15.12 16.065 ;
     RECT  2.16 16.335 15.12 16.605 ;
     RECT  2.16 16.875 15.12 17.145 ;
     RECT  2.16 17.415 15.12 17.685 ;
     RECT  2.16 17.955 15.12 18.225 ;
     RECT  2.16 18.495 15.12 18.765 ;
     RECT  2.16 19.035 15.12 19.305 ;
     RECT  2.16 19.575 15.12 19.845 ;
     RECT  2.16 20.115 15.12 20.385 ;
     RECT  2.16 20.655 15.12 20.925 ;
     RECT  2.16 21.195 15.12 21.465 ;
     RECT  2.16 21.735 15.12 22.005 ;
     RECT  2.16 22.275 15.12 22.545 ;
     RECT  2.16 22.815 15.12 23.085 ;
     RECT  2.16 23.355 15.12 23.625 ;
     RECT  2.16 23.895 15.12 24.165 ;
     RECT  2.16 24.435 15.12 24.705 ;
     RECT  2.16 24.975 15.12 25.245 ;
     RECT  2.16 25.515 15.12 25.785 ;
     RECT  2.16 26.055 15.12 26.325 ;
     RECT  2.16 26.595 15.12 26.865 ;
     RECT  2.16 27.135 15.12 27.405 ;
     RECT  2.16 27.675 15.12 27.945 ;
     RECT  2.16 28.215 15.12 28.485 ;
     RECT  2.16 28.755 15.12 29.025 ;
     RECT  2.16 29.295 15.12 29.565 ;
     RECT  2.16 29.835 15.12 30.105 ;
     RECT  2.16 30.375 15.12 30.645 ;
     RECT  2.16 30.915 15.12 31.185 ;
     RECT  2.16 31.455 15.12 31.725 ;
     RECT  2.16 31.995 15.12 32.265 ;
     RECT  2.16 32.535 15.12 32.805 ;
     RECT  2.16 33.075 15.12 33.345 ;
     RECT  2.16 33.615 15.12 33.885 ;
     RECT  2.16 34.155 15.12 34.425 ;
     RECT  2.16 34.695 15.12 34.965 ;
     RECT  2.16 35.235 15.12 35.505 ;
     RECT  2.16 35.775 15.12 36.045 ;
     RECT  2.16 36.315 15.12 36.585 ;
     RECT  2.16 36.855 15.12 37.125 ;
     RECT  2.16 37.395 15.12 37.665 ;
     RECT  2.16 37.935 15.12 38.205 ;
     RECT  2.16 38.475 15.12 38.745 ;
     RECT  2.16 39.015 15.12 39.285 ;
     RECT  2.16 39.555 15.12 39.825 ;
     RECT  2.16 40.095 15.12 40.365 ;
     RECT  2.16 40.635 15.12 40.905 ;
     RECT  2.16 41.175 15.12 41.445 ;
     RECT  2.16 41.715 15.12 41.985 ;
     RECT  2.16 42.255 15.12 42.525 ;
     RECT  2.16 42.795 15.12 43.065 ;
     RECT  2.16 43.335 15.12 43.605 ;
     RECT  2.16 43.875 15.12 44.145 ;
     RECT  2.16 44.415 15.12 44.685 ;
     RECT  2.16 44.955 15.12 45.225 ;
     RECT  2.16 45.495 15.12 45.765 ;
     RECT  2.16 46.035 15.12 46.305 ;
     RECT  2.16 46.575 15.12 46.845 ;
     RECT  2.16 47.115 15.12 47.385 ;
     RECT  2.16 47.655 15.12 47.925 ;
     RECT  2.16 48.195 15.12 48.465 ;
     RECT  2.16 48.735 15.12 49.005 ;
     RECT  2.16 49.275 15.12 49.545 ;
     RECT  2.16 49.815 15.12 50.085 ;
     RECT  2.16 50.355 15.12 50.625 ;
     RECT  2.16 50.895 15.12 51.165 ;
     RECT  2.16 51.435 15.12 51.705 ;
     RECT  2.16 51.975 15.12 52.245 ;
     RECT  2.16 52.515 15.12 52.785 ;
     RECT  2.16 53.055 15.12 53.325 ;
     RECT  2.16 53.595 15.12 53.865 ;
     RECT  2.16 54.135 15.12 54.405 ;
     RECT  2.16 54.675 15.12 54.945 ;
     RECT  2.16 55.215 15.12 55.485 ;
     RECT  2.16 55.755 15.12 56.025 ;
    LAYER M1 ;
     RECT  2.16 2.151 15.12 56.169 ;
    LAYER M2 ;
     RECT  0.211 36.981 0.283 36.999 ;
     RECT  0.211 9.936 0.311 10.62 ;
     RECT  0.211 17.082 0.311 17.64 ;
     RECT  0.211 18.468 0.311 18.486 ;
     RECT  0.211 27.072 0.311 27.09 ;
     RECT  0.211 34.776 0.311 34.794 ;
     RECT  0.211 45.036 0.311 45.054 ;
     RECT  0.211 48.132 0.311 48.15 ;
     RECT  0.211 51.831 0.311 51.849 ;
     RECT  0.211 55.881 0.311 55.899 ;
     RECT  0.211 3.816 0.347 3.834 ;
     RECT  0.247 25.326 0.347 25.344 ;
     RECT  0.211 39.6 0.347 39.618 ;
     RECT  0.283 36.9 0.419 37.044 ;
     RECT  0.419 37.026 0.491 37.044 ;
     RECT  0.463 1.998 0.535 2.016 ;
     RECT  0.319 2.772 0.535 2.79 ;
     RECT  0.211 13.068 0.535 13.086 ;
     RECT  0.311 17.082 0.535 17.1 ;
     RECT  0.211 48.942 0.535 48.96 ;
     RECT  0.211 52.992 0.535 53.01 ;
     RECT  0.535 22.212 0.635 22.374 ;
     RECT  0.535 42.606 0.635 43.434 ;
     RECT  0.535 6.822 1.111 6.84 ;
     RECT  0.535 16.848 1.211 17.1 ;
     RECT  1.219 15.84 1.319 15.858 ;
     RECT  0.535 1.998 2.16 2.79 ;
     RECT  0.535 4.5 2.16 4.518 ;
     RECT  1.111 6.39 2.16 6.84 ;
     RECT  0.535 12.366 2.16 13.086 ;
     RECT  1.211 16.92 2.16 17.1 ;
     RECT  0.535 21.276 2.16 21.294 ;
     RECT  0.635 22.212 2.16 22.23 ;
     RECT  0.535 26.37 2.16 26.388 ;
     RECT  0.211 27.918 2.16 27.936 ;
     RECT  0.247 31.194 2.16 31.212 ;
     RECT  0.535 37.602 2.16 38.196 ;
     RECT  0.635 42.606 2.16 43.326 ;
     RECT  1.687 46.008 2.16 46.026 ;
     RECT  0.535 48.942 2.16 49.374 ;
     RECT  0.535 52.866 2.16 53.01 ;
     RECT  2.16 1.998 2.551 56.169 ;
     RECT  2.551 1.998 5.611 56.25 ;
     RECT  5.611 1.998 7.411 56.394 ;
     RECT  7.411 1.962 9.779 56.394 ;
     RECT  9.779 1.962 11.111 56.322 ;
     RECT  11.111 1.998 12.587 56.322 ;
     RECT  12.587 2.07 13.495 56.322 ;
     RECT  13.495 1.998 13.559 56.322 ;
     RECT  13.559 1.998 14.855 56.214 ;
     RECT  14.855 2.106 15.431 56.214 ;
     RECT  15.431 2.106 16.007 23.814 ;
     RECT  15.431 41.616 16.007 56.214 ;
     RECT  16.007 3.006 16.043 13.662 ;
     RECT  16.007 14.526 16.043 23.814 ;
     RECT  15.431 24.606 16.043 40.824 ;
     RECT  16.007 2.196 16.511 2.214 ;
     RECT  16.043 11.106 16.511 13.662 ;
     RECT  16.043 14.526 16.511 16.524 ;
     RECT  16.043 17.766 16.511 23.814 ;
     RECT  16.043 35.406 16.511 38.466 ;
     RECT  16.043 39.366 16.511 40.824 ;
     RECT  16.007 41.616 16.511 42.174 ;
     RECT  16.007 48.366 16.511 56.214 ;
     RECT  16.043 3.276 16.547 10.152 ;
     RECT  16.511 11.376 16.547 12.546 ;
     RECT  16.511 13.536 16.547 13.662 ;
     RECT  16.511 14.526 16.547 14.544 ;
     RECT  16.511 15.498 16.547 16.524 ;
     RECT  16.511 17.766 16.547 19.134 ;
     RECT  16.511 20.016 16.547 23.31 ;
     RECT  16.043 24.606 16.547 34.524 ;
     RECT  16.511 35.586 16.547 35.604 ;
     RECT  16.511 36.486 16.547 38.466 ;
     RECT  16.511 39.366 16.547 40.626 ;
     RECT  16.511 41.76 16.547 42.174 ;
     RECT  16.007 43.308 16.547 47.574 ;
     RECT  16.511 48.546 16.547 54.396 ;
     RECT  16.511 55.566 16.547 56.214 ;
     RECT  16.547 3.384 16.583 3.402 ;
     RECT  16.547 6.048 16.583 6.066 ;
     RECT  16.547 7.398 16.583 7.416 ;
     RECT  16.547 9.486 16.583 9.504 ;
     RECT  16.547 15.966 16.583 15.984 ;
     RECT  16.547 19.008 16.583 19.026 ;
     RECT  16.547 20.016 16.583 20.034 ;
     RECT  16.547 21.276 16.583 21.294 ;
     RECT  16.547 26.334 16.583 26.586 ;
     RECT  16.547 28.458 16.583 28.476 ;
     RECT  16.547 31.23 16.583 32.364 ;
     RECT  16.547 36.486 16.583 36.504 ;
     RECT  16.547 44.766 16.583 44.784 ;
     RECT  16.547 46.548 16.583 47.304 ;
     RECT  16.547 52.866 16.583 53.316 ;
     RECT  16.547 8.442 16.619 8.46 ;
     RECT  16.547 11.79 16.619 12.546 ;
     RECT  16.583 26.334 16.619 26.352 ;
     RECT  16.583 31.23 16.619 31.248 ;
     RECT  16.583 32.346 16.619 32.364 ;
     RECT  16.547 33.66 16.619 33.678 ;
     RECT  16.547 37.566 16.619 37.584 ;
     RECT  16.547 50.706 16.619 50.994 ;
     RECT  16.583 53.298 16.619 53.316 ;
     RECT  16.547 54.378 16.619 54.396 ;
     RECT  16.619 12.528 17.087 12.546 ;
     RECT  16.583 47.286 17.087 47.304 ;
    LAYER M3 ;
     RECT  11.088 1.957 11.106 1.993 ;
     RECT  0.468 1.993 0.486 2.029 ;
     RECT  13.5 1.993 13.518 2.065 ;
     RECT  4.5 2.065 4.518 2.101 ;
     RECT  10.656 1.993 11.106 2.101 ;
     RECT  3.96 2.101 4.626 2.143 ;
     RECT  7.416 1.957 7.434 2.143 ;
     RECT  10.656 2.101 11.754 2.143 ;
     RECT  12.564 1.993 12.582 2.143 ;
     RECT  13.5 2.065 14.022 2.143 ;
     RECT  15.984 2.101 16.002 2.191 ;
     RECT  2.415 2.143 2.505 2.203 ;
     RECT  10.515 2.143 11.754 2.219 ;
     RECT  15.984 2.191 16.506 2.237 ;
     RECT  2.304 2.203 2.505 2.263 ;
     RECT  6.3 2.101 6.318 2.263 ;
     RECT  7.416 2.143 7.905 2.293 ;
     RECT  8.712 1.993 8.73 2.293 ;
     RECT  6.12 2.263 6.318 2.299 ;
     RECT  7.416 2.293 8.73 2.299 ;
     RECT  6.12 2.299 9.63 2.335 ;
     RECT  10.515 2.219 10.926 2.335 ;
     RECT  6.12 2.335 10.926 2.336 ;
     RECT  3.96 2.143 5.205 2.413 ;
     RECT  14.832 1.993 14.85 2.443 ;
     RECT  15.984 2.237 16.002 2.443 ;
     RECT  10.152 2.336 10.926 2.489 ;
     RECT  12.564 2.143 14.022 2.569 ;
     RECT  2.304 2.263 3.222 2.605 ;
     RECT  3.96 2.413 5.397 2.605 ;
     RECT  12.564 2.569 14.094 2.605 ;
     RECT  2.304 2.605 5.397 2.641 ;
     RECT  6.12 2.336 9.414 2.641 ;
     RECT  0.468 2.029 0.558 2.731 ;
     RECT  2.304 2.641 9.414 2.759 ;
     RECT  10.188 2.489 10.926 2.759 ;
     RECT  11.916 2.605 14.094 2.759 ;
     RECT  0.252 2.731 0.558 2.861 ;
     RECT  14.832 2.443 16.002 2.911 ;
     RECT  14.328 2.911 16.002 3.001 ;
     RECT  0.324 2.861 0.558 3.005 ;
     RECT  11.916 2.759 13.497 3.029 ;
     RECT  14.328 3.001 16.038 3.029 ;
     RECT  2.304 2.759 4.266 3.065 ;
     RECT  12.492 3.029 13.497 3.065 ;
     RECT  14.4 3.029 16.038 3.065 ;
     RECT  10.188 2.759 10.818 3.149 ;
     RECT  5.004 2.759 9.414 3.197 ;
     RECT  14.796 3.065 16.038 3.271 ;
     RECT  14.796 3.271 16.542 3.293 ;
     RECT  10.188 3.149 10.797 3.341 ;
     RECT  5.115 3.197 9.414 3.343 ;
     RECT  16.524 3.293 16.542 3.379 ;
     RECT  16.524 3.379 16.578 3.533 ;
     RECT  14.796 3.293 15.426 3.749 ;
     RECT  0.252 3.595 0.27 3.787 ;
     RECT  0.216 3.787 0.27 3.811 ;
     RECT  0.216 3.811 0.342 3.839 ;
     RECT  12.528 3.065 13.497 3.839 ;
     RECT  0.252 3.839 0.342 3.917 ;
     RECT  13.14 3.839 13.497 3.931 ;
     RECT  11.772 3.847 11.79 3.947 ;
     RECT  2.304 3.065 3.222 3.955 ;
     RECT  3.96 3.065 4.266 3.955 ;
     RECT  2.304 3.955 4.302 3.991 ;
     RECT  5.115 3.343 9.774 3.991 ;
     RECT  16.524 3.533 16.542 4.117 ;
     RECT  13.14 3.931 13.59 4.171 ;
     RECT  14.832 3.749 15.426 4.219 ;
     RECT  16.488 4.117 16.542 4.219 ;
     RECT  2.304 3.991 9.774 4.363 ;
     RECT  10.515 3.341 10.797 4.363 ;
     RECT  2.304 4.363 10.926 4.415 ;
     RECT  10.515 4.415 10.926 4.493 ;
     RECT  13.14 4.171 13.914 4.523 ;
     RECT  14.832 4.219 16.542 4.523 ;
     RECT  2.304 4.415 9.774 4.559 ;
     RECT  14.832 4.523 14.886 4.559 ;
     RECT  0.54 4.495 0.558 4.589 ;
     RECT  4.032 4.559 9.774 4.685 ;
     RECT  6.192 4.685 9.774 4.781 ;
     RECT  10.515 4.493 10.854 4.793 ;
     RECT  13.14 4.523 13.626 4.891 ;
     RECT  4.032 4.685 5.397 4.919 ;
     RECT  0.432 4.843 0.45 4.939 ;
     RECT  4.032 4.919 4.194 4.955 ;
     RECT  11.664 4.801 11.754 4.955 ;
     RECT  0.288 4.939 0.45 4.973 ;
     RECT  11.736 4.955 11.754 5.027 ;
     RECT  6.192 4.781 9.558 5.069 ;
     RECT  0.288 4.973 0.378 5.117 ;
     RECT  12.96 4.891 13.626 5.179 ;
     RECT  14.832 4.559 14.85 5.371 ;
     RECT  15.984 4.523 16.542 5.371 ;
     RECT  5.115 4.919 5.397 5.575 ;
     RECT  6.192 5.069 9.486 5.575 ;
     RECT  4.14 4.955 4.194 5.737 ;
     RECT  12.816 5.179 13.626 5.737 ;
     RECT  14.832 5.371 16.542 5.741 ;
     RECT  10.515 4.793 10.818 5.755 ;
     RECT  10.515 5.755 11.538 5.801 ;
     RECT  14.868 5.741 16.542 5.803 ;
     RECT  2.304 4.559 3.222 5.809 ;
     RECT  4.14 5.737 4.374 5.809 ;
     RECT  12.708 5.737 14.058 5.837 ;
     RECT  0.252 5.707 0.27 5.899 ;
     RECT  5.115 5.575 9.486 6.007 ;
     RECT  14.868 5.803 16.578 6.029 ;
     RECT  16.524 6.029 16.578 6.071 ;
     RECT  12.708 5.837 13.914 6.349 ;
     RECT  2.304 5.809 4.374 6.421 ;
     RECT  5.115 6.007 9.666 6.421 ;
     RECT  14.868 6.029 15.462 6.511 ;
     RECT  12.492 6.349 13.914 6.691 ;
     RECT  14.832 6.511 15.462 6.691 ;
     RECT  2.304 6.421 9.666 6.808 ;
     RECT  10.515 5.801 10.926 6.808 ;
     RECT  12.024 6.691 15.462 6.809 ;
     RECT  0.252 5.899 0.342 6.817 ;
     RECT  1.116 6.385 1.134 6.817 ;
     RECT  12.996 6.809 15.462 6.817 ;
     RECT  16.524 6.071 16.542 6.817 ;
     RECT  0.252 6.817 1.134 6.893 ;
     RECT  12.996 6.817 16.542 6.893 ;
     RECT  12.996 6.893 15.426 6.989 ;
     RECT  12.996 6.989 14.094 7.079 ;
     RECT  14.832 6.989 15.426 7.079 ;
     RECT  12.024 6.809 12.258 7.099 ;
     RECT  0.252 6.893 0.27 7.229 ;
     RECT  2.304 6.808 10.926 7.231 ;
     RECT  11.916 7.099 12.258 7.231 ;
     RECT  16.524 6.893 16.542 7.393 ;
     RECT  1.116 6.893 1.134 7.421 ;
     RECT  2.304 7.231 12.258 7.421 ;
     RECT  16.524 7.393 16.578 7.517 ;
     RECT  16.524 7.517 16.542 7.819 ;
     RECT  16.488 7.819 16.542 7.889 ;
     RECT  12.996 7.079 13.986 7.897 ;
     RECT  14.832 7.079 14.886 7.915 ;
     RECT  2.304 7.421 11.43 7.949 ;
     RECT  2.304 7.949 3.294 7.961 ;
     RECT  12.564 7.897 13.986 8.041 ;
     RECT  14.832 7.915 15.426 8.041 ;
     RECT  4.032 7.949 11.43 8.159 ;
     RECT  12.564 8.041 15.426 8.159 ;
     RECT  16.524 7.889 16.542 8.437 ;
     RECT  16.524 8.437 16.614 8.669 ;
     RECT  2.304 7.961 3.222 8.779 ;
     RECT  4.032 8.159 10.797 8.779 ;
     RECT  11.592 8.779 11.61 8.941 ;
     RECT  13.104 8.159 15.426 8.971 ;
     RECT  16.524 8.669 16.542 8.971 ;
     RECT  11.592 8.941 12.258 8.977 ;
     RECT  13.104 8.971 16.542 8.977 ;
     RECT  11.592 8.977 16.542 9.005 ;
     RECT  11.592 9.005 11.61 9.041 ;
     RECT  2.304 8.779 10.797 9.113 ;
     RECT  12.492 9.005 16.542 9.239 ;
     RECT  3.852 9.113 10.797 9.355 ;
     RECT  14.22 9.239 16.542 9.389 ;
     RECT  12.492 9.239 13.497 9.419 ;
     RECT  16.488 9.389 16.542 9.481 ;
     RECT  3.852 9.355 10.854 9.509 ;
     RECT  16.488 9.481 16.578 9.629 ;
     RECT  3.852 9.509 9.774 9.689 ;
     RECT  0.252 8.635 0.27 9.883 ;
     RECT  14.22 9.389 15.462 9.917 ;
     RECT  0.252 9.883 0.306 9.931 ;
     RECT  2.304 9.113 2.97 9.965 ;
     RECT  10.515 9.509 10.854 10.129 ;
     RECT  16.488 9.629 16.542 10.163 ;
     RECT  10.515 10.129 11.466 10.229 ;
     RECT  6.12 9.689 9.774 10.291 ;
     RECT  10.515 10.229 11.106 10.291 ;
     RECT  12.564 9.419 13.497 10.327 ;
     RECT  14.22 9.917 15.426 10.327 ;
     RECT  3.852 9.689 5.397 10.471 ;
     RECT  6.12 10.291 11.106 10.471 ;
     RECT  3.852 10.471 11.106 10.499 ;
     RECT  12.564 10.327 15.426 10.589 ;
     RECT  12.564 10.589 13.59 10.637 ;
     RECT  14.436 10.589 15.426 10.651 ;
     RECT  0.216 9.931 0.306 10.733 ;
     RECT  2.304 9.965 2.697 10.741 ;
     RECT  3.852 10.499 10.962 10.741 ;
     RECT  0.216 10.733 0.234 10.781 ;
     RECT  14.436 10.651 16.038 11.083 ;
     RECT  12.6 10.637 13.59 11.165 ;
     RECT  2.304 10.741 10.962 11.173 ;
     RECT  2.268 11.173 10.962 11.227 ;
     RECT  2.268 11.227 11.07 11.309 ;
     RECT  14.436 11.083 16.506 11.371 ;
     RECT  2.304 11.309 11.07 11.399 ;
     RECT  14.364 11.371 16.542 11.408 ;
     RECT  1.152 10.987 1.17 11.419 ;
     RECT  1.152 11.419 1.278 11.549 ;
     RECT  12.6 11.165 13.497 11.641 ;
     RECT  11.52 11.515 11.61 11.669 ;
     RECT  12.564 11.641 13.497 11.713 ;
     RECT  14.796 11.408 16.542 11.785 ;
     RECT  1.152 11.549 1.242 11.837 ;
     RECT  11.736 11.713 13.497 11.939 ;
     RECT  14.796 11.785 16.614 11.939 ;
     RECT  12.096 11.939 13.497 11.975 ;
     RECT  14.832 11.939 16.614 12.029 ;
     RECT  12.492 11.975 13.497 12.283 ;
     RECT  12.492 12.283 13.59 12.331 ;
     RECT  0.252 11.611 0.27 12.361 ;
     RECT  17.064 12.523 17.082 12.56 ;
     RECT  0.252 12.361 0.558 12.571 ;
     RECT  2.304 11.399 10.797 12.571 ;
     RECT  0.252 12.571 0.666 12.701 ;
     RECT  12.492 12.331 14.094 12.859 ;
     RECT  14.832 12.029 16.002 12.955 ;
     RECT  2.304 12.571 10.854 12.991 ;
     RECT  12.06 12.859 14.094 12.991 ;
     RECT  2.304 12.991 14.094 13.055 ;
     RECT  14.832 12.955 16.506 13.085 ;
     RECT  0.216 13.063 0.234 13.229 ;
     RECT  16.488 13.085 16.506 13.483 ;
     RECT  2.304 13.055 13.662 13.568 ;
     RECT  0.252 13.483 0.27 13.613 ;
     RECT  12.78 13.568 13.662 13.667 ;
     RECT  16.488 13.483 16.542 13.709 ;
     RECT  2.304 13.568 12.006 13.829 ;
     RECT  0.288 13.723 0.306 13.901 ;
     RECT  14.832 13.085 15.426 14.011 ;
     RECT  2.304 13.829 11.43 14.171 ;
     RECT  14.544 14.011 15.426 14.203 ;
     RECT  2.304 14.171 11.394 14.243 ;
     RECT  14.544 14.203 16.002 14.243 ;
     RECT  14.544 14.243 15.426 14.341 ;
     RECT  12.78 13.667 13.497 14.491 ;
     RECT  16.488 14.443 16.542 14.549 ;
     RECT  0.252 14.395 0.27 14.573 ;
     RECT  2.304 14.243 10.926 14.639 ;
     RECT  12.528 14.491 13.497 14.791 ;
     RECT  12.492 14.791 13.497 14.909 ;
     RECT  13.215 14.909 13.497 15.016 ;
     RECT  14.292 14.341 15.426 15.016 ;
     RECT  2.304 14.639 10.797 15.089 ;
     RECT  13.215 15.016 15.426 15.179 ;
     RECT  16.488 14.549 16.506 15.179 ;
     RECT  3.996 15.089 10.797 15.287 ;
     RECT  11.736 15.259 11.754 15.296 ;
     RECT  4.212 15.287 10.797 15.323 ;
     RECT  13.215 15.179 13.95 15.521 ;
     RECT  4.392 15.323 10.797 15.565 ;
     RECT  4.392 15.565 10.818 15.601 ;
     RECT  1.368 15.595 1.386 15.643 ;
     RECT  1.152 15.643 1.386 15.773 ;
     RECT  1.152 15.773 1.314 15.863 ;
     RECT  2.304 15.089 3.186 15.871 ;
     RECT  16.524 15.355 16.542 15.883 ;
     RECT  0.252 15.787 0.27 15.979 ;
     RECT  16.524 15.883 16.578 15.989 ;
     RECT  13.215 15.521 13.497 15.997 ;
     RECT  14.832 15.179 15.426 15.997 ;
     RECT  16.524 15.989 16.542 15.997 ;
     RECT  11.916 15.421 12.114 16.069 ;
     RECT  12.96 15.997 13.497 16.069 ;
     RECT  1.152 15.863 1.278 16.109 ;
     RECT  4.392 15.601 10.926 16.267 ;
     RECT  11.916 16.069 13.497 16.267 ;
     RECT  0.252 15.979 0.342 16.301 ;
     RECT  4.392 16.267 13.497 16.363 ;
     RECT  2.304 15.871 3.33 16.375 ;
     RECT  4.392 16.363 14.094 16.375 ;
     RECT  2.304 16.375 14.094 16.439 ;
     RECT  11.988 16.439 14.094 16.529 ;
     RECT  2.304 16.439 10.797 16.589 ;
     RECT  14.832 15.997 16.542 16.681 ;
     RECT  14.508 16.681 16.542 16.685 ;
     RECT  2.304 16.589 3.402 16.835 ;
     RECT  0.324 16.301 0.342 16.843 ;
     RECT  1.152 16.109 1.17 16.843 ;
     RECT  14.508 16.685 16.038 16.943 ;
     RECT  0.324 16.843 1.206 16.952 ;
     RECT  0.324 16.952 1.17 17.077 ;
     RECT  0.216 17.077 1.17 17.117 ;
     RECT  14.616 16.943 16.038 17.117 ;
     RECT  4.14 16.589 10.797 17.213 ;
     RECT  0.216 17.117 0.558 17.357 ;
     RECT  11.988 16.529 13.662 17.383 ;
     RECT  11.988 17.383 13.734 17.447 ;
     RECT  2.415 16.835 3.402 17.455 ;
     RECT  4.14 17.213 4.194 17.455 ;
     RECT  5.004 17.213 10.797 17.581 ;
     RECT  12.384 17.447 13.734 17.609 ;
     RECT  5.004 17.581 11.43 17.645 ;
     RECT  0.216 17.357 0.306 17.66 ;
     RECT  12.384 17.609 13.59 17.753 ;
     RECT  14.616 17.117 14.922 17.761 ;
     RECT  15.984 17.117 16.038 17.761 ;
     RECT  5.004 17.645 10.854 17.789 ;
     RECT  2.415 17.455 4.194 17.851 ;
     RECT  14.436 17.761 14.922 17.851 ;
     RECT  15.984 17.761 16.542 17.851 ;
     RECT  12.384 17.753 13.554 17.879 ;
     RECT  5.115 17.789 10.854 17.915 ;
     RECT  14.436 17.851 16.542 18.059 ;
     RECT  10.515 17.915 10.854 18.427 ;
     RECT  0.252 17.66 0.306 18.46 ;
     RECT  2.304 17.851 4.194 18.535 ;
     RECT  5.115 17.915 9.666 18.535 ;
     RECT  13.104 17.879 13.554 18.535 ;
     RECT  14.436 18.059 15.462 18.535 ;
     RECT  0.216 18.46 0.306 18.557 ;
     RECT  0.216 18.557 0.27 18.605 ;
     RECT  2.304 18.535 9.666 18.667 ;
     RECT  10.515 18.427 10.962 18.667 ;
     RECT  13.104 18.535 15.462 18.769 ;
     RECT  11.988 18.463 12.006 18.805 ;
     RECT  11.736 18.805 12.006 18.811 ;
     RECT  2.304 18.667 10.962 18.955 ;
     RECT  11.736 18.811 12.114 18.955 ;
     RECT  16.524 18.059 16.542 19.003 ;
     RECT  2.304 18.955 12.114 19.051 ;
     RECT  16.524 19.003 16.578 19.138 ;
     RECT  2.304 19.051 12.294 19.229 ;
     RECT  13.032 18.769 15.462 19.265 ;
     RECT  3.96 19.229 4.374 19.301 ;
     RECT  5.115 19.229 12.294 19.301 ;
     RECT  0.252 18.605 0.27 19.373 ;
     RECT  12.024 19.301 12.294 19.381 ;
     RECT  13.032 19.265 13.878 19.381 ;
     RECT  14.724 19.265 15.462 19.483 ;
     RECT  16.488 19.138 16.578 19.483 ;
     RECT  12.024 19.381 13.878 19.499 ;
     RECT  4.14 19.301 4.374 19.535 ;
     RECT  5.115 19.301 11.286 19.769 ;
     RECT  12.024 19.499 13.497 19.853 ;
     RECT  14.724 19.483 16.578 20.011 ;
     RECT  14.292 20.011 16.578 20.045 ;
     RECT  2.304 19.229 3.186 20.119 ;
     RECT  4.14 19.535 4.23 20.155 ;
     RECT  14.292 20.045 16.542 20.237 ;
     RECT  12.492 19.853 13.497 20.281 ;
     RECT  14.292 20.237 15.426 20.281 ;
     RECT  0.252 20.107 0.27 20.285 ;
     RECT  2.304 20.119 3.222 20.389 ;
     RECT  3.96 20.155 4.23 20.389 ;
     RECT  2.304 20.389 4.23 20.489 ;
     RECT  12.492 20.281 15.426 20.579 ;
     RECT  5.115 19.769 10.854 20.587 ;
     RECT  5.115 20.587 10.926 20.623 ;
     RECT  5.115 20.623 11.43 20.683 ;
     RECT  2.412 20.489 4.23 20.723 ;
     RECT  4.104 20.723 4.23 20.731 ;
     RECT  5.112 20.683 12.006 20.731 ;
     RECT  12.78 20.579 15.426 20.849 ;
     RECT  16.488 20.237 16.542 21.163 ;
     RECT  2.412 20.723 3.366 21.211 ;
     RECT  4.104 20.731 12.006 21.227 ;
     RECT  16.488 21.163 16.578 21.299 ;
     RECT  0.54 21.271 0.558 21.341 ;
     RECT  12.78 20.849 13.497 21.469 ;
     RECT  14.328 20.849 15.426 21.505 ;
     RECT  16.488 21.299 16.542 21.505 ;
     RECT  12.708 21.469 13.497 21.631 ;
     RECT  14.328 21.505 16.542 21.631 ;
     RECT  4.104 21.227 11.538 21.659 ;
     RECT  2.304 21.211 3.366 21.775 ;
     RECT  4.104 21.659 11.286 21.775 ;
     RECT  12.708 21.631 16.542 21.973 ;
     RECT  2.304 21.775 11.286 22.013 ;
     RECT  0.54 22.207 0.558 22.315 ;
     RECT  0.54 22.315 0.63 22.379 ;
     RECT  0.54 22.379 0.558 22.397 ;
     RECT  12.564 21.973 16.542 22.585 ;
     RECT  12.384 22.585 16.542 22.613 ;
     RECT  10.515 22.013 11.286 22.621 ;
     RECT  12.384 22.613 14.886 22.711 ;
     RECT  10.515 22.621 11.502 22.739 ;
     RECT  2.304 22.013 9.738 22.775 ;
     RECT  12.312 22.711 14.886 22.781 ;
     RECT  2.34 22.775 9.738 22.819 ;
     RECT  2.34 22.819 9.774 22.855 ;
     RECT  10.515 22.739 11.43 22.855 ;
     RECT  12.312 22.781 12.33 22.883 ;
     RECT  2.34 22.855 11.43 23.189 ;
     RECT  0.252 23.131 0.27 23.261 ;
     RECT  15.984 22.613 16.542 23.315 ;
     RECT  2.34 23.189 11.286 23.515 ;
     RECT  2.304 23.515 11.286 23.597 ;
     RECT  15.984 23.315 16.506 23.729 ;
     RECT  16.488 23.729 16.506 23.819 ;
     RECT  12.312 23.863 12.33 24.089 ;
     RECT  13.104 22.781 14.886 24.235 ;
     RECT  3.78 23.597 11.286 24.241 ;
     RECT  0.252 24.187 0.27 24.317 ;
     RECT  2.304 23.597 2.898 24.379 ;
     RECT  3.78 24.241 11.322 24.379 ;
     RECT  13.104 24.235 15.426 24.403 ;
     RECT  2.304 24.379 11.322 24.619 ;
     RECT  12.888 24.403 15.426 24.971 ;
     RECT  16.524 24.523 16.542 25.051 ;
     RECT  15.408 24.971 15.426 25.147 ;
     RECT  16.488 25.051 16.542 25.147 ;
     RECT  0.252 25.099 0.27 25.291 ;
     RECT  12.888 24.971 14.562 25.313 ;
     RECT  12.888 25.313 13.497 25.321 ;
     RECT  0.252 25.291 0.342 25.349 ;
     RECT  0.252 25.349 0.27 25.373 ;
     RECT  2.304 24.619 11.394 25.411 ;
     RECT  14.256 25.313 14.562 25.439 ;
     RECT  12.528 25.321 13.497 25.517 ;
     RECT  14.544 25.439 14.562 25.789 ;
     RECT  15.408 25.147 16.542 25.789 ;
     RECT  2.304 25.411 11.502 25.819 ;
     RECT  2.304 25.819 11.754 25.825 ;
     RECT  2.304 25.825 12.33 25.852 ;
     RECT  2.268 25.852 12.33 25.979 ;
     RECT  2.268 25.979 11.61 26.015 ;
     RECT  14.544 25.789 16.542 26.051 ;
     RECT  16.524 26.051 16.542 26.203 ;
     RECT  13.215 25.517 13.497 26.221 ;
     RECT  14.544 26.051 15.426 26.221 ;
     RECT  16.524 26.203 16.614 26.357 ;
     RECT  13.215 26.221 15.426 26.401 ;
     RECT  0.54 26.365 0.558 26.429 ;
     RECT  16.524 26.357 16.578 26.591 ;
     RECT  2.304 26.015 11.61 26.699 ;
     RECT  12.996 26.401 15.426 26.699 ;
     RECT  2.304 26.699 11.466 26.789 ;
     RECT  13.032 26.699 15.426 26.897 ;
     RECT  0.252 26.875 0.306 27.052 ;
     RECT  14.22 26.897 15.426 27.101 ;
     RECT  16.524 26.591 16.542 27.259 ;
     RECT  14.22 27.101 14.922 27.329 ;
     RECT  16.488 27.259 16.542 27.337 ;
     RECT  14.724 27.329 14.922 27.365 ;
     RECT  5.115 26.789 11.466 27.445 ;
     RECT  12.204 27.373 12.222 27.445 ;
     RECT  14.832 27.365 14.922 27.509 ;
     RECT  2.304 26.789 4.338 27.571 ;
     RECT  5.115 27.445 12.222 27.571 ;
     RECT  2.304 27.571 12.222 27.599 ;
     RECT  2.304 27.599 12.006 27.635 ;
     RECT  13.032 26.897 13.497 27.679 ;
     RECT  0.216 27.052 0.306 27.691 ;
     RECT  12.996 27.679 13.497 27.715 ;
     RECT  11.628 27.635 12.006 27.779 ;
     RECT  0.216 27.691 0.342 27.869 ;
     RECT  11.628 27.779 11.79 27.869 ;
     RECT  0.216 27.869 0.234 27.965 ;
     RECT  12.996 27.715 13.986 28.049 ;
     RECT  15.984 27.337 16.542 28.219 ;
     RECT  15.984 28.219 16.578 28.349 ;
     RECT  14.832 27.509 14.886 28.381 ;
     RECT  2.304 27.635 10.797 28.411 ;
     RECT  16.488 28.349 16.578 28.481 ;
     RECT  12.996 28.049 13.95 28.561 ;
     RECT  16.488 28.481 16.542 28.985 ;
     RECT  12.276 28.561 13.95 29.029 ;
     RECT  14.832 28.381 15.426 29.029 ;
     RECT  2.304 28.411 11.43 29.057 ;
     RECT  0.252 28.891 0.27 29.069 ;
     RECT  12.276 29.029 15.426 29.219 ;
     RECT  2.304 29.057 11.142 29.255 ;
     RECT  13.14 29.219 15.426 29.461 ;
     RECT  5.115 29.255 11.142 29.501 ;
     RECT  11.916 29.335 12.006 29.597 ;
     RECT  11.988 29.597 12.006 29.645 ;
     RECT  10.116 29.501 11.142 29.759 ;
     RECT  13.14 29.461 15.462 29.759 ;
     RECT  16.524 28.985 16.542 29.899 ;
     RECT  16.488 29.899 16.542 29.995 ;
     RECT  2.304 29.255 4.194 30.001 ;
     RECT  13.14 29.759 14.85 30.029 ;
     RECT  2.304 30.001 4.266 30.145 ;
     RECT  13.14 30.029 13.497 30.145 ;
     RECT  10.116 29.759 11.07 30.209 ;
     RECT  5.115 29.501 9.378 30.271 ;
     RECT  10.116 30.209 10.818 30.271 ;
     RECT  12.528 30.145 13.497 30.451 ;
     RECT  12.276 30.451 13.497 30.571 ;
     RECT  2.304 30.145 4.302 30.577 ;
     RECT  5.115 30.271 10.818 30.577 ;
     RECT  15.984 29.995 16.542 30.619 ;
     RECT  11.952 30.571 13.497 30.811 ;
     RECT  11.952 30.811 13.986 30.839 ;
     RECT  15.876 30.619 16.542 30.839 ;
     RECT  14.796 30.029 14.85 30.847 ;
     RECT  2.304 30.577 10.818 30.955 ;
     RECT  14.796 30.847 14.994 30.955 ;
     RECT  2.304 30.955 10.89 31.145 ;
     RECT  16.524 30.839 16.542 31.147 ;
     RECT  12.924 30.839 13.986 31.153 ;
     RECT  14.796 30.955 15.426 31.153 ;
     RECT  2.304 31.145 9.666 31.181 ;
     RECT  16.524 31.147 16.578 31.225 ;
     RECT  16.524 31.225 16.614 31.517 ;
     RECT  12.924 31.153 15.426 31.621 ;
     RECT  16.524 31.517 16.578 31.621 ;
     RECT  11.952 30.839 12.006 31.649 ;
     RECT  12.924 31.621 16.578 31.721 ;
     RECT  10.515 31.145 10.89 31.723 ;
     RECT  15.984 31.721 16.578 31.853 ;
     RECT  0.252 29.803 0.27 31.915 ;
     RECT  12.924 31.721 14.85 31.963 ;
     RECT  10.515 31.723 11.07 32.011 ;
     RECT  2.304 31.181 9.63 32.152 ;
     RECT  10.515 32.011 11.682 32.152 ;
     RECT  0.252 31.915 0.342 32.203 ;
     RECT  16.488 31.853 16.578 32.237 ;
     RECT  2.304 32.152 11.682 32.261 ;
     RECT  2.304 32.261 11.178 32.285 ;
     RECT  16.524 32.237 16.578 32.341 ;
     RECT  2.304 32.285 11.142 32.369 ;
     RECT  12.528 31.963 14.85 32.431 ;
     RECT  2.304 32.369 11.07 32.459 ;
     RECT  11.952 32.431 14.85 32.477 ;
     RECT  0.252 32.203 0.558 32.525 ;
     RECT  16.524 32.341 16.614 32.669 ;
     RECT  0.252 32.525 0.27 32.717 ;
     RECT  11.952 32.477 14.67 32.729 ;
     RECT  12.564 32.729 14.67 32.909 ;
     RECT  12.708 32.909 14.67 32.999 ;
     RECT  12.78 32.999 14.67 33.241 ;
     RECT  15.408 32.875 15.426 33.241 ;
     RECT  12.78 33.241 15.426 33.259 ;
     RECT  16.524 32.669 16.542 33.259 ;
     RECT  12.78 33.259 16.542 33.293 ;
     RECT  13.104 33.293 16.542 33.305 ;
     RECT  13.104 33.305 15.426 33.539 ;
     RECT  16.488 33.305 16.542 33.655 ;
     RECT  0.252 33.739 0.27 33.835 ;
     RECT  13.176 33.539 15.426 33.917 ;
     RECT  16.488 33.655 16.614 33.917 ;
     RECT  14.22 33.917 15.426 34.027 ;
     RECT  16.488 33.917 16.542 34.027 ;
     RECT  12.24 33.889 12.258 34.079 ;
     RECT  13.176 33.917 13.497 34.501 ;
     RECT  0.252 33.835 0.306 34.603 ;
     RECT  14.22 34.027 16.542 34.691 ;
     RECT  2.304 32.459 10.797 34.699 ;
     RECT  12.996 34.501 13.497 34.735 ;
     RECT  14.22 34.691 14.382 34.735 ;
     RECT  0.216 34.603 0.306 34.799 ;
     RECT  12.996 34.735 14.382 34.969 ;
     RECT  2.304 34.699 10.854 35.179 ;
     RECT  15.408 34.691 16.542 35.213 ;
     RECT  2.304 35.179 11.502 35.303 ;
     RECT  12.816 34.969 14.382 35.501 ;
     RECT  6.12 35.303 11.502 35.581 ;
     RECT  12.816 35.501 13.662 35.581 ;
     RECT  16.488 35.213 16.542 35.609 ;
     RECT  15.408 35.213 15.462 35.611 ;
     RECT  0.252 34.799 0.27 35.693 ;
     RECT  6.12 35.581 13.662 35.699 ;
     RECT  6.12 35.699 11.07 35.735 ;
     RECT  0.324 35.707 0.342 35.885 ;
     RECT  2.304 35.303 5.397 35.969 ;
     RECT  2.304 35.969 4.302 36.005 ;
     RECT  16.488 35.609 16.506 36.041 ;
     RECT  14.436 35.611 15.462 36.311 ;
     RECT  5.115 35.969 5.397 36.355 ;
     RECT  6.12 35.735 10.797 36.355 ;
     RECT  4.14 36.005 4.302 36.419 ;
     RECT  16.524 36.427 16.542 36.481 ;
     RECT  16.524 36.481 16.578 36.557 ;
     RECT  5.115 36.355 10.797 36.625 ;
     RECT  0.252 36.475 0.27 36.715 ;
     RECT  11.952 35.699 13.497 36.787 ;
     RECT  0.252 36.715 0.414 36.859 ;
     RECT  14.436 36.311 14.454 36.859 ;
     RECT  15.408 36.311 15.462 36.859 ;
     RECT  0.252 36.859 0.486 36.907 ;
     RECT  2.304 36.005 3.402 36.931 ;
     RECT  4.14 36.419 4.23 36.931 ;
     RECT  5.115 36.625 10.926 36.931 ;
     RECT  11.664 36.787 13.497 36.931 ;
     RECT  5.115 36.931 13.497 37.003 ;
     RECT  0.216 36.907 0.486 37.004 ;
     RECT  5.076 37.003 13.497 37.049 ;
     RECT  16.524 36.557 16.542 37.051 ;
     RECT  14.364 36.859 14.454 37.099 ;
     RECT  5.115 37.049 13.497 37.181 ;
     RECT  14.292 37.099 14.454 37.291 ;
     RECT  15.408 36.859 15.498 37.291 ;
     RECT  11.988 37.181 13.497 37.319 ;
     RECT  12.744 37.319 13.497 37.339 ;
     RECT  14.292 37.291 15.498 37.339 ;
     RECT  12.744 37.339 15.498 37.363 ;
     RECT  16.488 37.051 16.542 37.363 ;
     RECT  5.115 37.181 10.854 37.427 ;
     RECT  2.304 36.931 4.23 37.435 ;
     RECT  12.744 37.363 16.542 37.561 ;
     RECT  0.252 37.004 0.486 37.565 ;
     RECT  5.115 37.427 10.797 37.613 ;
     RECT  2.304 37.435 4.266 37.625 ;
     RECT  12.744 37.561 16.614 37.709 ;
     RECT  12.744 37.709 16.542 38.101 ;
     RECT  2.304 37.625 4.194 38.129 ;
     RECT  2.304 38.129 3.258 38.165 ;
     RECT  0.54 37.597 0.558 38.333 ;
     RECT  4.068 38.129 4.194 38.371 ;
     RECT  12.24 38.101 16.542 38.471 ;
     RECT  5.115 37.613 5.397 38.677 ;
     RECT  6.12 37.613 10.797 38.677 ;
     RECT  4.068 38.371 4.266 38.713 ;
     RECT  5.115 38.677 10.797 38.713 ;
     RECT  4.068 38.713 10.797 38.785 ;
     RECT  12.24 38.471 16.038 38.785 ;
     RECT  2.34 38.165 3.258 38.923 ;
     RECT  12.06 38.785 16.038 38.939 ;
     RECT  4.068 38.785 10.818 38.983 ;
     RECT  12.492 38.939 16.038 39.011 ;
     RECT  4.068 38.983 10.89 39.019 ;
     RECT  2.304 38.923 3.258 39.055 ;
     RECT  4.068 39.019 11.106 39.055 ;
     RECT  2.304 39.055 11.106 39.487 ;
     RECT  2.304 39.487 11.43 39.533 ;
     RECT  12.492 39.011 15.426 39.533 ;
     RECT  0.396 39.451 0.414 39.547 ;
     RECT  0.288 39.547 0.414 39.58 ;
     RECT  0.216 39.58 0.414 39.581 ;
     RECT  2.304 39.533 10.926 39.623 ;
     RECT  12.492 39.533 14.85 39.749 ;
     RECT  0.216 39.581 0.378 39.773 ;
     RECT  0.216 39.773 0.342 39.869 ;
     RECT  0.216 39.869 0.27 39.917 ;
     RECT  16.524 39.355 16.542 40.027 ;
     RECT  16.488 40.027 16.542 40.123 ;
     RECT  13.068 39.749 14.85 40.315 ;
     RECT  15.984 40.123 16.542 40.315 ;
     RECT  2.304 39.623 10.854 40.325 ;
     RECT  11.952 40.123 11.97 40.469 ;
     RECT  13.068 40.315 16.542 40.469 ;
     RECT  5.115 40.325 10.854 40.567 ;
     RECT  14.832 40.469 16.542 40.631 ;
     RECT  0.252 39.917 0.27 40.685 ;
     RECT  14.832 40.631 16.506 40.685 ;
     RECT  13.068 40.469 13.986 40.703 ;
     RECT  5.115 40.567 11.934 40.829 ;
     RECT  14.868 40.685 16.506 40.829 ;
     RECT  13.104 40.703 13.986 41.009 ;
     RECT  2.304 40.325 4.374 41.135 ;
     RECT  2.415 41.135 4.374 41.207 ;
     RECT  13.104 41.009 13.914 41.213 ;
     RECT  3.744 41.207 4.374 41.215 ;
     RECT  5.115 40.829 11.43 41.215 ;
     RECT  0.252 41.419 0.27 41.597 ;
     RECT  14.868 40.829 15.786 41.611 ;
     RECT  3.744 41.215 11.43 41.675 ;
     RECT  14.832 41.611 16.506 41.707 ;
     RECT  12.348 41.683 12.366 41.719 ;
     RECT  13.104 41.213 13.77 41.719 ;
     RECT  12.348 41.719 13.77 41.791 ;
     RECT  2.415 41.207 2.97 41.899 ;
     RECT  14.832 41.707 16.542 41.945 ;
     RECT  14.832 41.945 15.714 41.989 ;
     RECT  3.888 41.675 11.43 42.089 ;
     RECT  3.888 42.089 10.89 42.179 ;
     RECT  14.76 41.989 15.714 42.295 ;
     RECT  2.304 41.899 2.97 42.331 ;
     RECT  16.524 41.945 16.542 42.365 ;
     RECT  12.276 41.791 13.77 42.421 ;
     RECT  0.324 42.235 0.342 42.427 ;
     RECT  2.304 42.331 3.006 42.457 ;
     RECT  3.888 42.179 10.854 42.457 ;
     RECT  2.304 42.457 10.854 42.521 ;
     RECT  0.252 42.427 0.342 42.601 ;
     RECT  0.252 42.601 0.558 42.605 ;
     RECT  14.724 42.295 15.714 42.619 ;
     RECT  0.324 42.605 0.558 42.653 ;
     RECT  2.304 42.521 10.797 42.719 ;
     RECT  12.276 42.421 13.806 42.719 ;
     RECT  14.58 42.619 15.714 42.727 ;
     RECT  13.104 42.719 13.806 43.105 ;
     RECT  14.58 42.727 16.002 43.105 ;
     RECT  13.104 43.105 16.002 43.147 ;
     RECT  11.952 42.871 12.15 43.259 ;
     RECT  13.104 43.147 16.542 43.325 ;
     RECT  0.54 42.653 0.558 43.387 ;
     RECT  0.54 43.387 0.63 43.439 ;
     RECT  0.54 43.439 0.558 43.469 ;
     RECT  3.996 42.719 10.797 43.645 ;
     RECT  3.996 43.645 10.926 43.709 ;
     RECT  15.372 43.325 16.542 43.709 ;
     RECT  11.916 43.681 11.934 43.799 ;
     RECT  13.104 43.325 14.562 44.069 ;
     RECT  7.308 43.709 10.926 44.141 ;
     RECT  2.304 42.719 3.222 44.149 ;
     RECT  3.996 43.709 6.498 44.149 ;
     RECT  12.096 44.113 12.114 44.185 ;
     RECT  13.104 44.069 14.49 44.185 ;
     RECT  12.096 44.185 14.49 44.339 ;
     RECT  12.384 44.339 14.49 44.384 ;
     RECT  15.696 43.709 16.542 44.411 ;
     RECT  2.304 44.149 6.498 44.429 ;
     RECT  2.304 44.429 4.194 44.483 ;
     RECT  5.112 44.429 6.498 44.587 ;
     RECT  7.308 44.141 9.774 44.587 ;
     RECT  16.524 44.411 16.542 44.635 ;
     RECT  16.524 44.635 16.578 44.789 ;
     RECT  10.515 44.141 10.926 44.851 ;
     RECT  10.515 44.851 11.43 44.909 ;
     RECT  10.515 44.909 10.854 44.987 ;
     RECT  12.492 44.384 14.49 45.023 ;
     RECT  0.252 43.915 0.27 45.031 ;
     RECT  5.112 44.587 9.774 45.157 ;
     RECT  10.515 44.987 10.818 45.157 ;
     RECT  12.816 45.023 14.49 45.157 ;
     RECT  15.408 44.725 15.426 45.157 ;
     RECT  0.216 45.031 0.306 45.197 ;
     RECT  0.252 45.197 0.306 45.245 ;
     RECT  5.112 45.157 10.818 45.293 ;
     RECT  2.304 44.483 4.158 45.301 ;
     RECT  5.112 45.293 9.702 45.301 ;
     RECT  12.816 45.157 15.426 45.499 ;
     RECT  16.524 44.789 16.542 45.499 ;
     RECT  0.252 45.245 0.27 45.533 ;
     RECT  12.816 45.499 16.542 45.563 ;
     RECT  2.304 45.301 9.702 45.599 ;
     RECT  3.816 45.599 9.702 45.725 ;
     RECT  12.816 45.563 15.462 45.725 ;
     RECT  10.515 45.293 10.818 45.733 ;
     RECT  12.816 45.725 14.166 45.869 ;
     RECT  12.816 45.869 14.094 45.959 ;
     RECT  2.304 45.599 3.078 45.979 ;
     RECT  3.816 45.725 4.194 45.995 ;
     RECT  10.515 45.733 10.962 46.027 ;
     RECT  1.692 45.979 3.078 46.031 ;
     RECT  1.8 46.031 3.078 46.061 ;
     RECT  10.515 46.027 11.43 46.067 ;
     RECT  5.004 45.725 9.702 46.201 ;
     RECT  10.515 46.067 10.854 46.201 ;
     RECT  16.488 45.563 16.542 46.219 ;
     RECT  1.872 46.061 3.078 46.253 ;
     RECT  12.816 45.959 13.734 46.345 ;
     RECT  12.528 46.345 13.734 46.541 ;
     RECT  2.304 46.253 3.078 46.579 ;
     RECT  15.408 45.725 15.462 46.651 ;
     RECT  16.488 46.219 16.578 46.651 ;
     RECT  15.408 46.651 16.578 46.747 ;
     RECT  14.832 46.747 16.578 46.769 ;
     RECT  4.068 45.995 4.194 46.813 ;
     RECT  11.988 46.813 12.006 46.849 ;
     RECT  5.004 46.201 10.854 46.885 ;
     RECT  2.304 46.579 3.222 46.921 ;
     RECT  3.96 46.813 4.194 46.921 ;
     RECT  12.744 46.541 13.734 46.921 ;
     RECT  14.832 46.769 15.426 46.921 ;
     RECT  2.304 46.921 4.194 46.939 ;
     RECT  5.004 46.885 10.89 46.939 ;
     RECT  11.916 46.849 12.006 47.165 ;
     RECT  12.744 46.921 15.426 47.183 ;
     RECT  2.304 46.939 10.89 47.191 ;
     RECT  12.744 47.183 13.662 47.281 ;
     RECT  16.488 46.769 16.578 47.281 ;
     RECT  2.304 47.191 11.538 47.309 ;
     RECT  0.252 46.795 0.27 47.323 ;
     RECT  2.304 47.309 11.394 47.345 ;
     RECT  16.488 47.281 17.082 47.405 ;
     RECT  0.252 47.323 0.342 47.501 ;
     RECT  2.304 47.345 3.15 47.563 ;
     RECT  16.488 47.405 16.542 47.579 ;
     RECT  14.436 47.183 15.426 47.651 ;
     RECT  16.488 47.579 16.506 47.659 ;
     RECT  2.268 47.563 3.15 47.687 ;
     RECT  3.888 47.345 11.394 47.849 ;
     RECT  5.115 47.849 11.394 47.885 ;
     RECT  12.528 47.281 13.662 48.001 ;
     RECT  0.252 47.501 0.306 48.124 ;
     RECT  12.132 48.001 13.698 48.199 ;
     RECT  14.436 47.651 14.886 48.199 ;
     RECT  2.304 47.687 3.15 48.271 ;
     RECT  3.888 47.849 4.338 48.271 ;
     RECT  12.132 48.199 14.886 48.379 ;
     RECT  12.132 48.379 14.958 48.389 ;
     RECT  12.456 48.389 14.958 48.425 ;
     RECT  15.984 47.659 16.506 48.427 ;
     RECT  0.216 48.124 0.306 48.475 ;
     RECT  2.304 48.271 4.338 48.667 ;
     RECT  5.115 47.885 11.142 48.667 ;
     RECT  2.304 48.667 11.142 48.695 ;
     RECT  12.456 48.425 13.842 48.941 ;
     RECT  13.068 48.941 13.842 49.001 ;
     RECT  0.216 48.475 0.342 49.051 ;
     RECT  1.116 49.003 1.134 49.051 ;
     RECT  0.216 49.051 1.134 49.085 ;
     RECT  0.396 49.085 1.134 49.181 ;
     RECT  12.06 49.195 12.078 49.235 ;
     RECT  2.415 48.695 11.142 49.279 ;
     RECT  2.415 49.279 11.322 49.315 ;
     RECT  13.104 49.001 13.842 49.351 ;
     RECT  14.796 48.425 14.85 49.351 ;
     RECT  14.724 49.351 14.85 49.387 ;
     RECT  15.984 48.427 16.542 49.387 ;
     RECT  0.54 49.181 1.134 49.421 ;
     RECT  2.415 49.315 11.61 49.477 ;
     RECT  13.104 49.351 13.878 49.621 ;
     RECT  0.54 49.421 0.558 49.709 ;
     RECT  14.724 49.387 16.542 49.709 ;
     RECT  14.724 49.709 15.426 49.739 ;
     RECT  2.412 49.477 11.61 49.915 ;
     RECT  13.104 49.621 13.95 49.981 ;
     RECT  16.488 49.709 16.542 50.009 ;
     RECT  2.304 49.915 11.61 50.045 ;
     RECT  2.304 50.045 10.818 50.141 ;
     RECT  2.304 50.141 3.69 50.189 ;
     RECT  13.104 49.981 14.562 50.279 ;
     RECT  4.428 50.141 10.818 50.333 ;
     RECT  0.396 50.203 0.414 50.395 ;
     RECT  0.288 50.395 0.414 50.429 ;
     RECT  4.428 50.333 10.797 50.585 ;
     RECT  0.288 50.429 0.306 50.621 ;
     RECT  16.524 50.009 16.542 50.635 ;
     RECT  13.104 50.279 14.526 50.791 ;
     RECT  12.636 50.791 14.526 50.963 ;
     RECT  16.524 50.635 16.614 50.999 ;
     RECT  11.592 50.045 11.61 51.061 ;
     RECT  2.304 50.189 3.438 51.125 ;
     RECT  2.415 51.125 3.438 51.133 ;
     RECT  4.428 50.585 9.738 51.133 ;
     RECT  11.592 51.061 12.15 51.197 ;
     RECT  2.415 51.133 9.738 51.307 ;
     RECT  10.515 50.585 10.797 51.307 ;
     RECT  13.104 50.963 14.526 51.355 ;
     RECT  15.408 49.739 15.426 51.355 ;
     RECT  2.415 51.307 10.797 51.403 ;
     RECT  2.415 51.403 11.502 51.44 ;
     RECT  13.104 51.355 15.426 51.601 ;
     RECT  2.415 51.44 11.43 51.629 ;
     RECT  13.104 51.601 15.462 51.725 ;
     RECT  13.104 51.725 15.426 51.739 ;
     RECT  0.252 51.643 0.27 51.82 ;
     RECT  0.216 51.82 0.306 51.917 ;
     RECT  2.415 51.629 11.286 51.979 ;
     RECT  12.528 51.739 15.426 52.285 ;
     RECT  0.252 51.917 0.306 52.315 ;
     RECT  12.384 52.285 15.426 52.405 ;
     RECT  2.304 51.979 11.286 52.555 ;
     RECT  2.304 52.555 11.43 52.699 ;
     RECT  12.312 52.405 15.426 52.699 ;
     RECT  2.304 52.699 15.426 52.817 ;
     RECT  16.524 50.999 16.542 52.861 ;
     RECT  2.304 52.817 11.43 52.889 ;
     RECT  12.564 52.817 15.426 52.979 ;
     RECT  0.252 52.315 0.594 52.987 ;
     RECT  2.304 52.889 11.106 52.987 ;
     RECT  0.216 52.987 0.594 53.069 ;
     RECT  2.232 52.987 11.106 53.087 ;
     RECT  0.288 53.069 0.558 53.213 ;
     RECT  2.304 53.087 11.106 53.249 ;
     RECT  12.564 52.979 13.806 53.249 ;
     RECT  16.524 52.861 16.578 53.293 ;
     RECT  0.54 53.213 0.558 53.309 ;
     RECT  16.524 53.293 16.614 53.501 ;
     RECT  13.176 53.249 13.806 53.519 ;
     RECT  14.832 52.979 15.426 53.527 ;
     RECT  16.524 53.501 16.542 53.527 ;
     RECT  10.515 53.249 11.106 53.833 ;
     RECT  14.832 53.527 16.542 54.059 ;
     RECT  13.176 53.519 13.734 54.175 ;
     RECT  14.832 54.059 15.498 54.211 ;
     RECT  2.304 53.249 9.774 54.301 ;
     RECT  10.515 53.833 11.43 54.301 ;
     RECT  12.384 54.175 13.734 54.301 ;
     RECT  14.796 54.211 15.498 54.337 ;
     RECT  16.488 54.059 16.542 54.373 ;
     RECT  0.252 54.235 0.27 54.413 ;
     RECT  2.304 54.301 13.734 54.445 ;
     RECT  14.724 54.337 15.498 54.445 ;
     RECT  2.304 54.445 15.498 54.473 ;
     RECT  16.488 54.373 16.614 54.653 ;
     RECT  2.304 54.473 14.418 54.671 ;
     RECT  2.304 54.671 14.094 54.869 ;
     RECT  15.408 54.473 15.498 55.147 ;
     RECT  16.488 54.653 16.506 55.147 ;
     RECT  15.408 55.147 16.506 55.381 ;
     RECT  11.7 54.869 14.094 55.421 ;
     RECT  14.832 55.381 16.506 55.483 ;
     RECT  13.215 55.421 14.094 55.561 ;
     RECT  14.832 55.483 16.542 55.561 ;
     RECT  11.7 55.421 12.474 55.679 ;
     RECT  2.304 54.869 10.854 55.723 ;
     RECT  11.7 55.679 11.718 55.723 ;
     RECT  2.304 55.723 11.718 55.787 ;
     RECT  2.304 55.787 10.854 55.853 ;
     RECT  13.215 55.561 16.542 55.859 ;
     RECT  0.252 55.291 0.27 55.876 ;
     RECT  11.7 55.787 11.718 55.901 ;
     RECT  0.216 55.876 0.306 55.949 ;
     RECT  2.304 55.853 5.634 55.949 ;
     RECT  13.215 55.859 14.958 55.949 ;
     RECT  15.984 55.859 16.542 55.949 ;
     RECT  2.304 55.949 3.042 55.985 ;
     RECT  3.96 55.949 5.634 55.985 ;
     RECT  6.408 55.853 10.854 55.985 ;
     RECT  0.288 55.949 0.306 55.997 ;
     RECT  14.292 55.949 14.958 55.997 ;
     RECT  4.032 55.985 5.634 56.021 ;
     RECT  6.552 55.985 10.854 56.021 ;
     RECT  14.652 55.997 14.958 56.021 ;
     RECT  9.288 56.021 10.854 56.045 ;
     RECT  9.36 56.045 10.854 56.093 ;
     RECT  14.868 56.021 14.958 56.093 ;
     RECT  9.576 56.093 10.854 56.129 ;
     RECT  14.868 56.093 14.886 56.141 ;
     RECT  4.5 56.021 5.634 56.177 ;
     RECT  9.576 56.129 10.605 56.177 ;
     RECT  13.215 55.949 13.554 56.177 ;
     RECT  4.5 56.177 4.518 56.219 ;
     RECT  12.456 55.679 12.474 56.219 ;
     RECT  13.356 56.177 13.554 56.219 ;
     RECT  16.524 55.949 16.542 56.219 ;
     RECT  2.304 55.985 2.574 56.237 ;
     RECT  2.556 56.237 2.574 56.255 ;
     RECT  6.552 56.021 8.19 56.255 ;
     RECT  9.576 56.177 10.314 56.255 ;
     RECT  7.668 56.255 8.19 56.291 ;
     RECT  9.576 56.255 9.774 56.291 ;
     RECT  7.668 56.291 7.686 56.327 ;
     RECT  13.536 56.219 13.554 56.327 ;
     RECT  5.616 56.177 5.634 56.399 ;
     RECT  9.756 56.291 9.774 56.399 ;
     RECT  5.4 57.595 5.418 58.188 ;
    LAYER M4 ;
     RECT  0.156 2.208 2.252 56.136 ;
     RECT  2.252 2.208 2.339 56.232 ;
     RECT  2.339 2.208 2.408 56.172 ;
     RECT  2.408 2.148 2.512 56.172 ;
     RECT  2.512 2.418 2.704 56.088 ;
     RECT  2.704 2.736 5.108 56.088 ;
     RECT  5.108 2.148 5.212 56.172 ;
     RECT  5.389 57.6 5.603 57.624 ;
     RECT  5.212 2.304 7.808 56.088 ;
     RECT  7.808 2.148 7.912 56.172 ;
     RECT  7.912 2.304 9.389 56.088 ;
     RECT  9.389 2.304 10.508 55.992 ;
     RECT  10.508 2.148 10.612 56.172 ;
     RECT  10.612 2.418 10.804 55.992 ;
     RECT  10.804 2.592 10.829 7.128 ;
     RECT  10.804 8.16 11.441 28.44 ;
     RECT  10.804 29.568 11.441 43.128 ;
     RECT  10.829 3.024 11.549 7.128 ;
     RECT  11.441 18.48 11.549 27.72 ;
     RECT  11.441 8.16 11.621 17.352 ;
     RECT  11.549 21.696 11.621 27.72 ;
     RECT  11.621 27.6 11.657 27.72 ;
     RECT  11.549 6.528 11.945 7.128 ;
     RECT  11.621 12.288 11.945 17.352 ;
     RECT  11.441 29.568 11.945 41.112 ;
     RECT  11.945 29.616 11.981 41.112 ;
     RECT  11.549 18.48 12.017 20.712 ;
     RECT  11.657 27.6 12.017 27.624 ;
     RECT  11.981 29.616 12.017 39.624 ;
     RECT  12.017 18.816 12.053 19.848 ;
     RECT  10.804 54.336 12.053 55.992 ;
     RECT  12.053 18.816 12.125 19.08 ;
     RECT  11.945 6.528 12.985 7.08 ;
     RECT  11.621 8.16 12.985 11.208 ;
     RECT  11.981 40.848 13.093 41.112 ;
     RECT  11.621 21.696 13.201 26.568 ;
     RECT  11.549 3.024 13.208 5.496 ;
     RECT  12.985 6.528 13.208 11.208 ;
     RECT  11.945 12.288 13.208 15.048 ;
     RECT  11.945 16.368 13.208 17.352 ;
     RECT  12.125 19.056 13.208 19.08 ;
     RECT  13.201 21.696 13.208 26.664 ;
     RECT  13.021 28.224 13.208 28.248 ;
     RECT  12.017 30.384 13.208 39.624 ;
     RECT  13.093 40.848 13.208 41.208 ;
     RECT  11.441 42.528 13.208 43.128 ;
     RECT  10.804 44.352 13.208 52.824 ;
     RECT  12.053 54.96 13.208 55.992 ;
     RECT  13.208 2.148 13.312 56.172 ;
     RECT  13.312 2.418 13.504 55.992 ;
     RECT  13.504 26.256 13.565 26.664 ;
     RECT  13.504 55.536 13.565 55.992 ;
     RECT  13.504 2.976 13.601 4.488 ;
     RECT  13.504 37.104 13.637 37.368 ;
     RECT  13.504 49.632 13.637 51.384 ;
     RECT  13.504 16.368 13.673 17.208 ;
     RECT  13.504 14.88 13.709 15.048 ;
     RECT  13.504 22.464 13.853 23.928 ;
     RECT  13.504 28.224 13.853 28.248 ;
     RECT  13.504 25.2 13.889 25.224 ;
     RECT  13.504 40.848 13.925 41.208 ;
     RECT  13.637 49.632 13.961 49.656 ;
     RECT  13.504 34.992 14.213 35.016 ;
     RECT  13.637 37.104 14.321 37.128 ;
     RECT  13.637 50.88 14.357 51.384 ;
     RECT  13.504 44.4 14.465 45 ;
     RECT  13.709 14.88 14.533 14.904 ;
     RECT  13.601 2.976 14.821 3 ;
     RECT  13.601 4.176 14.821 4.488 ;
     RECT  13.504 6.864 14.821 8.472 ;
     RECT  13.504 10.944 14.821 12.36 ;
     RECT  14.533 14.016 14.821 14.904 ;
     RECT  13.673 16.368 14.821 16.392 ;
     RECT  13.504 20.016 14.821 20.616 ;
     RECT  13.853 22.464 14.821 22.776 ;
     RECT  13.853 23.808 14.821 23.928 ;
     RECT  13.565 26.64 14.821 26.664 ;
     RECT  14.785 31.68 14.821 31.704 ;
     RECT  13.504 32.736 14.821 32.76 ;
     RECT  13.504 39.6 14.821 39.864 ;
     RECT  13.925 40.848 14.821 40.872 ;
     RECT  14.569 42.624 14.821 42.648 ;
     RECT  14.465 44.736 14.821 45 ;
     RECT  13.504 47.808 14.821 48.408 ;
     RECT  14.357 51.36 14.821 51.384 ;
     RECT  13.504 52.8 14.821 52.92 ;
     RECT  13.565 55.968 14.821 55.992 ;
     RECT  14.821 2.544 14.857 24.648 ;
     RECT  14.821 51.36 14.857 55.992 ;
     RECT  14.821 46.752 14.893 46.776 ;
     RECT  14.821 47.808 14.893 49.608 ;
     RECT  14.821 38.448 15.361 40.872 ;
     RECT  14.821 42 15.361 43.32 ;
     RECT  14.857 2.544 15.397 24.888 ;
     RECT  14.821 26.544 15.397 33.384 ;
     RECT  14.821 35.616 15.397 36.264 ;
     RECT  14.821 37.296 15.397 37.32 ;
     RECT  15.361 38.448 15.397 43.704 ;
     RECT  14.821 44.736 15.397 45.72 ;
     RECT  14.893 46.752 15.397 49.608 ;
     RECT  14.857 51.36 15.397 56.136 ;
     RECT  15.397 2.448 15.685 43.704 ;
     RECT  15.397 44.736 15.685 56.136 ;
     RECT  15.685 2.448 15.973 56.136 ;
     RECT  15.973 2.352 16.477 56.136 ;
     RECT  16.477 2.208 17.1 56.136 ;
    LAYER M5 ;
     RECT  2.4 2.137 2.52 2.151 ;
     RECT  5.1 2.137 5.22 2.151 ;
     RECT  7.8 2.137 7.92 2.151 ;
     RECT  10.5 2.137 10.62 2.151 ;
     RECT  13.2 2.137 13.32 2.151 ;
     RECT  7.8 2.151 8.112 2.821 ;
     RECT  7.8 2.821 8.712 5.653 ;
     RECT  2.4 2.151 2.712 5.845 ;
     RECT  5.1 2.151 5.412 6.133 ;
     RECT  6.912 5.653 8.712 6.323 ;
     RECT  4.992 6.133 5.412 6.805 ;
     RECT  4.992 6.805 6.36 6.995 ;
     RECT  2.4 5.845 3.288 7.379 ;
     RECT  2.4 7.379 2.712 7.573 ;
     RECT  5.1 6.995 6.36 8.485 ;
     RECT  2.304 7.573 2.712 8.627 ;
     RECT  4.608 8.485 6.36 8.915 ;
     RECT  4.608 8.915 5.544 9.253 ;
     RECT  4.224 9.253 5.544 9.443 ;
     RECT  2.4 8.627 2.712 9.925 ;
     RECT  7.8 6.323 8.712 10.213 ;
     RECT  7.296 10.213 8.712 10.309 ;
     RECT  6.768 10.309 8.712 10.499 ;
     RECT  6.864 10.499 8.712 10.739 ;
     RECT  2.4 9.925 3 10.835 ;
     RECT  4.608 9.443 5.544 11.459 ;
     RECT  7.296 10.739 8.712 12.563 ;
     RECT  7.296 12.563 8.664 12.805 ;
     RECT  6.864 12.805 8.664 12.947 ;
     RECT  4.608 11.459 5.412 13.091 ;
     RECT  7.8 12.947 8.664 14.293 ;
     RECT  7.152 14.293 8.664 14.435 ;
     RECT  2.4 10.835 2.712 15.301 ;
     RECT  4.944 13.091 5.412 15.829 ;
     RECT  1.152 15.781 1.176 15.923 ;
     RECT  7.8 14.435 8.664 16.069 ;
     RECT  4.944 15.829 5.544 16.115 ;
     RECT  5.1 16.115 5.544 16.931 ;
     RECT  5.1 16.931 5.412 18.181 ;
     RECT  2.4 15.301 3.432 18.275 ;
     RECT  7.2 16.069 8.664 18.277 ;
     RECT  0.288 18.181 0.312 18.467 ;
     RECT  7.2 18.277 9.096 18.803 ;
     RECT  7.2 18.803 8.664 19.571 ;
     RECT  7.2 19.571 8.232 20.099 ;
     RECT  2.4 18.275 2.712 20.725 ;
     RECT  2.4 20.725 2.808 20.915 ;
     RECT  9.312 21.733 9.336 21.971 ;
     RECT  7.2 20.099 8.112 22.501 ;
     RECT  7.152 22.501 8.112 25.139 ;
     RECT  7.344 25.139 8.112 26.149 ;
     RECT  7.296 26.149 8.112 26.389 ;
     RECT  7.296 26.389 8.664 26.819 ;
     RECT  7.344 26.819 8.664 28.547 ;
     RECT  5.1 18.181 6.12 29.653 ;
     RECT  16.992 30.757 17.016 30.947 ;
     RECT  5.1 29.653 6.264 31.669 ;
     RECT  7.8 28.547 8.664 31.669 ;
     RECT  5.1 31.669 8.664 32.051 ;
     RECT  7.8 32.051 8.664 32.053 ;
     RECT  7.8 32.053 9.48 32.291 ;
     RECT  7.8 32.291 8.664 36.997 ;
     RECT  2.4 20.915 2.712 38.821 ;
     RECT  2.304 38.821 2.712 39.251 ;
     RECT  7.584 36.997 8.664 39.491 ;
     RECT  5.1 32.051 6.264 40.597 ;
     RECT  5.1 40.597 6.36 41.653 ;
     RECT  5.1 41.653 6.456 42.035 ;
     RECT  7.8 39.491 8.664 43.717 ;
     RECT  5.1 42.035 5.688 44.483 ;
     RECT  5.1 44.483 5.592 47.461 ;
     RECT  7.104 43.717 8.664 47.461 ;
     RECT  5.1 47.461 8.664 47.509 ;
     RECT  5.1 47.509 9.096 48.035 ;
     RECT  5.1 48.035 8.664 49.283 ;
     RECT  7.104 49.283 8.664 50.291 ;
     RECT  10.5 2.151 10.812 50.581 ;
     RECT  5.1 49.283 5.592 50.629 ;
     RECT  7.104 50.291 8.112 50.629 ;
     RECT  5.1 50.629 8.112 50.675 ;
     RECT  2.4 39.251 2.712 51.109 ;
     RECT  2.304 51.109 2.712 51.299 ;
     RECT  7.8 50.675 8.112 51.493 ;
     RECT  7.8 51.493 8.904 51.731 ;
     RECT  7.8 51.731 8.112 52.741 ;
     RECT  5.1 50.675 6.552 53.171 ;
     RECT  7.8 52.741 8.232 53.557 ;
     RECT  7.68 53.557 8.328 53.843 ;
     RECT  7.68 53.843 8.232 54.179 ;
     RECT  7.8 54.179 8.232 55.475 ;
     RECT  10.5 50.581 11.112 55.861 ;
     RECT  10.5 55.861 11.88 56.003 ;
     RECT  2.4 51.299 2.712 56.053 ;
     RECT  2.304 56.053 2.712 56.169 ;
     RECT  7.8 55.475 8.112 56.169 ;
     RECT  10.5 56.003 10.812 56.169 ;
     RECT  13.2 2.151 13.512 56.169 ;
     RECT  2.304 56.169 2.52 56.183 ;
     RECT  5.1 53.171 5.592 56.183 ;
     RECT  7.8 56.169 7.92 56.183 ;
     RECT  10.5 56.169 10.62 56.183 ;
     RECT  13.2 56.169 13.32 56.183 ;
     RECT  2.304 56.183 2.328 56.243 ;
     RECT  5.568 56.183 5.592 57.635 ;
     RECT  11.856 56.003 11.88 58.192 ;
  END
END dsfd_dvrlyh_512_WE
END LIBRARY
